UNITS
  DATABASE MICRONS 1000 ;
END UNITS


VERSION 5.7 ;
NAMESCASESENSITIVE ON ;
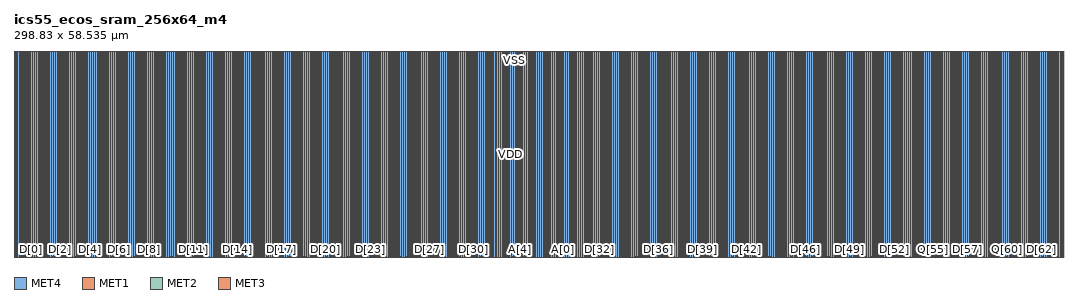
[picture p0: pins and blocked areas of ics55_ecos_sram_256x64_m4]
MACRO ics55_ecos_sram_256x64_m4
CLASS BLOCK ;
FOREIGN ics55_ecos_sram_256x64_m4 0.000 0.000 ;
ORIGIN 0.000 0.000 ;
SIZE 298.830 BY 58.535 ;
SYMMETRY X Y R90 ;

PIN VDD
  DIRECTION INOUT ;
  USE POWER ;
  PORT
    LAYER MET4 ;
    RECT 0.605 0.000 1.015 58.535 ;
    RECT 1.735 0.000 2.145 58.535 ;
    RECT 2.335 0.000 2.745 58.535 ;
    RECT 3.535 0.000 3.945 58.535 ;
    RECT 4.135 0.000 4.545 58.535 ;
    RECT 4.735 0.000 5.145 58.535 ;
    RECT 5.935 0.000 6.345 58.535 ;
    RECT 6.535 0.000 6.945 58.535 ;
    RECT 7.735 0.000 8.145 58.535 ;
    RECT 8.335 0.000 8.745 58.535 ;
    RECT 8.935 0.000 9.345 58.535 ;
    RECT 10.135 0.000 10.545 58.535 ;
    RECT 10.735 0.000 11.145 58.535 ;
    RECT 11.935 0.000 12.345 58.535 ;
    RECT 12.535 0.000 12.945 58.535 ;
    RECT 13.135 0.000 13.545 58.535 ;
    RECT 14.335 0.000 14.745 58.535 ;
    RECT 14.935 0.000 15.345 58.535 ;
    RECT 16.135 0.000 16.545 58.535 ;
    RECT 16.735 0.000 17.145 58.535 ;
    RECT 17.335 0.000 17.745 58.535 ;
    RECT 18.535 0.000 18.945 58.535 ;
    RECT 19.135 0.000 19.545 58.535 ;
    RECT 20.335 0.000 20.745 58.535 ;
    RECT 20.935 0.000 21.345 58.535 ;
    RECT 21.535 0.000 21.945 58.535 ;
    RECT 22.735 0.000 23.145 58.535 ;
    RECT 23.335 0.000 23.745 58.535 ;
    RECT 24.535 0.000 24.945 58.535 ;
    RECT 25.135 0.000 25.545 58.535 ;
    RECT 25.735 0.000 26.145 58.535 ;
    RECT 26.935 0.000 27.345 58.535 ;
    RECT 27.535 0.000 27.945 58.535 ;
    RECT 28.735 0.000 29.145 58.535 ;
    RECT 29.335 0.000 29.745 58.535 ;
    RECT 29.935 0.000 30.345 58.535 ;
    RECT 31.135 0.000 31.545 58.535 ;
    RECT 31.735 0.000 32.145 58.535 ;
    RECT 32.935 0.000 33.345 58.535 ;
    RECT 33.535 0.000 33.945 58.535 ;
    RECT 34.135 0.000 34.545 58.535 ;
    RECT 35.335 0.000 35.745 58.535 ;
    RECT 35.935 0.000 36.345 58.535 ;
    RECT 37.135 0.000 37.545 58.535 ;
    RECT 37.735 0.000 38.145 58.535 ;
    RECT 38.335 0.000 38.745 58.535 ;
    RECT 39.535 0.000 39.945 58.535 ;
    RECT 40.135 0.000 40.545 58.535 ;
    RECT 41.335 0.000 41.745 58.535 ;
    RECT 41.935 0.000 42.345 58.535 ;
    RECT 42.535 0.000 42.945 58.535 ;
    RECT 43.735 0.000 44.145 58.535 ;
    RECT 44.335 0.000 44.745 58.535 ;
    RECT 45.535 0.000 45.945 58.535 ;
    RECT 46.135 0.000 46.545 58.535 ;
    RECT 46.735 0.000 47.145 58.535 ;
    RECT 47.935 0.000 48.345 58.535 ;
    RECT 48.535 0.000 48.945 58.535 ;
    RECT 49.735 0.000 50.145 58.535 ;
    RECT 50.335 0.000 50.745 58.535 ;
    RECT 50.935 0.000 51.345 58.535 ;
    RECT 52.135 0.000 52.545 58.535 ;
    RECT 52.735 0.000 53.145 58.535 ;
    RECT 53.935 0.000 54.345 58.535 ;
    RECT 54.535 0.000 54.945 58.535 ;
    RECT 55.135 0.000 55.545 58.535 ;
    RECT 56.335 0.000 56.745 58.535 ;
    RECT 56.935 0.000 57.345 58.535 ;
    RECT 58.135 0.000 58.545 58.535 ;
    RECT 58.735 0.000 59.145 58.535 ;
    RECT 59.335 0.000 59.745 58.535 ;
    RECT 60.535 0.000 60.945 58.535 ;
    RECT 61.135 0.000 61.545 58.535 ;
    RECT 62.335 0.000 62.745 58.535 ;
    RECT 62.935 0.000 63.345 58.535 ;
    RECT 63.535 0.000 63.945 58.535 ;
    RECT 64.735 0.000 65.145 58.535 ;
    RECT 65.335 0.000 65.745 58.535 ;
    RECT 66.535 0.000 66.945 58.535 ;
    RECT 67.135 0.000 67.545 58.535 ;
    RECT 67.735 0.000 68.145 58.535 ;
    RECT 68.935 0.000 69.345 58.535 ;
    RECT 69.535 0.000 69.945 58.535 ;
    RECT 70.735 0.000 71.145 58.535 ;
    RECT 71.335 0.000 71.745 58.535 ;
    RECT 71.935 0.000 72.345 58.535 ;
    RECT 73.135 0.000 73.545 58.535 ;
    RECT 73.735 0.000 74.145 58.535 ;
    RECT 74.935 0.000 75.345 58.535 ;
    RECT 75.535 0.000 75.945 58.535 ;
    RECT 76.135 0.000 76.545 58.535 ;
    RECT 77.335 0.000 77.745 58.535 ;
    RECT 77.935 0.000 78.345 58.535 ;
    RECT 79.135 0.000 79.545 58.535 ;
    RECT 79.735 0.000 80.145 58.535 ;
    RECT 80.335 0.000 80.745 58.535 ;
    RECT 81.535 0.000 81.945 58.535 ;
    RECT 82.135 0.000 82.545 58.535 ;
    RECT 83.335 0.000 83.745 58.535 ;
    RECT 83.935 0.000 84.345 58.535 ;
    RECT 84.535 0.000 84.945 58.535 ;
    RECT 85.735 0.000 86.145 58.535 ;
    RECT 86.335 0.000 86.745 58.535 ;
    RECT 87.535 0.000 87.945 58.535 ;
    RECT 88.135 0.000 88.545 58.535 ;
    RECT 88.735 0.000 89.145 58.535 ;
    RECT 89.935 0.000 90.345 58.535 ;
    RECT 90.535 0.000 90.945 58.535 ;
    RECT 91.735 0.000 92.145 58.535 ;
    RECT 92.335 0.000 92.745 58.535 ;
    RECT 92.935 0.000 93.345 58.535 ;
    RECT 94.135 0.000 94.545 58.535 ;
    RECT 94.735 0.000 95.145 58.535 ;
    RECT 95.935 0.000 96.345 58.535 ;
    RECT 96.535 0.000 96.945 58.535 ;
    RECT 97.135 0.000 97.545 58.535 ;
    RECT 98.335 0.000 98.745 58.535 ;
    RECT 98.935 0.000 99.345 58.535 ;
    RECT 100.135 0.000 100.545 58.535 ;
    RECT 100.735 0.000 101.145 58.535 ;
    RECT 101.335 0.000 101.745 58.535 ;
    RECT 102.535 0.000 102.945 58.535 ;
    RECT 103.135 0.000 103.545 58.535 ;
    RECT 104.335 0.000 104.745 58.535 ;
    RECT 104.935 0.000 105.345 58.535 ;
    RECT 105.535 0.000 105.945 58.535 ;
    RECT 106.735 0.000 107.145 58.535 ;
    RECT 107.335 0.000 107.745 58.535 ;
    RECT 108.535 0.000 108.945 58.535 ;
    RECT 109.135 0.000 109.545 58.535 ;
    RECT 109.735 0.000 110.145 58.535 ;
    RECT 110.935 0.000 111.345 58.535 ;
    RECT 111.535 0.000 111.945 58.535 ;
    RECT 112.735 0.000 113.145 58.535 ;
    RECT 113.335 0.000 113.745 58.535 ;
    RECT 113.935 0.000 114.345 58.535 ;
    RECT 115.135 0.000 115.545 58.535 ;
    RECT 115.735 0.000 116.145 58.535 ;
    RECT 116.935 0.000 117.345 58.535 ;
    RECT 117.535 0.000 117.945 58.535 ;
    RECT 118.135 0.000 118.545 58.535 ;
    RECT 119.335 0.000 119.745 58.535 ;
    RECT 119.935 0.000 120.345 58.535 ;
    RECT 121.135 0.000 121.545 58.535 ;
    RECT 121.735 0.000 122.145 58.535 ;
    RECT 122.335 0.000 122.745 58.535 ;
    RECT 123.535 0.000 123.945 58.535 ;
    RECT 124.135 0.000 124.545 58.535 ;
    RECT 125.335 0.000 125.745 58.535 ;
    RECT 125.935 0.000 126.345 58.535 ;
    RECT 126.535 0.000 126.945 58.535 ;
    RECT 127.735 0.000 128.145 58.535 ;
    RECT 128.335 0.000 128.745 58.535 ;
    RECT 129.535 0.000 129.945 58.535 ;
    RECT 130.135 0.000 130.545 58.535 ;
    RECT 130.735 0.000 131.145 58.535 ;
    RECT 131.935 0.000 132.345 58.535 ;
    RECT 132.535 0.000 132.945 58.535 ;
    RECT 133.735 0.000 134.145 58.535 ;
    RECT 134.335 0.000 134.745 58.535 ;
    RECT 134.935 0.000 135.345 58.535 ;
    RECT 136.065 0.000 136.475 58.535 ;
    RECT 137.960 0.000 138.370 58.535 ;
    RECT 138.490 0.000 138.900 58.535 ;
    RECT 139.550 0.000 139.960 58.535 ;
    RECT 140.080 0.000 140.490 58.535 ;
    RECT 141.140 0.000 141.550 58.535 ;
    RECT 141.670 0.000 142.080 58.535 ;
    RECT 142.730 0.000 143.140 58.535 ;
    RECT 143.260 0.000 143.670 58.535 ;
    RECT 144.320 0.000 144.730 58.535 ;
    RECT 144.850 0.000 145.260 58.535 ;
    RECT 145.910 0.000 146.320 58.535 ;
    RECT 146.440 0.000 146.850 58.535 ;
    RECT 147.500 0.000 147.910 58.535 ;
    RECT 148.030 0.000 148.440 58.535 ;
    RECT 149.090 0.000 149.500 58.535 ;
    RECT 149.620 0.000 150.030 58.535 ;
    RECT 150.680 0.000 151.090 58.535 ;
    RECT 151.210 0.000 151.620 58.535 ;
    RECT 152.270 0.000 152.680 58.535 ;
    RECT 152.800 0.000 153.210 58.535 ;
    RECT 153.860 0.000 154.270 58.535 ;
    RECT 154.390 0.000 154.800 58.535 ;
    RECT 155.450 0.000 155.860 58.535 ;
    RECT 155.980 0.000 156.390 58.535 ;
    RECT 157.040 0.000 157.450 58.535 ;
    RECT 157.570 0.000 157.980 58.535 ;
    RECT 158.630 0.000 159.040 58.535 ;
    RECT 159.160 0.000 159.570 58.535 ;
    RECT 160.220 0.000 160.630 58.535 ;
    RECT 160.750 0.000 161.160 58.535 ;
    RECT 162.355 0.000 162.765 58.535 ;
    RECT 163.485 0.000 163.895 58.535 ;
    RECT 164.085 0.000 164.495 58.535 ;
    RECT 165.285 0.000 165.695 58.535 ;
    RECT 165.885 0.000 166.295 58.535 ;
    RECT 166.485 0.000 166.895 58.535 ;
    RECT 167.685 0.000 168.095 58.535 ;
    RECT 168.285 0.000 168.695 58.535 ;
    RECT 169.485 0.000 169.895 58.535 ;
    RECT 170.085 0.000 170.495 58.535 ;
    RECT 170.685 0.000 171.095 58.535 ;
    RECT 171.885 0.000 172.295 58.535 ;
    RECT 172.485 0.000 172.895 58.535 ;
    RECT 173.685 0.000 174.095 58.535 ;
    RECT 174.285 0.000 174.695 58.535 ;
    RECT 174.885 0.000 175.295 58.535 ;
    RECT 176.085 0.000 176.495 58.535 ;
    RECT 176.685 0.000 177.095 58.535 ;
    RECT 177.885 0.000 178.295 58.535 ;
    RECT 178.485 0.000 178.895 58.535 ;
    RECT 179.085 0.000 179.495 58.535 ;
    RECT 180.285 0.000 180.695 58.535 ;
    RECT 180.885 0.000 181.295 58.535 ;
    RECT 182.085 0.000 182.495 58.535 ;
    RECT 182.685 0.000 183.095 58.535 ;
    RECT 183.285 0.000 183.695 58.535 ;
    RECT 184.485 0.000 184.895 58.535 ;
    RECT 185.085 0.000 185.495 58.535 ;
    RECT 186.285 0.000 186.695 58.535 ;
    RECT 186.885 0.000 187.295 58.535 ;
    RECT 187.485 0.000 187.895 58.535 ;
    RECT 188.685 0.000 189.095 58.535 ;
    RECT 189.285 0.000 189.695 58.535 ;
    RECT 190.485 0.000 190.895 58.535 ;
    RECT 191.085 0.000 191.495 58.535 ;
    RECT 191.685 0.000 192.095 58.535 ;
    RECT 192.885 0.000 193.295 58.535 ;
    RECT 193.485 0.000 193.895 58.535 ;
    RECT 194.685 0.000 195.095 58.535 ;
    RECT 195.285 0.000 195.695 58.535 ;
    RECT 195.885 0.000 196.295 58.535 ;
    RECT 197.085 0.000 197.495 58.535 ;
    RECT 197.685 0.000 198.095 58.535 ;
    RECT 198.885 0.000 199.295 58.535 ;
    RECT 199.485 0.000 199.895 58.535 ;
    RECT 200.085 0.000 200.495 58.535 ;
    RECT 201.285 0.000 201.695 58.535 ;
    RECT 201.885 0.000 202.295 58.535 ;
    RECT 203.085 0.000 203.495 58.535 ;
    RECT 203.685 0.000 204.095 58.535 ;
    RECT 204.285 0.000 204.695 58.535 ;
    RECT 205.485 0.000 205.895 58.535 ;
    RECT 206.085 0.000 206.495 58.535 ;
    RECT 207.285 0.000 207.695 58.535 ;
    RECT 207.885 0.000 208.295 58.535 ;
    RECT 208.485 0.000 208.895 58.535 ;
    RECT 209.685 0.000 210.095 58.535 ;
    RECT 210.285 0.000 210.695 58.535 ;
    RECT 211.485 0.000 211.895 58.535 ;
    RECT 212.085 0.000 212.495 58.535 ;
    RECT 212.685 0.000 213.095 58.535 ;
    RECT 213.885 0.000 214.295 58.535 ;
    RECT 214.485 0.000 214.895 58.535 ;
    RECT 215.685 0.000 216.095 58.535 ;
    RECT 216.285 0.000 216.695 58.535 ;
    RECT 216.885 0.000 217.295 58.535 ;
    RECT 218.085 0.000 218.495 58.535 ;
    RECT 218.685 0.000 219.095 58.535 ;
    RECT 219.885 0.000 220.295 58.535 ;
    RECT 220.485 0.000 220.895 58.535 ;
    RECT 221.085 0.000 221.495 58.535 ;
    RECT 222.285 0.000 222.695 58.535 ;
    RECT 222.885 0.000 223.295 58.535 ;
    RECT 224.085 0.000 224.495 58.535 ;
    RECT 224.685 0.000 225.095 58.535 ;
    RECT 225.285 0.000 225.695 58.535 ;
    RECT 226.485 0.000 226.895 58.535 ;
    RECT 227.085 0.000 227.495 58.535 ;
    RECT 228.285 0.000 228.695 58.535 ;
    RECT 228.885 0.000 229.295 58.535 ;
    RECT 229.485 0.000 229.895 58.535 ;
    RECT 230.685 0.000 231.095 58.535 ;
    RECT 231.285 0.000 231.695 58.535 ;
    RECT 232.485 0.000 232.895 58.535 ;
    RECT 233.085 0.000 233.495 58.535 ;
    RECT 233.685 0.000 234.095 58.535 ;
    RECT 234.885 0.000 235.295 58.535 ;
    RECT 235.485 0.000 235.895 58.535 ;
    RECT 236.685 0.000 237.095 58.535 ;
    RECT 237.285 0.000 237.695 58.535 ;
    RECT 237.885 0.000 238.295 58.535 ;
    RECT 239.085 0.000 239.495 58.535 ;
    RECT 239.685 0.000 240.095 58.535 ;
    RECT 240.885 0.000 241.295 58.535 ;
    RECT 241.485 0.000 241.895 58.535 ;
    RECT 242.085 0.000 242.495 58.535 ;
    RECT 243.285 0.000 243.695 58.535 ;
    RECT 243.885 0.000 244.295 58.535 ;
    RECT 245.085 0.000 245.495 58.535 ;
    RECT 245.685 0.000 246.095 58.535 ;
    RECT 246.285 0.000 246.695 58.535 ;
    RECT 247.485 0.000 247.895 58.535 ;
    RECT 248.085 0.000 248.495 58.535 ;
    RECT 249.285 0.000 249.695 58.535 ;
    RECT 249.885 0.000 250.295 58.535 ;
    RECT 250.485 0.000 250.895 58.535 ;
    RECT 251.685 0.000 252.095 58.535 ;
    RECT 252.285 0.000 252.695 58.535 ;
    RECT 253.485 0.000 253.895 58.535 ;
    RECT 254.085 0.000 254.495 58.535 ;
    RECT 254.685 0.000 255.095 58.535 ;
    RECT 255.885 0.000 256.295 58.535 ;
    RECT 256.485 0.000 256.895 58.535 ;
    RECT 257.685 0.000 258.095 58.535 ;
    RECT 258.285 0.000 258.695 58.535 ;
    RECT 258.885 0.000 259.295 58.535 ;
    RECT 260.085 0.000 260.495 58.535 ;
    RECT 260.685 0.000 261.095 58.535 ;
    RECT 261.885 0.000 262.295 58.535 ;
    RECT 262.485 0.000 262.895 58.535 ;
    RECT 263.085 0.000 263.495 58.535 ;
    RECT 264.285 0.000 264.695 58.535 ;
    RECT 264.885 0.000 265.295 58.535 ;
    RECT 266.085 0.000 266.495 58.535 ;
    RECT 266.685 0.000 267.095 58.535 ;
    RECT 267.285 0.000 267.695 58.535 ;
    RECT 268.485 0.000 268.895 58.535 ;
    RECT 269.085 0.000 269.495 58.535 ;
    RECT 270.285 0.000 270.695 58.535 ;
    RECT 270.885 0.000 271.295 58.535 ;
    RECT 271.485 0.000 271.895 58.535 ;
    RECT 272.685 0.000 273.095 58.535 ;
    RECT 273.285 0.000 273.695 58.535 ;
    RECT 274.485 0.000 274.895 58.535 ;
    RECT 275.085 0.000 275.495 58.535 ;
    RECT 275.685 0.000 276.095 58.535 ;
    RECT 276.885 0.000 277.295 58.535 ;
    RECT 277.485 0.000 277.895 58.535 ;
    RECT 278.685 0.000 279.095 58.535 ;
    RECT 279.285 0.000 279.695 58.535 ;
    RECT 279.885 0.000 280.295 58.535 ;
    RECT 281.085 0.000 281.495 58.535 ;
    RECT 281.685 0.000 282.095 58.535 ;
    RECT 282.885 0.000 283.295 58.535 ;
    RECT 283.485 0.000 283.895 58.535 ;
    RECT 284.085 0.000 284.495 58.535 ;
    RECT 285.285 0.000 285.695 58.535 ;
    RECT 285.885 0.000 286.295 58.535 ;
    RECT 287.085 0.000 287.495 58.535 ;
    RECT 287.685 0.000 288.095 58.535 ;
    RECT 288.285 0.000 288.695 58.535 ;
    RECT 289.485 0.000 289.895 58.535 ;
    RECT 290.085 0.000 290.495 58.535 ;
    RECT 291.285 0.000 291.695 58.535 ;
    RECT 291.885 0.000 292.295 58.535 ;
    RECT 292.485 0.000 292.895 58.535 ;
    RECT 293.685 0.000 294.095 58.535 ;
    RECT 294.285 0.000 294.695 58.535 ;
    RECT 295.485 0.000 295.895 58.535 ;
    RECT 296.085 0.000 296.495 58.535 ;
    RECT 296.685 0.000 297.095 58.535 ;
    RECT 297.815 0.000 298.225 58.535 ;
  END
END VDD

PIN VSS
  DIRECTION INOUT ;
  USE GROUND ;
  PORT
    LAYER MET4 ;
    RECT 0.075 0.000 0.485 58.535 ;
    RECT 1.135 0.000 1.545 58.535 ;
    RECT 2.935 0.000 3.345 58.535 ;
    RECT 5.335 0.000 5.745 58.535 ;
    RECT 7.135 0.000 7.545 58.535 ;
    RECT 9.535 0.000 9.945 58.535 ;
    RECT 11.335 0.000 11.745 58.535 ;
    RECT 13.735 0.000 14.145 58.535 ;
    RECT 15.535 0.000 15.945 58.535 ;
    RECT 17.935 0.000 18.345 58.535 ;
    RECT 19.735 0.000 20.145 58.535 ;
    RECT 22.135 0.000 22.545 58.535 ;
    RECT 23.935 0.000 24.345 58.535 ;
    RECT 26.335 0.000 26.745 58.535 ;
    RECT 28.135 0.000 28.545 58.535 ;
    RECT 30.535 0.000 30.945 58.535 ;
    RECT 32.335 0.000 32.745 58.535 ;
    RECT 34.735 0.000 35.145 58.535 ;
    RECT 36.535 0.000 36.945 58.535 ;
    RECT 38.935 0.000 39.345 58.535 ;
    RECT 40.735 0.000 41.145 58.535 ;
    RECT 43.135 0.000 43.545 58.535 ;
    RECT 44.935 0.000 45.345 58.535 ;
    RECT 47.335 0.000 47.745 58.535 ;
    RECT 49.135 0.000 49.545 58.535 ;
    RECT 51.535 0.000 51.945 58.535 ;
    RECT 53.335 0.000 53.745 58.535 ;
    RECT 55.735 0.000 56.145 58.535 ;
    RECT 57.535 0.000 57.945 58.535 ;
    RECT 59.935 0.000 60.345 58.535 ;
    RECT 61.735 0.000 62.145 58.535 ;
    RECT 64.135 0.000 64.545 58.535 ;
    RECT 65.935 0.000 66.345 58.535 ;
    RECT 68.335 0.000 68.745 58.535 ;
    RECT 70.135 0.000 70.545 58.535 ;
    RECT 72.535 0.000 72.945 58.535 ;
    RECT 74.335 0.000 74.745 58.535 ;
    RECT 76.735 0.000 77.145 58.535 ;
    RECT 78.535 0.000 78.945 58.535 ;
    RECT 80.935 0.000 81.345 58.535 ;
    RECT 82.735 0.000 83.145 58.535 ;
    RECT 85.135 0.000 85.545 58.535 ;
    RECT 86.935 0.000 87.345 58.535 ;
    RECT 89.335 0.000 89.745 58.535 ;
    RECT 91.135 0.000 91.545 58.535 ;
    RECT 93.535 0.000 93.945 58.535 ;
    RECT 95.335 0.000 95.745 58.535 ;
    RECT 97.735 0.000 98.145 58.535 ;
    RECT 99.535 0.000 99.945 58.535 ;
    RECT 101.935 0.000 102.345 58.535 ;
    RECT 103.735 0.000 104.145 58.535 ;
    RECT 106.135 0.000 106.545 58.535 ;
    RECT 107.935 0.000 108.345 58.535 ;
    RECT 110.335 0.000 110.745 58.535 ;
    RECT 112.135 0.000 112.545 58.535 ;
    RECT 114.535 0.000 114.945 58.535 ;
    RECT 116.335 0.000 116.745 58.535 ;
    RECT 118.735 0.000 119.145 58.535 ;
    RECT 120.535 0.000 120.945 58.535 ;
    RECT 122.935 0.000 123.345 58.535 ;
    RECT 124.735 0.000 125.145 58.535 ;
    RECT 127.135 0.000 127.545 58.535 ;
    RECT 128.935 0.000 129.345 58.535 ;
    RECT 131.335 0.000 131.745 58.535 ;
    RECT 133.135 0.000 133.545 58.535 ;
    RECT 135.535 0.000 135.945 58.535 ;
    RECT 136.595 0.000 137.005 58.535 ;
    RECT 137.430 0.000 137.840 58.535 ;
    RECT 139.020 0.000 139.430 58.535 ;
    RECT 140.610 0.000 141.020 58.535 ;
    RECT 142.200 0.000 142.610 58.535 ;
    RECT 143.790 0.000 144.200 58.535 ;
    RECT 145.380 0.000 145.790 58.535 ;
    RECT 146.970 0.000 147.380 58.535 ;
    RECT 148.560 0.000 148.970 58.535 ;
    RECT 150.150 0.000 150.560 58.535 ;
    RECT 151.740 0.000 152.150 58.535 ;
    RECT 153.330 0.000 153.740 58.535 ;
    RECT 154.920 0.000 155.330 58.535 ;
    RECT 156.510 0.000 156.920 58.535 ;
    RECT 158.100 0.000 158.510 58.535 ;
    RECT 159.690 0.000 160.100 58.535 ;
    RECT 161.280 0.000 161.690 58.535 ;
    RECT 161.825 0.000 162.235 58.535 ;
    RECT 162.885 0.000 163.295 58.535 ;
    RECT 164.685 0.000 165.095 58.535 ;
    RECT 167.085 0.000 167.495 58.535 ;
    RECT 168.885 0.000 169.295 58.535 ;
    RECT 171.285 0.000 171.695 58.535 ;
    RECT 173.085 0.000 173.495 58.535 ;
    RECT 175.485 0.000 175.895 58.535 ;
    RECT 177.285 0.000 177.695 58.535 ;
    RECT 179.685 0.000 180.095 58.535 ;
    RECT 181.485 0.000 181.895 58.535 ;
    RECT 183.885 0.000 184.295 58.535 ;
    RECT 185.685 0.000 186.095 58.535 ;
    RECT 188.085 0.000 188.495 58.535 ;
    RECT 189.885 0.000 190.295 58.535 ;
    RECT 192.285 0.000 192.695 58.535 ;
    RECT 194.085 0.000 194.495 58.535 ;
    RECT 196.485 0.000 196.895 58.535 ;
    RECT 198.285 0.000 198.695 58.535 ;
    RECT 200.685 0.000 201.095 58.535 ;
    RECT 202.485 0.000 202.895 58.535 ;
    RECT 204.885 0.000 205.295 58.535 ;
    RECT 206.685 0.000 207.095 58.535 ;
    RECT 209.085 0.000 209.495 58.535 ;
    RECT 210.885 0.000 211.295 58.535 ;
    RECT 213.285 0.000 213.695 58.535 ;
    RECT 215.085 0.000 215.495 58.535 ;
    RECT 217.485 0.000 217.895 58.535 ;
    RECT 219.285 0.000 219.695 58.535 ;
    RECT 221.685 0.000 222.095 58.535 ;
    RECT 223.485 0.000 223.895 58.535 ;
    RECT 225.885 0.000 226.295 58.535 ;
    RECT 227.685 0.000 228.095 58.535 ;
    RECT 230.085 0.000 230.495 58.535 ;
    RECT 231.885 0.000 232.295 58.535 ;
    RECT 234.285 0.000 234.695 58.535 ;
    RECT 236.085 0.000 236.495 58.535 ;
    RECT 238.485 0.000 238.895 58.535 ;
    RECT 240.285 0.000 240.695 58.535 ;
    RECT 242.685 0.000 243.095 58.535 ;
    RECT 244.485 0.000 244.895 58.535 ;
    RECT 246.885 0.000 247.295 58.535 ;
    RECT 248.685 0.000 249.095 58.535 ;
    RECT 251.085 0.000 251.495 58.535 ;
    RECT 252.885 0.000 253.295 58.535 ;
    RECT 255.285 0.000 255.695 58.535 ;
    RECT 257.085 0.000 257.495 58.535 ;
    RECT 259.485 0.000 259.895 58.535 ;
    RECT 261.285 0.000 261.695 58.535 ;
    RECT 263.685 0.000 264.095 58.535 ;
    RECT 265.485 0.000 265.895 58.535 ;
    RECT 267.885 0.000 268.295 58.535 ;
    RECT 269.685 0.000 270.095 58.535 ;
    RECT 272.085 0.000 272.495 58.535 ;
    RECT 273.885 0.000 274.295 58.535 ;
    RECT 276.285 0.000 276.695 58.535 ;
    RECT 278.085 0.000 278.495 58.535 ;
    RECT 280.485 0.000 280.895 58.535 ;
    RECT 282.285 0.000 282.695 58.535 ;
    RECT 284.685 0.000 285.095 58.535 ;
    RECT 286.485 0.000 286.895 58.535 ;
    RECT 288.885 0.000 289.295 58.535 ;
    RECT 290.685 0.000 291.095 58.535 ;
    RECT 293.085 0.000 293.495 58.535 ;
    RECT 294.885 0.000 295.295 58.535 ;
    RECT 297.285 0.000 297.695 58.535 ;
    RECT 298.345 0.000 298.755 58.535 ;
  END
END VSS

PIN D[0]
  DIRECTION INPUT ;
  PORT
    LAYER MET1 ;
    RECT 4.540 0.000 4.950 0.180 ;
    LAYER MET2 ;
    RECT 4.540 0.000 4.950 0.180 ;
    LAYER MET3 ;
    RECT 4.540 0.000 4.950 0.180 ;
  END
  ANTENNADIFFAREA                0.38930         LAYER MET1 ;
  ANTENNADIFFAREA                0.38930         LAYER MET2 ;
  ANTENNADIFFAREA                0.38930         LAYER MET3 ;
  ANTENNAGATEAREA                0.06300         LAYER MET1 ;
  ANTENNAGATEAREA                0.06300         LAYER MET2 ;
  ANTENNAGATEAREA                0.06300         LAYER MET3 ;
  ANTENNAPARTIALMETALAREA        0.09890         LAYER MET1 ;
  ANTENNAPARTIALMETALAREA        0.10380         LAYER MET2 ;
  ANTENNAMAXAREACAR              0.72381         LAYER MET1 ;
  ANTENNAMAXAREACAR              3.54286         LAYER MET2 ;
  ANTENNAMAXAREACAR              4.71429         LAYER MET3 ;
END D[0]
PIN WEB[0]
  DIRECTION INPUT ;
  PORT
    LAYER MET1 ;
    RECT 2.190 0.000 2.600 0.180 ;
    LAYER MET2 ;
    RECT 2.190 0.000 2.600 0.180 ;
    LAYER MET3 ;
    RECT 2.190 0.000 2.600 0.180 ;
  END
  ANTENNADIFFAREA                0.45930         LAYER MET1 ;
  ANTENNADIFFAREA                0.45930         LAYER MET2 ;
  ANTENNADIFFAREA                0.45930         LAYER MET3 ;
  ANTENNAGATEAREA                0.08100         LAYER MET1 ;
  ANTENNAGATEAREA                0.08100         LAYER MET2 ;
  ANTENNAGATEAREA                0.08100         LAYER MET3 ;
  ANTENNAPARTIALMETALAREA        0.14210         LAYER MET1 ;
  ANTENNAPARTIALMETALAREA        0.09360         LAYER MET2 ;
  ANTENNAMAXAREACAR              1.09630         LAYER MET1 ;
  ANTENNAMAXAREACAR              3.16296         LAYER MET2 ;
  ANTENNAMAXAREACAR              4.07407         LAYER MET3 ;
END WEB[0]
PIN Q[0]
  DIRECTION OUTPUT ;
  PORT
    LAYER MET1 ;
    RECT 3.000 0.000 3.410 0.180 ;
    LAYER MET2 ;
    RECT 3.000 0.000 3.410 0.180 ;
    LAYER MET3 ;
    RECT 3.000 0.000 3.410 0.180 ;
  END
  ANTENNADIFFAREA                0.60000         LAYER MET1 ;
  ANTENNADIFFAREA                0.60000         LAYER MET2 ;
  ANTENNADIFFAREA                0.60000         LAYER MET3 ;
  ANTENNAPARTIALMETALAREA        0.94400         LAYER MET1 ;
  ANTENNAPARTIALMETALAREA        1.33320         LAYER MET2 ;
END Q[0]
PIN D[1]
  DIRECTION INPUT ;
  PORT
    LAYER MET1 ;
    RECT 8.740 0.000 9.150 0.180 ;
    LAYER MET2 ;
    RECT 8.740 0.000 9.150 0.180 ;
    LAYER MET3 ;
    RECT 8.740 0.000 9.150 0.180 ;
  END
  ANTENNADIFFAREA                0.38930         LAYER MET1 ;
  ANTENNADIFFAREA                0.38930         LAYER MET2 ;
  ANTENNADIFFAREA                0.38930         LAYER MET3 ;
  ANTENNAGATEAREA                0.06300         LAYER MET1 ;
  ANTENNAGATEAREA                0.06300         LAYER MET2 ;
  ANTENNAGATEAREA                0.06300         LAYER MET3 ;
  ANTENNAPARTIALMETALAREA        0.09890         LAYER MET1 ;
  ANTENNAPARTIALMETALAREA        0.10380         LAYER MET2 ;
  ANTENNAMAXAREACAR              0.72381         LAYER MET1 ;
  ANTENNAMAXAREACAR              3.54286         LAYER MET2 ;
  ANTENNAMAXAREACAR              4.71429         LAYER MET3 ;
END D[1]
PIN Q[1]
  DIRECTION OUTPUT ;
  PORT
    LAYER MET1 ;
    RECT 7.200 0.000 7.610 0.180 ;
    LAYER MET2 ;
    RECT 7.200 0.000 7.610 0.180 ;
    LAYER MET3 ;
    RECT 7.200 0.000 7.610 0.180 ;
  END
  ANTENNADIFFAREA                0.60000         LAYER MET1 ;
  ANTENNADIFFAREA                0.60000         LAYER MET2 ;
  ANTENNADIFFAREA                0.60000         LAYER MET3 ;
  ANTENNAPARTIALMETALAREA        0.94400         LAYER MET1 ;
  ANTENNAPARTIALMETALAREA        1.33320         LAYER MET2 ;
END Q[1]
PIN WEB[1]
  DIRECTION INPUT ;
  PORT
    LAYER MET1 ;
    RECT 6.390 0.000 6.800 0.180 ;
    LAYER MET2 ;
    RECT 6.390 0.000 6.800 0.180 ;
    LAYER MET3 ;
    RECT 6.390 0.000 6.800 0.180 ;
  END
  ANTENNADIFFAREA                0.45930         LAYER MET1 ;
  ANTENNADIFFAREA                0.45930         LAYER MET2 ;
  ANTENNADIFFAREA                0.45930         LAYER MET3 ;
  ANTENNAGATEAREA                0.08100         LAYER MET1 ;
  ANTENNAGATEAREA                0.08100         LAYER MET2 ;
  ANTENNAGATEAREA                0.08100         LAYER MET3 ;
  ANTENNAPARTIALMETALAREA        0.14210         LAYER MET1 ;
  ANTENNAPARTIALMETALAREA        0.09360         LAYER MET2 ;
  ANTENNAMAXAREACAR              1.09630         LAYER MET1 ;
  ANTENNAMAXAREACAR              3.16296         LAYER MET2 ;
  ANTENNAMAXAREACAR              4.07407         LAYER MET3 ;
END WEB[1]
PIN D[2]
  DIRECTION INPUT ;
  PORT
    LAYER MET1 ;
    RECT 12.940 0.000 13.350 0.180 ;
    LAYER MET2 ;
    RECT 12.940 0.000 13.350 0.180 ;
    LAYER MET3 ;
    RECT 12.940 0.000 13.350 0.180 ;
  END
  ANTENNADIFFAREA                0.38930         LAYER MET1 ;
  ANTENNADIFFAREA                0.38930         LAYER MET2 ;
  ANTENNADIFFAREA                0.38930         LAYER MET3 ;
  ANTENNAGATEAREA                0.06300         LAYER MET1 ;
  ANTENNAGATEAREA                0.06300         LAYER MET2 ;
  ANTENNAGATEAREA                0.06300         LAYER MET3 ;
  ANTENNAPARTIALMETALAREA        0.09890         LAYER MET1 ;
  ANTENNAPARTIALMETALAREA        0.10380         LAYER MET2 ;
  ANTENNAMAXAREACAR              0.72381         LAYER MET1 ;
  ANTENNAMAXAREACAR              3.54286         LAYER MET2 ;
  ANTENNAMAXAREACAR              4.71429         LAYER MET3 ;
END D[2]
PIN Q[2]
  DIRECTION OUTPUT ;
  PORT
    LAYER MET1 ;
    RECT 11.400 0.000 11.810 0.180 ;
    LAYER MET2 ;
    RECT 11.400 0.000 11.810 0.180 ;
    LAYER MET3 ;
    RECT 11.400 0.000 11.810 0.180 ;
  END
  ANTENNADIFFAREA                0.60000         LAYER MET1 ;
  ANTENNADIFFAREA                0.60000         LAYER MET2 ;
  ANTENNADIFFAREA                0.60000         LAYER MET3 ;
  ANTENNAPARTIALMETALAREA        0.94400         LAYER MET1 ;
  ANTENNAPARTIALMETALAREA        1.33320         LAYER MET2 ;
END Q[2]
PIN WEB[2]
  DIRECTION INPUT ;
  PORT
    LAYER MET1 ;
    RECT 10.590 0.000 11.000 0.180 ;
    LAYER MET2 ;
    RECT 10.590 0.000 11.000 0.180 ;
    LAYER MET3 ;
    RECT 10.590 0.000 11.000 0.180 ;
  END
  ANTENNADIFFAREA                0.45930         LAYER MET1 ;
  ANTENNADIFFAREA                0.45930         LAYER MET2 ;
  ANTENNADIFFAREA                0.45930         LAYER MET3 ;
  ANTENNAGATEAREA                0.08100         LAYER MET1 ;
  ANTENNAGATEAREA                0.08100         LAYER MET2 ;
  ANTENNAGATEAREA                0.08100         LAYER MET3 ;
  ANTENNAPARTIALMETALAREA        0.14210         LAYER MET1 ;
  ANTENNAPARTIALMETALAREA        0.09360         LAYER MET2 ;
  ANTENNAMAXAREACAR              1.09630         LAYER MET1 ;
  ANTENNAMAXAREACAR              3.16296         LAYER MET2 ;
  ANTENNAMAXAREACAR              4.07407         LAYER MET3 ;
END WEB[2]
PIN WEB[5]
  DIRECTION INPUT ;
  PORT
    LAYER MET1 ;
    RECT 23.190 0.000 23.600 0.180 ;
    LAYER MET2 ;
    RECT 23.190 0.000 23.600 0.180 ;
    LAYER MET3 ;
    RECT 23.190 0.000 23.600 0.180 ;
  END
  ANTENNADIFFAREA                0.45930         LAYER MET1 ;
  ANTENNADIFFAREA                0.45930         LAYER MET2 ;
  ANTENNADIFFAREA                0.45930         LAYER MET3 ;
  ANTENNAGATEAREA                0.08100         LAYER MET1 ;
  ANTENNAGATEAREA                0.08100         LAYER MET2 ;
  ANTENNAGATEAREA                0.08100         LAYER MET3 ;
  ANTENNAPARTIALMETALAREA        0.14210         LAYER MET1 ;
  ANTENNAPARTIALMETALAREA        0.09360         LAYER MET2 ;
  ANTENNAMAXAREACAR              1.09630         LAYER MET1 ;
  ANTENNAMAXAREACAR              3.16296         LAYER MET2 ;
  ANTENNAMAXAREACAR              4.07407         LAYER MET3 ;
END WEB[5]
PIN D[6]
  DIRECTION INPUT ;
  PORT
    LAYER MET1 ;
    RECT 29.740 0.000 30.150 0.180 ;
    LAYER MET2 ;
    RECT 29.740 0.000 30.150 0.180 ;
    LAYER MET3 ;
    RECT 29.740 0.000 30.150 0.180 ;
  END
  ANTENNADIFFAREA                0.38930         LAYER MET1 ;
  ANTENNADIFFAREA                0.38930         LAYER MET2 ;
  ANTENNADIFFAREA                0.38930         LAYER MET3 ;
  ANTENNAGATEAREA                0.06300         LAYER MET1 ;
  ANTENNAGATEAREA                0.06300         LAYER MET2 ;
  ANTENNAGATEAREA                0.06300         LAYER MET3 ;
  ANTENNAPARTIALMETALAREA        0.09890         LAYER MET1 ;
  ANTENNAPARTIALMETALAREA        0.10380         LAYER MET2 ;
  ANTENNAMAXAREACAR              0.72381         LAYER MET1 ;
  ANTENNAMAXAREACAR              3.54286         LAYER MET2 ;
  ANTENNAMAXAREACAR              4.71429         LAYER MET3 ;
END D[6]
PIN D[3]
  DIRECTION INPUT ;
  PORT
    LAYER MET1 ;
    RECT 17.140 0.000 17.550 0.180 ;
    LAYER MET2 ;
    RECT 17.140 0.000 17.550 0.180 ;
    LAYER MET3 ;
    RECT 17.140 0.000 17.550 0.180 ;
  END
  ANTENNADIFFAREA                0.38930         LAYER MET1 ;
  ANTENNADIFFAREA                0.38930         LAYER MET2 ;
  ANTENNADIFFAREA                0.38930         LAYER MET3 ;
  ANTENNAGATEAREA                0.06300         LAYER MET1 ;
  ANTENNAGATEAREA                0.06300         LAYER MET2 ;
  ANTENNAGATEAREA                0.06300         LAYER MET3 ;
  ANTENNAPARTIALMETALAREA        0.09890         LAYER MET1 ;
  ANTENNAPARTIALMETALAREA        0.10380         LAYER MET2 ;
  ANTENNAMAXAREACAR              0.72381         LAYER MET1 ;
  ANTENNAMAXAREACAR              3.54286         LAYER MET2 ;
  ANTENNAMAXAREACAR              4.71429         LAYER MET3 ;
END D[3]
PIN Q[3]
  DIRECTION OUTPUT ;
  PORT
    LAYER MET1 ;
    RECT 15.600 0.000 16.010 0.180 ;
    LAYER MET2 ;
    RECT 15.600 0.000 16.010 0.180 ;
    LAYER MET3 ;
    RECT 15.600 0.000 16.010 0.180 ;
  END
  ANTENNADIFFAREA                0.60000         LAYER MET1 ;
  ANTENNADIFFAREA                0.60000         LAYER MET2 ;
  ANTENNADIFFAREA                0.60000         LAYER MET3 ;
  ANTENNAPARTIALMETALAREA        0.94400         LAYER MET1 ;
  ANTENNAPARTIALMETALAREA        1.33320         LAYER MET2 ;
END Q[3]
PIN WEB[3]
  DIRECTION INPUT ;
  PORT
    LAYER MET1 ;
    RECT 14.790 0.000 15.200 0.180 ;
    LAYER MET2 ;
    RECT 14.790 0.000 15.200 0.180 ;
    LAYER MET3 ;
    RECT 14.790 0.000 15.200 0.180 ;
  END
  ANTENNADIFFAREA                0.45930         LAYER MET1 ;
  ANTENNADIFFAREA                0.45930         LAYER MET2 ;
  ANTENNADIFFAREA                0.45930         LAYER MET3 ;
  ANTENNAGATEAREA                0.08100         LAYER MET1 ;
  ANTENNAGATEAREA                0.08100         LAYER MET2 ;
  ANTENNAGATEAREA                0.08100         LAYER MET3 ;
  ANTENNAPARTIALMETALAREA        0.14210         LAYER MET1 ;
  ANTENNAPARTIALMETALAREA        0.09360         LAYER MET2 ;
  ANTENNAMAXAREACAR              1.09630         LAYER MET1 ;
  ANTENNAMAXAREACAR              3.16296         LAYER MET2 ;
  ANTENNAMAXAREACAR              4.07407         LAYER MET3 ;
END WEB[3]
PIN D[4]
  DIRECTION INPUT ;
  PORT
    LAYER MET1 ;
    RECT 21.340 0.000 21.750 0.180 ;
    LAYER MET2 ;
    RECT 21.340 0.000 21.750 0.180 ;
    LAYER MET3 ;
    RECT 21.340 0.000 21.750 0.180 ;
  END
  ANTENNADIFFAREA                0.38930         LAYER MET1 ;
  ANTENNADIFFAREA                0.38930         LAYER MET2 ;
  ANTENNADIFFAREA                0.38930         LAYER MET3 ;
  ANTENNAGATEAREA                0.06300         LAYER MET1 ;
  ANTENNAGATEAREA                0.06300         LAYER MET2 ;
  ANTENNAGATEAREA                0.06300         LAYER MET3 ;
  ANTENNAPARTIALMETALAREA        0.09890         LAYER MET1 ;
  ANTENNAPARTIALMETALAREA        0.10380         LAYER MET2 ;
  ANTENNAMAXAREACAR              0.72381         LAYER MET1 ;
  ANTENNAMAXAREACAR              3.54286         LAYER MET2 ;
  ANTENNAMAXAREACAR              4.71429         LAYER MET3 ;
END D[4]
PIN Q[4]
  DIRECTION OUTPUT ;
  PORT
    LAYER MET1 ;
    RECT 19.800 0.000 20.210 0.180 ;
    LAYER MET2 ;
    RECT 19.800 0.000 20.210 0.180 ;
    LAYER MET3 ;
    RECT 19.800 0.000 20.210 0.180 ;
  END
  ANTENNADIFFAREA                0.60000         LAYER MET1 ;
  ANTENNADIFFAREA                0.60000         LAYER MET2 ;
  ANTENNADIFFAREA                0.60000         LAYER MET3 ;
  ANTENNAPARTIALMETALAREA        0.94400         LAYER MET1 ;
  ANTENNAPARTIALMETALAREA        1.33320         LAYER MET2 ;
END Q[4]
PIN WEB[4]
  DIRECTION INPUT ;
  PORT
    LAYER MET1 ;
    RECT 18.990 0.000 19.400 0.180 ;
    LAYER MET2 ;
    RECT 18.990 0.000 19.400 0.180 ;
    LAYER MET3 ;
    RECT 18.990 0.000 19.400 0.180 ;
  END
  ANTENNADIFFAREA                0.45930         LAYER MET1 ;
  ANTENNADIFFAREA                0.45930         LAYER MET2 ;
  ANTENNADIFFAREA                0.45930         LAYER MET3 ;
  ANTENNAGATEAREA                0.08100         LAYER MET1 ;
  ANTENNAGATEAREA                0.08100         LAYER MET2 ;
  ANTENNAGATEAREA                0.08100         LAYER MET3 ;
  ANTENNAPARTIALMETALAREA        0.14210         LAYER MET1 ;
  ANTENNAPARTIALMETALAREA        0.09360         LAYER MET2 ;
  ANTENNAMAXAREACAR              1.09630         LAYER MET1 ;
  ANTENNAMAXAREACAR              3.16296         LAYER MET2 ;
  ANTENNAMAXAREACAR              4.07407         LAYER MET3 ;
END WEB[4]
PIN D[5]
  DIRECTION INPUT ;
  PORT
    LAYER MET1 ;
    RECT 25.540 0.000 25.950 0.180 ;
    LAYER MET2 ;
    RECT 25.540 0.000 25.950 0.180 ;
    LAYER MET3 ;
    RECT 25.540 0.000 25.950 0.180 ;
  END
  ANTENNADIFFAREA                0.38930         LAYER MET1 ;
  ANTENNADIFFAREA                0.38930         LAYER MET2 ;
  ANTENNADIFFAREA                0.38930         LAYER MET3 ;
  ANTENNAGATEAREA                0.06300         LAYER MET1 ;
  ANTENNAGATEAREA                0.06300         LAYER MET2 ;
  ANTENNAGATEAREA                0.06300         LAYER MET3 ;
  ANTENNAPARTIALMETALAREA        0.09890         LAYER MET1 ;
  ANTENNAPARTIALMETALAREA        0.10380         LAYER MET2 ;
  ANTENNAMAXAREACAR              0.72381         LAYER MET1 ;
  ANTENNAMAXAREACAR              3.54286         LAYER MET2 ;
  ANTENNAMAXAREACAR              4.71429         LAYER MET3 ;
END D[5]
PIN Q[5]
  DIRECTION OUTPUT ;
  PORT
    LAYER MET1 ;
    RECT 24.000 0.000 24.410 0.180 ;
    LAYER MET2 ;
    RECT 24.000 0.000 24.410 0.180 ;
    LAYER MET3 ;
    RECT 24.000 0.000 24.410 0.180 ;
  END
  ANTENNADIFFAREA                0.60000         LAYER MET1 ;
  ANTENNADIFFAREA                0.60000         LAYER MET2 ;
  ANTENNADIFFAREA                0.60000         LAYER MET3 ;
  ANTENNAPARTIALMETALAREA        0.94400         LAYER MET1 ;
  ANTENNAPARTIALMETALAREA        1.33320         LAYER MET2 ;
END Q[5]
PIN D[11]
  DIRECTION INPUT ;
  PORT
    LAYER MET1 ;
    RECT 50.740 0.000 51.150 0.180 ;
    LAYER MET2 ;
    RECT 50.740 0.000 51.150 0.180 ;
    LAYER MET3 ;
    RECT 50.740 0.000 51.150 0.180 ;
  END
  ANTENNADIFFAREA                0.38930         LAYER MET1 ;
  ANTENNADIFFAREA                0.38930         LAYER MET2 ;
  ANTENNADIFFAREA                0.38930         LAYER MET3 ;
  ANTENNAGATEAREA                0.06300         LAYER MET1 ;
  ANTENNAGATEAREA                0.06300         LAYER MET2 ;
  ANTENNAGATEAREA                0.06300         LAYER MET3 ;
  ANTENNAPARTIALMETALAREA        0.09890         LAYER MET1 ;
  ANTENNAPARTIALMETALAREA        0.10380         LAYER MET2 ;
  ANTENNAMAXAREACAR              0.72381         LAYER MET1 ;
  ANTENNAMAXAREACAR              3.54286         LAYER MET2 ;
  ANTENNAMAXAREACAR              4.71429         LAYER MET3 ;
END D[11]
PIN Q[6]
  DIRECTION OUTPUT ;
  PORT
    LAYER MET1 ;
    RECT 28.200 0.000 28.610 0.180 ;
    LAYER MET2 ;
    RECT 28.200 0.000 28.610 0.180 ;
    LAYER MET3 ;
    RECT 28.200 0.000 28.610 0.180 ;
  END
  ANTENNADIFFAREA                0.60000         LAYER MET1 ;
  ANTENNADIFFAREA                0.60000         LAYER MET2 ;
  ANTENNADIFFAREA                0.60000         LAYER MET3 ;
  ANTENNAPARTIALMETALAREA        0.94400         LAYER MET1 ;
  ANTENNAPARTIALMETALAREA        1.33320         LAYER MET2 ;
END Q[6]
PIN WEB[6]
  DIRECTION INPUT ;
  PORT
    LAYER MET1 ;
    RECT 27.390 0.000 27.800 0.180 ;
    LAYER MET2 ;
    RECT 27.390 0.000 27.800 0.180 ;
    LAYER MET3 ;
    RECT 27.390 0.000 27.800 0.180 ;
  END
  ANTENNADIFFAREA                0.45930         LAYER MET1 ;
  ANTENNADIFFAREA                0.45930         LAYER MET2 ;
  ANTENNADIFFAREA                0.45930         LAYER MET3 ;
  ANTENNAGATEAREA                0.08100         LAYER MET1 ;
  ANTENNAGATEAREA                0.08100         LAYER MET2 ;
  ANTENNAGATEAREA                0.08100         LAYER MET3 ;
  ANTENNAPARTIALMETALAREA        0.14210         LAYER MET1 ;
  ANTENNAPARTIALMETALAREA        0.09360         LAYER MET2 ;
  ANTENNAMAXAREACAR              1.09630         LAYER MET1 ;
  ANTENNAMAXAREACAR              3.16296         LAYER MET2 ;
  ANTENNAMAXAREACAR              4.07407         LAYER MET3 ;
END WEB[6]
PIN D[7]
  DIRECTION INPUT ;
  PORT
    LAYER MET1 ;
    RECT 33.940 0.000 34.350 0.180 ;
    LAYER MET2 ;
    RECT 33.940 0.000 34.350 0.180 ;
    LAYER MET3 ;
    RECT 33.940 0.000 34.350 0.180 ;
  END
  ANTENNADIFFAREA                0.38930         LAYER MET1 ;
  ANTENNADIFFAREA                0.38930         LAYER MET2 ;
  ANTENNADIFFAREA                0.38930         LAYER MET3 ;
  ANTENNAGATEAREA                0.06300         LAYER MET1 ;
  ANTENNAGATEAREA                0.06300         LAYER MET2 ;
  ANTENNAGATEAREA                0.06300         LAYER MET3 ;
  ANTENNAPARTIALMETALAREA        0.09890         LAYER MET1 ;
  ANTENNAPARTIALMETALAREA        0.10380         LAYER MET2 ;
  ANTENNAMAXAREACAR              0.72381         LAYER MET1 ;
  ANTENNAMAXAREACAR              3.54286         LAYER MET2 ;
  ANTENNAMAXAREACAR              4.71429         LAYER MET3 ;
END D[7]
PIN Q[7]
  DIRECTION OUTPUT ;
  PORT
    LAYER MET1 ;
    RECT 32.400 0.000 32.810 0.180 ;
    LAYER MET2 ;
    RECT 32.400 0.000 32.810 0.180 ;
    LAYER MET3 ;
    RECT 32.400 0.000 32.810 0.180 ;
  END
  ANTENNADIFFAREA                0.60000         LAYER MET1 ;
  ANTENNADIFFAREA                0.60000         LAYER MET2 ;
  ANTENNADIFFAREA                0.60000         LAYER MET3 ;
  ANTENNAPARTIALMETALAREA        0.94400         LAYER MET1 ;
  ANTENNAPARTIALMETALAREA        1.33320         LAYER MET2 ;
END Q[7]
PIN WEB[7]
  DIRECTION INPUT ;
  PORT
    LAYER MET1 ;
    RECT 31.590 0.000 32.000 0.180 ;
    LAYER MET2 ;
    RECT 31.590 0.000 32.000 0.180 ;
    LAYER MET3 ;
    RECT 31.590 0.000 32.000 0.180 ;
  END
  ANTENNADIFFAREA                0.45930         LAYER MET1 ;
  ANTENNADIFFAREA                0.45930         LAYER MET2 ;
  ANTENNADIFFAREA                0.45930         LAYER MET3 ;
  ANTENNAGATEAREA                0.08100         LAYER MET1 ;
  ANTENNAGATEAREA                0.08100         LAYER MET2 ;
  ANTENNAGATEAREA                0.08100         LAYER MET3 ;
  ANTENNAPARTIALMETALAREA        0.14210         LAYER MET1 ;
  ANTENNAPARTIALMETALAREA        0.09360         LAYER MET2 ;
  ANTENNAMAXAREACAR              1.09630         LAYER MET1 ;
  ANTENNAMAXAREACAR              3.16296         LAYER MET2 ;
  ANTENNAMAXAREACAR              4.07407         LAYER MET3 ;
END WEB[7]
PIN D[8]
  DIRECTION INPUT ;
  PORT
    LAYER MET1 ;
    RECT 38.140 0.000 38.550 0.180 ;
    LAYER MET2 ;
    RECT 38.140 0.000 38.550 0.180 ;
    LAYER MET3 ;
    RECT 38.140 0.000 38.550 0.180 ;
  END
  ANTENNADIFFAREA                0.38930         LAYER MET1 ;
  ANTENNADIFFAREA                0.38930         LAYER MET2 ;
  ANTENNADIFFAREA                0.38930         LAYER MET3 ;
  ANTENNAGATEAREA                0.06300         LAYER MET1 ;
  ANTENNAGATEAREA                0.06300         LAYER MET2 ;
  ANTENNAGATEAREA                0.06300         LAYER MET3 ;
  ANTENNAPARTIALMETALAREA        0.09890         LAYER MET1 ;
  ANTENNAPARTIALMETALAREA        0.10380         LAYER MET2 ;
  ANTENNAMAXAREACAR              0.72381         LAYER MET1 ;
  ANTENNAMAXAREACAR              3.54286         LAYER MET2 ;
  ANTENNAMAXAREACAR              4.71429         LAYER MET3 ;
END D[8]
PIN Q[8]
  DIRECTION OUTPUT ;
  PORT
    LAYER MET1 ;
    RECT 36.600 0.000 37.010 0.180 ;
    LAYER MET2 ;
    RECT 36.600 0.000 37.010 0.180 ;
    LAYER MET3 ;
    RECT 36.600 0.000 37.010 0.180 ;
  END
  ANTENNADIFFAREA                0.60000         LAYER MET1 ;
  ANTENNADIFFAREA                0.60000         LAYER MET2 ;
  ANTENNADIFFAREA                0.60000         LAYER MET3 ;
  ANTENNAPARTIALMETALAREA        0.94400         LAYER MET1 ;
  ANTENNAPARTIALMETALAREA        1.33320         LAYER MET2 ;
END Q[8]
PIN WEB[8]
  DIRECTION INPUT ;
  PORT
    LAYER MET1 ;
    RECT 35.790 0.000 36.200 0.180 ;
    LAYER MET2 ;
    RECT 35.790 0.000 36.200 0.180 ;
    LAYER MET3 ;
    RECT 35.790 0.000 36.200 0.180 ;
  END
  ANTENNADIFFAREA                0.45930         LAYER MET1 ;
  ANTENNADIFFAREA                0.45930         LAYER MET2 ;
  ANTENNADIFFAREA                0.45930         LAYER MET3 ;
  ANTENNAGATEAREA                0.08100         LAYER MET1 ;
  ANTENNAGATEAREA                0.08100         LAYER MET2 ;
  ANTENNAGATEAREA                0.08100         LAYER MET3 ;
  ANTENNAPARTIALMETALAREA        0.14210         LAYER MET1 ;
  ANTENNAPARTIALMETALAREA        0.09360         LAYER MET2 ;
  ANTENNAMAXAREACAR              1.09630         LAYER MET1 ;
  ANTENNAMAXAREACAR              3.16296         LAYER MET2 ;
  ANTENNAMAXAREACAR              4.07407         LAYER MET3 ;
END WEB[8]
PIN D[9]
  DIRECTION INPUT ;
  PORT
    LAYER MET1 ;
    RECT 42.340 0.000 42.750 0.180 ;
    LAYER MET2 ;
    RECT 42.340 0.000 42.750 0.180 ;
    LAYER MET3 ;
    RECT 42.340 0.000 42.750 0.180 ;
  END
  ANTENNADIFFAREA                0.38930         LAYER MET1 ;
  ANTENNADIFFAREA                0.38930         LAYER MET2 ;
  ANTENNADIFFAREA                0.38930         LAYER MET3 ;
  ANTENNAGATEAREA                0.06300         LAYER MET1 ;
  ANTENNAGATEAREA                0.06300         LAYER MET2 ;
  ANTENNAGATEAREA                0.06300         LAYER MET3 ;
  ANTENNAPARTIALMETALAREA        0.09890         LAYER MET1 ;
  ANTENNAPARTIALMETALAREA        0.10380         LAYER MET2 ;
  ANTENNAMAXAREACAR              0.72381         LAYER MET1 ;
  ANTENNAMAXAREACAR              3.54286         LAYER MET2 ;
  ANTENNAMAXAREACAR              4.71429         LAYER MET3 ;
END D[9]
PIN Q[9]
  DIRECTION OUTPUT ;
  PORT
    LAYER MET1 ;
    RECT 40.800 0.000 41.210 0.180 ;
    LAYER MET2 ;
    RECT 40.800 0.000 41.210 0.180 ;
    LAYER MET3 ;
    RECT 40.800 0.000 41.210 0.180 ;
  END
  ANTENNADIFFAREA                0.60000         LAYER MET1 ;
  ANTENNADIFFAREA                0.60000         LAYER MET2 ;
  ANTENNADIFFAREA                0.60000         LAYER MET3 ;
  ANTENNAPARTIALMETALAREA        0.94400         LAYER MET1 ;
  ANTENNAPARTIALMETALAREA        1.33320         LAYER MET2 ;
END Q[9]
PIN WEB[9]
  DIRECTION INPUT ;
  PORT
    LAYER MET1 ;
    RECT 39.990 0.000 40.400 0.180 ;
    LAYER MET2 ;
    RECT 39.990 0.000 40.400 0.180 ;
    LAYER MET3 ;
    RECT 39.990 0.000 40.400 0.180 ;
  END
  ANTENNADIFFAREA                0.45930         LAYER MET1 ;
  ANTENNADIFFAREA                0.45930         LAYER MET2 ;
  ANTENNADIFFAREA                0.45930         LAYER MET3 ;
  ANTENNAGATEAREA                0.08100         LAYER MET1 ;
  ANTENNAGATEAREA                0.08100         LAYER MET2 ;
  ANTENNAGATEAREA                0.08100         LAYER MET3 ;
  ANTENNAPARTIALMETALAREA        0.14210         LAYER MET1 ;
  ANTENNAPARTIALMETALAREA        0.09360         LAYER MET2 ;
  ANTENNAMAXAREACAR              1.09630         LAYER MET1 ;
  ANTENNAMAXAREACAR              3.16296         LAYER MET2 ;
  ANTENNAMAXAREACAR              4.07407         LAYER MET3 ;
END WEB[9]
PIN D[10]
  DIRECTION INPUT ;
  PORT
    LAYER MET1 ;
    RECT 46.540 0.000 46.950 0.180 ;
    LAYER MET2 ;
    RECT 46.540 0.000 46.950 0.180 ;
    LAYER MET3 ;
    RECT 46.540 0.000 46.950 0.180 ;
  END
  ANTENNADIFFAREA                0.38930         LAYER MET1 ;
  ANTENNADIFFAREA                0.38930         LAYER MET2 ;
  ANTENNADIFFAREA                0.38930         LAYER MET3 ;
  ANTENNAGATEAREA                0.06300         LAYER MET1 ;
  ANTENNAGATEAREA                0.06300         LAYER MET2 ;
  ANTENNAGATEAREA                0.06300         LAYER MET3 ;
  ANTENNAPARTIALMETALAREA        0.09890         LAYER MET1 ;
  ANTENNAPARTIALMETALAREA        0.10380         LAYER MET2 ;
  ANTENNAMAXAREACAR              0.72381         LAYER MET1 ;
  ANTENNAMAXAREACAR              3.54286         LAYER MET2 ;
  ANTENNAMAXAREACAR              4.71429         LAYER MET3 ;
END D[10]
PIN Q[10]
  DIRECTION OUTPUT ;
  PORT
    LAYER MET1 ;
    RECT 45.000 0.000 45.410 0.180 ;
    LAYER MET2 ;
    RECT 45.000 0.000 45.410 0.180 ;
    LAYER MET3 ;
    RECT 45.000 0.000 45.410 0.180 ;
  END
  ANTENNADIFFAREA                0.60000         LAYER MET1 ;
  ANTENNADIFFAREA                0.60000         LAYER MET2 ;
  ANTENNADIFFAREA                0.60000         LAYER MET3 ;
  ANTENNAPARTIALMETALAREA        0.94400         LAYER MET1 ;
  ANTENNAPARTIALMETALAREA        1.33320         LAYER MET2 ;
END Q[10]
PIN WEB[10]
  DIRECTION INPUT ;
  PORT
    LAYER MET1 ;
    RECT 44.190 0.000 44.600 0.180 ;
    LAYER MET2 ;
    RECT 44.190 0.000 44.600 0.180 ;
    LAYER MET3 ;
    RECT 44.190 0.000 44.600 0.180 ;
  END
  ANTENNADIFFAREA                0.45930         LAYER MET1 ;
  ANTENNADIFFAREA                0.45930         LAYER MET2 ;
  ANTENNADIFFAREA                0.45930         LAYER MET3 ;
  ANTENNAGATEAREA                0.08100         LAYER MET1 ;
  ANTENNAGATEAREA                0.08100         LAYER MET2 ;
  ANTENNAGATEAREA                0.08100         LAYER MET3 ;
  ANTENNAPARTIALMETALAREA        0.14210         LAYER MET1 ;
  ANTENNAPARTIALMETALAREA        0.09360         LAYER MET2 ;
  ANTENNAMAXAREACAR              1.09630         LAYER MET1 ;
  ANTENNAMAXAREACAR              3.16296         LAYER MET2 ;
  ANTENNAMAXAREACAR              4.07407         LAYER MET3 ;
END WEB[10]
PIN Q[11]
  DIRECTION OUTPUT ;
  PORT
    LAYER MET1 ;
    RECT 49.200 0.000 49.610 0.180 ;
    LAYER MET2 ;
    RECT 49.200 0.000 49.610 0.180 ;
    LAYER MET3 ;
    RECT 49.200 0.000 49.610 0.180 ;
  END
  ANTENNADIFFAREA                0.60000         LAYER MET1 ;
  ANTENNADIFFAREA                0.60000         LAYER MET2 ;
  ANTENNADIFFAREA                0.60000         LAYER MET3 ;
  ANTENNAPARTIALMETALAREA        0.94400         LAYER MET1 ;
  ANTENNAPARTIALMETALAREA        1.33320         LAYER MET2 ;
END Q[11]
PIN WEB[11]
  DIRECTION INPUT ;
  PORT
    LAYER MET1 ;
    RECT 48.390 0.000 48.800 0.180 ;
    LAYER MET2 ;
    RECT 48.390 0.000 48.800 0.180 ;
    LAYER MET3 ;
    RECT 48.390 0.000 48.800 0.180 ;
  END
  ANTENNADIFFAREA                0.45930         LAYER MET1 ;
  ANTENNADIFFAREA                0.45930         LAYER MET2 ;
  ANTENNADIFFAREA                0.45930         LAYER MET3 ;
  ANTENNAGATEAREA                0.08100         LAYER MET1 ;
  ANTENNAGATEAREA                0.08100         LAYER MET2 ;
  ANTENNAGATEAREA                0.08100         LAYER MET3 ;
  ANTENNAPARTIALMETALAREA        0.14210         LAYER MET1 ;
  ANTENNAPARTIALMETALAREA        0.09360         LAYER MET2 ;
  ANTENNAMAXAREACAR              1.09630         LAYER MET1 ;
  ANTENNAMAXAREACAR              3.16296         LAYER MET2 ;
  ANTENNAMAXAREACAR              4.07407         LAYER MET3 ;
END WEB[11]
PIN D[12]
  DIRECTION INPUT ;
  PORT
    LAYER MET1 ;
    RECT 54.940 0.000 55.350 0.180 ;
    LAYER MET2 ;
    RECT 54.940 0.000 55.350 0.180 ;
    LAYER MET3 ;
    RECT 54.940 0.000 55.350 0.180 ;
  END
  ANTENNADIFFAREA                0.38930         LAYER MET1 ;
  ANTENNADIFFAREA                0.38930         LAYER MET2 ;
  ANTENNADIFFAREA                0.38930         LAYER MET3 ;
  ANTENNAGATEAREA                0.06300         LAYER MET1 ;
  ANTENNAGATEAREA                0.06300         LAYER MET2 ;
  ANTENNAGATEAREA                0.06300         LAYER MET3 ;
  ANTENNAPARTIALMETALAREA        0.09890         LAYER MET1 ;
  ANTENNAPARTIALMETALAREA        0.10380         LAYER MET2 ;
  ANTENNAMAXAREACAR              0.72381         LAYER MET1 ;
  ANTENNAMAXAREACAR              3.54286         LAYER MET2 ;
  ANTENNAMAXAREACAR              4.71429         LAYER MET3 ;
END D[12]
PIN Q[12]
  DIRECTION OUTPUT ;
  PORT
    LAYER MET1 ;
    RECT 53.400 0.000 53.810 0.180 ;
    LAYER MET2 ;
    RECT 53.400 0.000 53.810 0.180 ;
    LAYER MET3 ;
    RECT 53.400 0.000 53.810 0.180 ;
  END
  ANTENNADIFFAREA                0.60000         LAYER MET1 ;
  ANTENNADIFFAREA                0.60000         LAYER MET2 ;
  ANTENNADIFFAREA                0.60000         LAYER MET3 ;
  ANTENNAPARTIALMETALAREA        0.94400         LAYER MET1 ;
  ANTENNAPARTIALMETALAREA        1.33320         LAYER MET2 ;
END Q[12]
PIN WEB[12]
  DIRECTION INPUT ;
  PORT
    LAYER MET1 ;
    RECT 52.590 0.000 53.000 0.180 ;
    LAYER MET2 ;
    RECT 52.590 0.000 53.000 0.180 ;
    LAYER MET3 ;
    RECT 52.590 0.000 53.000 0.180 ;
  END
  ANTENNADIFFAREA                0.45930         LAYER MET1 ;
  ANTENNADIFFAREA                0.45930         LAYER MET2 ;
  ANTENNADIFFAREA                0.45930         LAYER MET3 ;
  ANTENNAGATEAREA                0.08100         LAYER MET1 ;
  ANTENNAGATEAREA                0.08100         LAYER MET2 ;
  ANTENNAGATEAREA                0.08100         LAYER MET3 ;
  ANTENNAPARTIALMETALAREA        0.14210         LAYER MET1 ;
  ANTENNAPARTIALMETALAREA        0.09360         LAYER MET2 ;
  ANTENNAMAXAREACAR              1.09630         LAYER MET1 ;
  ANTENNAMAXAREACAR              3.16296         LAYER MET2 ;
  ANTENNAMAXAREACAR              4.07407         LAYER MET3 ;
END WEB[12]
PIN D[13]
  DIRECTION INPUT ;
  PORT
    LAYER MET1 ;
    RECT 59.140 0.000 59.550 0.180 ;
    LAYER MET2 ;
    RECT 59.140 0.000 59.550 0.180 ;
    LAYER MET3 ;
    RECT 59.140 0.000 59.550 0.180 ;
  END
  ANTENNADIFFAREA                0.38930         LAYER MET1 ;
  ANTENNADIFFAREA                0.38930         LAYER MET2 ;
  ANTENNADIFFAREA                0.38930         LAYER MET3 ;
  ANTENNAGATEAREA                0.06300         LAYER MET1 ;
  ANTENNAGATEAREA                0.06300         LAYER MET2 ;
  ANTENNAGATEAREA                0.06300         LAYER MET3 ;
  ANTENNAPARTIALMETALAREA        0.09890         LAYER MET1 ;
  ANTENNAPARTIALMETALAREA        0.10380         LAYER MET2 ;
  ANTENNAMAXAREACAR              0.72381         LAYER MET1 ;
  ANTENNAMAXAREACAR              3.54286         LAYER MET2 ;
  ANTENNAMAXAREACAR              4.71429         LAYER MET3 ;
END D[13]
PIN Q[13]
  DIRECTION OUTPUT ;
  PORT
    LAYER MET1 ;
    RECT 57.600 0.000 58.010 0.180 ;
    LAYER MET2 ;
    RECT 57.600 0.000 58.010 0.180 ;
    LAYER MET3 ;
    RECT 57.600 0.000 58.010 0.180 ;
  END
  ANTENNADIFFAREA                0.60000         LAYER MET1 ;
  ANTENNADIFFAREA                0.60000         LAYER MET2 ;
  ANTENNADIFFAREA                0.60000         LAYER MET3 ;
  ANTENNAPARTIALMETALAREA        0.94400         LAYER MET1 ;
  ANTENNAPARTIALMETALAREA        1.33320         LAYER MET2 ;
END Q[13]
PIN WEB[13]
  DIRECTION INPUT ;
  PORT
    LAYER MET1 ;
    RECT 56.790 0.000 57.200 0.180 ;
    LAYER MET2 ;
    RECT 56.790 0.000 57.200 0.180 ;
    LAYER MET3 ;
    RECT 56.790 0.000 57.200 0.180 ;
  END
  ANTENNADIFFAREA                0.45930         LAYER MET1 ;
  ANTENNADIFFAREA                0.45930         LAYER MET2 ;
  ANTENNADIFFAREA                0.45930         LAYER MET3 ;
  ANTENNAGATEAREA                0.08100         LAYER MET1 ;
  ANTENNAGATEAREA                0.08100         LAYER MET2 ;
  ANTENNAGATEAREA                0.08100         LAYER MET3 ;
  ANTENNAPARTIALMETALAREA        0.14210         LAYER MET1 ;
  ANTENNAPARTIALMETALAREA        0.09360         LAYER MET2 ;
  ANTENNAMAXAREACAR              1.09630         LAYER MET1 ;
  ANTENNAMAXAREACAR              3.16296         LAYER MET2 ;
  ANTENNAMAXAREACAR              4.07407         LAYER MET3 ;
END WEB[13]
PIN D[14]
  DIRECTION INPUT ;
  PORT
    LAYER MET1 ;
    RECT 63.340 0.000 63.750 0.180 ;
    LAYER MET2 ;
    RECT 63.340 0.000 63.750 0.180 ;
    LAYER MET3 ;
    RECT 63.340 0.000 63.750 0.180 ;
  END
  ANTENNADIFFAREA                0.38930         LAYER MET1 ;
  ANTENNADIFFAREA                0.38930         LAYER MET2 ;
  ANTENNADIFFAREA                0.38930         LAYER MET3 ;
  ANTENNAGATEAREA                0.06300         LAYER MET1 ;
  ANTENNAGATEAREA                0.06300         LAYER MET2 ;
  ANTENNAGATEAREA                0.06300         LAYER MET3 ;
  ANTENNAPARTIALMETALAREA        0.09890         LAYER MET1 ;
  ANTENNAPARTIALMETALAREA        0.10380         LAYER MET2 ;
  ANTENNAMAXAREACAR              0.72381         LAYER MET1 ;
  ANTENNAMAXAREACAR              3.54286         LAYER MET2 ;
  ANTENNAMAXAREACAR              4.71429         LAYER MET3 ;
END D[14]
PIN Q[14]
  DIRECTION OUTPUT ;
  PORT
    LAYER MET1 ;
    RECT 61.800 0.000 62.210 0.180 ;
    LAYER MET2 ;
    RECT 61.800 0.000 62.210 0.180 ;
    LAYER MET3 ;
    RECT 61.800 0.000 62.210 0.180 ;
  END
  ANTENNADIFFAREA                0.60000         LAYER MET1 ;
  ANTENNADIFFAREA                0.60000         LAYER MET2 ;
  ANTENNADIFFAREA                0.60000         LAYER MET3 ;
  ANTENNAPARTIALMETALAREA        0.94400         LAYER MET1 ;
  ANTENNAPARTIALMETALAREA        1.33320         LAYER MET2 ;
END Q[14]
PIN WEB[14]
  DIRECTION INPUT ;
  PORT
    LAYER MET1 ;
    RECT 60.990 0.000 61.400 0.180 ;
    LAYER MET2 ;
    RECT 60.990 0.000 61.400 0.180 ;
    LAYER MET3 ;
    RECT 60.990 0.000 61.400 0.180 ;
  END
  ANTENNADIFFAREA                0.45930         LAYER MET1 ;
  ANTENNADIFFAREA                0.45930         LAYER MET2 ;
  ANTENNADIFFAREA                0.45930         LAYER MET3 ;
  ANTENNAGATEAREA                0.08100         LAYER MET1 ;
  ANTENNAGATEAREA                0.08100         LAYER MET2 ;
  ANTENNAGATEAREA                0.08100         LAYER MET3 ;
  ANTENNAPARTIALMETALAREA        0.14210         LAYER MET1 ;
  ANTENNAPARTIALMETALAREA        0.09360         LAYER MET2 ;
  ANTENNAMAXAREACAR              1.09630         LAYER MET1 ;
  ANTENNAMAXAREACAR              3.16296         LAYER MET2 ;
  ANTENNAMAXAREACAR              4.07407         LAYER MET3 ;
END WEB[14]
PIN D[15]
  DIRECTION INPUT ;
  PORT
    LAYER MET1 ;
    RECT 67.540 0.000 67.950 0.180 ;
    LAYER MET2 ;
    RECT 67.540 0.000 67.950 0.180 ;
    LAYER MET3 ;
    RECT 67.540 0.000 67.950 0.180 ;
  END
  ANTENNADIFFAREA                0.38930         LAYER MET1 ;
  ANTENNADIFFAREA                0.38930         LAYER MET2 ;
  ANTENNADIFFAREA                0.38930         LAYER MET3 ;
  ANTENNAGATEAREA                0.06300         LAYER MET1 ;
  ANTENNAGATEAREA                0.06300         LAYER MET2 ;
  ANTENNAGATEAREA                0.06300         LAYER MET3 ;
  ANTENNAPARTIALMETALAREA        0.09890         LAYER MET1 ;
  ANTENNAPARTIALMETALAREA        0.10380         LAYER MET2 ;
  ANTENNAMAXAREACAR              0.72381         LAYER MET1 ;
  ANTENNAMAXAREACAR              3.54286         LAYER MET2 ;
  ANTENNAMAXAREACAR              4.71429         LAYER MET3 ;
END D[15]
PIN Q[15]
  DIRECTION OUTPUT ;
  PORT
    LAYER MET1 ;
    RECT 66.000 0.000 66.410 0.180 ;
    LAYER MET2 ;
    RECT 66.000 0.000 66.410 0.180 ;
    LAYER MET3 ;
    RECT 66.000 0.000 66.410 0.180 ;
  END
  ANTENNADIFFAREA                0.60000         LAYER MET1 ;
  ANTENNADIFFAREA                0.60000         LAYER MET2 ;
  ANTENNADIFFAREA                0.60000         LAYER MET3 ;
  ANTENNAPARTIALMETALAREA        0.94400         LAYER MET1 ;
  ANTENNAPARTIALMETALAREA        1.33320         LAYER MET2 ;
END Q[15]
PIN WEB[15]
  DIRECTION INPUT ;
  PORT
    LAYER MET1 ;
    RECT 65.190 0.000 65.600 0.180 ;
    LAYER MET2 ;
    RECT 65.190 0.000 65.600 0.180 ;
    LAYER MET3 ;
    RECT 65.190 0.000 65.600 0.180 ;
  END
  ANTENNADIFFAREA                0.45930         LAYER MET1 ;
  ANTENNADIFFAREA                0.45930         LAYER MET2 ;
  ANTENNADIFFAREA                0.45930         LAYER MET3 ;
  ANTENNAGATEAREA                0.08100         LAYER MET1 ;
  ANTENNAGATEAREA                0.08100         LAYER MET2 ;
  ANTENNAGATEAREA                0.08100         LAYER MET3 ;
  ANTENNAPARTIALMETALAREA        0.14210         LAYER MET1 ;
  ANTENNAPARTIALMETALAREA        0.09360         LAYER MET2 ;
  ANTENNAMAXAREACAR              1.09630         LAYER MET1 ;
  ANTENNAMAXAREACAR              3.16296         LAYER MET2 ;
  ANTENNAMAXAREACAR              4.07407         LAYER MET3 ;
END WEB[15]
PIN D[16]
  DIRECTION INPUT ;
  PORT
    LAYER MET1 ;
    RECT 71.740 0.000 72.150 0.180 ;
    LAYER MET2 ;
    RECT 71.740 0.000 72.150 0.180 ;
    LAYER MET3 ;
    RECT 71.740 0.000 72.150 0.180 ;
  END
  ANTENNADIFFAREA                0.38930         LAYER MET1 ;
  ANTENNADIFFAREA                0.38930         LAYER MET2 ;
  ANTENNADIFFAREA                0.38930         LAYER MET3 ;
  ANTENNAGATEAREA                0.06300         LAYER MET1 ;
  ANTENNAGATEAREA                0.06300         LAYER MET2 ;
  ANTENNAGATEAREA                0.06300         LAYER MET3 ;
  ANTENNAPARTIALMETALAREA        0.09890         LAYER MET1 ;
  ANTENNAPARTIALMETALAREA        0.10380         LAYER MET2 ;
  ANTENNAMAXAREACAR              0.72381         LAYER MET1 ;
  ANTENNAMAXAREACAR              3.54286         LAYER MET2 ;
  ANTENNAMAXAREACAR              4.71429         LAYER MET3 ;
END D[16]
PIN Q[16]
  DIRECTION OUTPUT ;
  PORT
    LAYER MET1 ;
    RECT 70.200 0.000 70.610 0.180 ;
    LAYER MET2 ;
    RECT 70.200 0.000 70.610 0.180 ;
    LAYER MET3 ;
    RECT 70.200 0.000 70.610 0.180 ;
  END
  ANTENNADIFFAREA                0.60000         LAYER MET1 ;
  ANTENNADIFFAREA                0.60000         LAYER MET2 ;
  ANTENNADIFFAREA                0.60000         LAYER MET3 ;
  ANTENNAPARTIALMETALAREA        0.94400         LAYER MET1 ;
  ANTENNAPARTIALMETALAREA        1.33320         LAYER MET2 ;
END Q[16]
PIN WEB[16]
  DIRECTION INPUT ;
  PORT
    LAYER MET1 ;
    RECT 69.390 0.000 69.800 0.180 ;
    LAYER MET2 ;
    RECT 69.390 0.000 69.800 0.180 ;
    LAYER MET3 ;
    RECT 69.390 0.000 69.800 0.180 ;
  END
  ANTENNADIFFAREA                0.45930         LAYER MET1 ;
  ANTENNADIFFAREA                0.45930         LAYER MET2 ;
  ANTENNADIFFAREA                0.45930         LAYER MET3 ;
  ANTENNAGATEAREA                0.08100         LAYER MET1 ;
  ANTENNAGATEAREA                0.08100         LAYER MET2 ;
  ANTENNAGATEAREA                0.08100         LAYER MET3 ;
  ANTENNAPARTIALMETALAREA        0.14210         LAYER MET1 ;
  ANTENNAPARTIALMETALAREA        0.09360         LAYER MET2 ;
  ANTENNAMAXAREACAR              1.09630         LAYER MET1 ;
  ANTENNAMAXAREACAR              3.16296         LAYER MET2 ;
  ANTENNAMAXAREACAR              4.07407         LAYER MET3 ;
END WEB[16]
PIN D[17]
  DIRECTION INPUT ;
  PORT
    LAYER MET1 ;
    RECT 75.940 0.000 76.350 0.180 ;
    LAYER MET2 ;
    RECT 75.940 0.000 76.350 0.180 ;
    LAYER MET3 ;
    RECT 75.940 0.000 76.350 0.180 ;
  END
  ANTENNADIFFAREA                0.38930         LAYER MET1 ;
  ANTENNADIFFAREA                0.38930         LAYER MET2 ;
  ANTENNADIFFAREA                0.38930         LAYER MET3 ;
  ANTENNAGATEAREA                0.06300         LAYER MET1 ;
  ANTENNAGATEAREA                0.06300         LAYER MET2 ;
  ANTENNAGATEAREA                0.06300         LAYER MET3 ;
  ANTENNAPARTIALMETALAREA        0.09890         LAYER MET1 ;
  ANTENNAPARTIALMETALAREA        0.10380         LAYER MET2 ;
  ANTENNAMAXAREACAR              0.72381         LAYER MET1 ;
  ANTENNAMAXAREACAR              3.54286         LAYER MET2 ;
  ANTENNAMAXAREACAR              4.71429         LAYER MET3 ;
END D[17]
PIN Q[17]
  DIRECTION OUTPUT ;
  PORT
    LAYER MET1 ;
    RECT 74.400 0.000 74.810 0.180 ;
    LAYER MET2 ;
    RECT 74.400 0.000 74.810 0.180 ;
    LAYER MET3 ;
    RECT 74.400 0.000 74.810 0.180 ;
  END
  ANTENNADIFFAREA                0.60000         LAYER MET1 ;
  ANTENNADIFFAREA                0.60000         LAYER MET2 ;
  ANTENNADIFFAREA                0.60000         LAYER MET3 ;
  ANTENNAPARTIALMETALAREA        0.94400         LAYER MET1 ;
  ANTENNAPARTIALMETALAREA        1.33320         LAYER MET2 ;
END Q[17]
PIN WEB[17]
  DIRECTION INPUT ;
  PORT
    LAYER MET1 ;
    RECT 73.590 0.000 74.000 0.180 ;
    LAYER MET2 ;
    RECT 73.590 0.000 74.000 0.180 ;
    LAYER MET3 ;
    RECT 73.590 0.000 74.000 0.180 ;
  END
  ANTENNADIFFAREA                0.45930         LAYER MET1 ;
  ANTENNADIFFAREA                0.45930         LAYER MET2 ;
  ANTENNADIFFAREA                0.45930         LAYER MET3 ;
  ANTENNAGATEAREA                0.08100         LAYER MET1 ;
  ANTENNAGATEAREA                0.08100         LAYER MET2 ;
  ANTENNAGATEAREA                0.08100         LAYER MET3 ;
  ANTENNAPARTIALMETALAREA        0.14210         LAYER MET1 ;
  ANTENNAPARTIALMETALAREA        0.09360         LAYER MET2 ;
  ANTENNAMAXAREACAR              1.09630         LAYER MET1 ;
  ANTENNAMAXAREACAR              3.16296         LAYER MET2 ;
  ANTENNAMAXAREACAR              4.07407         LAYER MET3 ;
END WEB[17]
PIN D[18]
  DIRECTION INPUT ;
  PORT
    LAYER MET1 ;
    RECT 80.140 0.000 80.550 0.180 ;
    LAYER MET2 ;
    RECT 80.140 0.000 80.550 0.180 ;
    LAYER MET3 ;
    RECT 80.140 0.000 80.550 0.180 ;
  END
  ANTENNADIFFAREA                0.38930         LAYER MET1 ;
  ANTENNADIFFAREA                0.38930         LAYER MET2 ;
  ANTENNADIFFAREA                0.38930         LAYER MET3 ;
  ANTENNAGATEAREA                0.06300         LAYER MET1 ;
  ANTENNAGATEAREA                0.06300         LAYER MET2 ;
  ANTENNAGATEAREA                0.06300         LAYER MET3 ;
  ANTENNAPARTIALMETALAREA        0.09890         LAYER MET1 ;
  ANTENNAPARTIALMETALAREA        0.10380         LAYER MET2 ;
  ANTENNAMAXAREACAR              0.72381         LAYER MET1 ;
  ANTENNAMAXAREACAR              3.54286         LAYER MET2 ;
  ANTENNAMAXAREACAR              4.71429         LAYER MET3 ;
END D[18]
PIN Q[18]
  DIRECTION OUTPUT ;
  PORT
    LAYER MET1 ;
    RECT 78.600 0.000 79.010 0.180 ;
    LAYER MET2 ;
    RECT 78.600 0.000 79.010 0.180 ;
    LAYER MET3 ;
    RECT 78.600 0.000 79.010 0.180 ;
  END
  ANTENNADIFFAREA                0.60000         LAYER MET1 ;
  ANTENNADIFFAREA                0.60000         LAYER MET2 ;
  ANTENNADIFFAREA                0.60000         LAYER MET3 ;
  ANTENNAPARTIALMETALAREA        0.94400         LAYER MET1 ;
  ANTENNAPARTIALMETALAREA        1.33320         LAYER MET2 ;
END Q[18]
PIN WEB[18]
  DIRECTION INPUT ;
  PORT
    LAYER MET1 ;
    RECT 77.790 0.000 78.200 0.180 ;
    LAYER MET2 ;
    RECT 77.790 0.000 78.200 0.180 ;
    LAYER MET3 ;
    RECT 77.790 0.000 78.200 0.180 ;
  END
  ANTENNADIFFAREA                0.45930         LAYER MET1 ;
  ANTENNADIFFAREA                0.45930         LAYER MET2 ;
  ANTENNADIFFAREA                0.45930         LAYER MET3 ;
  ANTENNAGATEAREA                0.08100         LAYER MET1 ;
  ANTENNAGATEAREA                0.08100         LAYER MET2 ;
  ANTENNAGATEAREA                0.08100         LAYER MET3 ;
  ANTENNAPARTIALMETALAREA        0.14210         LAYER MET1 ;
  ANTENNAPARTIALMETALAREA        0.09360         LAYER MET2 ;
  ANTENNAMAXAREACAR              1.09630         LAYER MET1 ;
  ANTENNAMAXAREACAR              3.16296         LAYER MET2 ;
  ANTENNAMAXAREACAR              4.07407         LAYER MET3 ;
END WEB[18]
PIN D[19]
  DIRECTION INPUT ;
  PORT
    LAYER MET1 ;
    RECT 84.340 0.000 84.750 0.180 ;
    LAYER MET2 ;
    RECT 84.340 0.000 84.750 0.180 ;
    LAYER MET3 ;
    RECT 84.340 0.000 84.750 0.180 ;
  END
  ANTENNADIFFAREA                0.38930         LAYER MET1 ;
  ANTENNADIFFAREA                0.38930         LAYER MET2 ;
  ANTENNADIFFAREA                0.38930         LAYER MET3 ;
  ANTENNAGATEAREA                0.06300         LAYER MET1 ;
  ANTENNAGATEAREA                0.06300         LAYER MET2 ;
  ANTENNAGATEAREA                0.06300         LAYER MET3 ;
  ANTENNAPARTIALMETALAREA        0.09890         LAYER MET1 ;
  ANTENNAPARTIALMETALAREA        0.10380         LAYER MET2 ;
  ANTENNAMAXAREACAR              0.72381         LAYER MET1 ;
  ANTENNAMAXAREACAR              3.54286         LAYER MET2 ;
  ANTENNAMAXAREACAR              4.71429         LAYER MET3 ;
END D[19]
PIN Q[19]
  DIRECTION OUTPUT ;
  PORT
    LAYER MET1 ;
    RECT 82.800 0.000 83.210 0.180 ;
    LAYER MET2 ;
    RECT 82.800 0.000 83.210 0.180 ;
    LAYER MET3 ;
    RECT 82.800 0.000 83.210 0.180 ;
  END
  ANTENNADIFFAREA                0.60000         LAYER MET1 ;
  ANTENNADIFFAREA                0.60000         LAYER MET2 ;
  ANTENNADIFFAREA                0.60000         LAYER MET3 ;
  ANTENNAPARTIALMETALAREA        0.94400         LAYER MET1 ;
  ANTENNAPARTIALMETALAREA        1.33320         LAYER MET2 ;
END Q[19]
PIN WEB[19]
  DIRECTION INPUT ;
  PORT
    LAYER MET1 ;
    RECT 81.990 0.000 82.400 0.180 ;
    LAYER MET2 ;
    RECT 81.990 0.000 82.400 0.180 ;
    LAYER MET3 ;
    RECT 81.990 0.000 82.400 0.180 ;
  END
  ANTENNADIFFAREA                0.45930         LAYER MET1 ;
  ANTENNADIFFAREA                0.45930         LAYER MET2 ;
  ANTENNADIFFAREA                0.45930         LAYER MET3 ;
  ANTENNAGATEAREA                0.08100         LAYER MET1 ;
  ANTENNAGATEAREA                0.08100         LAYER MET2 ;
  ANTENNAGATEAREA                0.08100         LAYER MET3 ;
  ANTENNAPARTIALMETALAREA        0.14210         LAYER MET1 ;
  ANTENNAPARTIALMETALAREA        0.09360         LAYER MET2 ;
  ANTENNAMAXAREACAR              1.09630         LAYER MET1 ;
  ANTENNAMAXAREACAR              3.16296         LAYER MET2 ;
  ANTENNAMAXAREACAR              4.07407         LAYER MET3 ;
END WEB[19]
PIN D[20]
  DIRECTION INPUT ;
  PORT
    LAYER MET1 ;
    RECT 88.540 0.000 88.950 0.180 ;
    LAYER MET2 ;
    RECT 88.540 0.000 88.950 0.180 ;
    LAYER MET3 ;
    RECT 88.540 0.000 88.950 0.180 ;
  END
  ANTENNADIFFAREA                0.38930         LAYER MET1 ;
  ANTENNADIFFAREA                0.38930         LAYER MET2 ;
  ANTENNADIFFAREA                0.38930         LAYER MET3 ;
  ANTENNAGATEAREA                0.06300         LAYER MET1 ;
  ANTENNAGATEAREA                0.06300         LAYER MET2 ;
  ANTENNAGATEAREA                0.06300         LAYER MET3 ;
  ANTENNAPARTIALMETALAREA        0.09890         LAYER MET1 ;
  ANTENNAPARTIALMETALAREA        0.10380         LAYER MET2 ;
  ANTENNAMAXAREACAR              0.72381         LAYER MET1 ;
  ANTENNAMAXAREACAR              3.54286         LAYER MET2 ;
  ANTENNAMAXAREACAR              4.71429         LAYER MET3 ;
END D[20]
PIN Q[20]
  DIRECTION OUTPUT ;
  PORT
    LAYER MET1 ;
    RECT 87.000 0.000 87.410 0.180 ;
    LAYER MET2 ;
    RECT 87.000 0.000 87.410 0.180 ;
    LAYER MET3 ;
    RECT 87.000 0.000 87.410 0.180 ;
  END
  ANTENNADIFFAREA                0.60000         LAYER MET1 ;
  ANTENNADIFFAREA                0.60000         LAYER MET2 ;
  ANTENNADIFFAREA                0.60000         LAYER MET3 ;
  ANTENNAPARTIALMETALAREA        0.94400         LAYER MET1 ;
  ANTENNAPARTIALMETALAREA        1.33320         LAYER MET2 ;
END Q[20]
PIN WEB[20]
  DIRECTION INPUT ;
  PORT
    LAYER MET1 ;
    RECT 86.190 0.000 86.600 0.180 ;
    LAYER MET2 ;
    RECT 86.190 0.000 86.600 0.180 ;
    LAYER MET3 ;
    RECT 86.190 0.000 86.600 0.180 ;
  END
  ANTENNADIFFAREA                0.45930         LAYER MET1 ;
  ANTENNADIFFAREA                0.45930         LAYER MET2 ;
  ANTENNADIFFAREA                0.45930         LAYER MET3 ;
  ANTENNAGATEAREA                0.08100         LAYER MET1 ;
  ANTENNAGATEAREA                0.08100         LAYER MET2 ;
  ANTENNAGATEAREA                0.08100         LAYER MET3 ;
  ANTENNAPARTIALMETALAREA        0.14210         LAYER MET1 ;
  ANTENNAPARTIALMETALAREA        0.09360         LAYER MET2 ;
  ANTENNAMAXAREACAR              1.09630         LAYER MET1 ;
  ANTENNAMAXAREACAR              3.16296         LAYER MET2 ;
  ANTENNAMAXAREACAR              4.07407         LAYER MET3 ;
END WEB[20]
PIN D[21]
  DIRECTION INPUT ;
  PORT
    LAYER MET1 ;
    RECT 92.740 0.000 93.150 0.180 ;
    LAYER MET2 ;
    RECT 92.740 0.000 93.150 0.180 ;
    LAYER MET3 ;
    RECT 92.740 0.000 93.150 0.180 ;
  END
  ANTENNADIFFAREA                0.38930         LAYER MET1 ;
  ANTENNADIFFAREA                0.38930         LAYER MET2 ;
  ANTENNADIFFAREA                0.38930         LAYER MET3 ;
  ANTENNAGATEAREA                0.06300         LAYER MET1 ;
  ANTENNAGATEAREA                0.06300         LAYER MET2 ;
  ANTENNAGATEAREA                0.06300         LAYER MET3 ;
  ANTENNAPARTIALMETALAREA        0.09890         LAYER MET1 ;
  ANTENNAPARTIALMETALAREA        0.10380         LAYER MET2 ;
  ANTENNAMAXAREACAR              0.72381         LAYER MET1 ;
  ANTENNAMAXAREACAR              3.54286         LAYER MET2 ;
  ANTENNAMAXAREACAR              4.71429         LAYER MET3 ;
END D[21]
PIN Q[21]
  DIRECTION OUTPUT ;
  PORT
    LAYER MET1 ;
    RECT 91.200 0.000 91.610 0.180 ;
    LAYER MET2 ;
    RECT 91.200 0.000 91.610 0.180 ;
    LAYER MET3 ;
    RECT 91.200 0.000 91.610 0.180 ;
  END
  ANTENNADIFFAREA                0.60000         LAYER MET1 ;
  ANTENNADIFFAREA                0.60000         LAYER MET2 ;
  ANTENNADIFFAREA                0.60000         LAYER MET3 ;
  ANTENNAPARTIALMETALAREA        0.94400         LAYER MET1 ;
  ANTENNAPARTIALMETALAREA        1.33320         LAYER MET2 ;
END Q[21]
PIN WEB[21]
  DIRECTION INPUT ;
  PORT
    LAYER MET1 ;
    RECT 90.390 0.000 90.800 0.180 ;
    LAYER MET2 ;
    RECT 90.390 0.000 90.800 0.180 ;
    LAYER MET3 ;
    RECT 90.390 0.000 90.800 0.180 ;
  END
  ANTENNADIFFAREA                0.45930         LAYER MET1 ;
  ANTENNADIFFAREA                0.45930         LAYER MET2 ;
  ANTENNADIFFAREA                0.45930         LAYER MET3 ;
  ANTENNAGATEAREA                0.08100         LAYER MET1 ;
  ANTENNAGATEAREA                0.08100         LAYER MET2 ;
  ANTENNAGATEAREA                0.08100         LAYER MET3 ;
  ANTENNAPARTIALMETALAREA        0.14210         LAYER MET1 ;
  ANTENNAPARTIALMETALAREA        0.09360         LAYER MET2 ;
  ANTENNAMAXAREACAR              1.09630         LAYER MET1 ;
  ANTENNAMAXAREACAR              3.16296         LAYER MET2 ;
  ANTENNAMAXAREACAR              4.07407         LAYER MET3 ;
END WEB[21]
PIN D[38]
  DIRECTION INPUT ;
  PORT
    LAYER MET1 ;
    RECT 191.490 0.000 191.900 0.180 ;
    LAYER MET2 ;
    RECT 191.490 0.000 191.900 0.180 ;
    LAYER MET3 ;
    RECT 191.490 0.000 191.900 0.180 ;
  END
  ANTENNADIFFAREA                0.38930         LAYER MET1 ;
  ANTENNADIFFAREA                0.38930         LAYER MET2 ;
  ANTENNADIFFAREA                0.38930         LAYER MET3 ;
  ANTENNAGATEAREA                0.06300         LAYER MET1 ;
  ANTENNAGATEAREA                0.06300         LAYER MET2 ;
  ANTENNAGATEAREA                0.06300         LAYER MET3 ;
  ANTENNAPARTIALMETALAREA        0.09890         LAYER MET1 ;
  ANTENNAPARTIALMETALAREA        0.10380         LAYER MET2 ;
  ANTENNAMAXAREACAR              0.72381         LAYER MET1 ;
  ANTENNAMAXAREACAR              3.54286         LAYER MET2 ;
  ANTENNAMAXAREACAR              4.71429         LAYER MET3 ;
END D[38]
PIN Q[38]
  DIRECTION OUTPUT ;
  PORT
    LAYER MET1 ;
    RECT 189.950 0.000 190.360 0.180 ;
    LAYER MET2 ;
    RECT 189.950 0.000 190.360 0.180 ;
    LAYER MET3 ;
    RECT 189.950 0.000 190.360 0.180 ;
  END
  ANTENNADIFFAREA                0.60000         LAYER MET1 ;
  ANTENNADIFFAREA                0.60000         LAYER MET2 ;
  ANTENNADIFFAREA                0.60000         LAYER MET3 ;
  ANTENNAPARTIALMETALAREA        0.94400         LAYER MET1 ;
  ANTENNAPARTIALMETALAREA        1.33320         LAYER MET2 ;
END Q[38]
PIN D[22]
  DIRECTION INPUT ;
  PORT
    LAYER MET1 ;
    RECT 96.940 0.000 97.350 0.180 ;
    LAYER MET2 ;
    RECT 96.940 0.000 97.350 0.180 ;
    LAYER MET3 ;
    RECT 96.940 0.000 97.350 0.180 ;
  END
  ANTENNADIFFAREA                0.38930         LAYER MET1 ;
  ANTENNADIFFAREA                0.38930         LAYER MET2 ;
  ANTENNADIFFAREA                0.38930         LAYER MET3 ;
  ANTENNAGATEAREA                0.06300         LAYER MET1 ;
  ANTENNAGATEAREA                0.06300         LAYER MET2 ;
  ANTENNAGATEAREA                0.06300         LAYER MET3 ;
  ANTENNAPARTIALMETALAREA        0.09890         LAYER MET1 ;
  ANTENNAPARTIALMETALAREA        0.10380         LAYER MET2 ;
  ANTENNAMAXAREACAR              0.72381         LAYER MET1 ;
  ANTENNAMAXAREACAR              3.54286         LAYER MET2 ;
  ANTENNAMAXAREACAR              4.71429         LAYER MET3 ;
END D[22]
PIN Q[22]
  DIRECTION OUTPUT ;
  PORT
    LAYER MET1 ;
    RECT 95.400 0.000 95.810 0.180 ;
    LAYER MET2 ;
    RECT 95.400 0.000 95.810 0.180 ;
    LAYER MET3 ;
    RECT 95.400 0.000 95.810 0.180 ;
  END
  ANTENNADIFFAREA                0.60000         LAYER MET1 ;
  ANTENNADIFFAREA                0.60000         LAYER MET2 ;
  ANTENNADIFFAREA                0.60000         LAYER MET3 ;
  ANTENNAPARTIALMETALAREA        0.94400         LAYER MET1 ;
  ANTENNAPARTIALMETALAREA        1.33320         LAYER MET2 ;
END Q[22]
PIN WEB[22]
  DIRECTION INPUT ;
  PORT
    LAYER MET1 ;
    RECT 94.590 0.000 95.000 0.180 ;
    LAYER MET2 ;
    RECT 94.590 0.000 95.000 0.180 ;
    LAYER MET3 ;
    RECT 94.590 0.000 95.000 0.180 ;
  END
  ANTENNADIFFAREA                0.45930         LAYER MET1 ;
  ANTENNADIFFAREA                0.45930         LAYER MET2 ;
  ANTENNADIFFAREA                0.45930         LAYER MET3 ;
  ANTENNAGATEAREA                0.08100         LAYER MET1 ;
  ANTENNAGATEAREA                0.08100         LAYER MET2 ;
  ANTENNAGATEAREA                0.08100         LAYER MET3 ;
  ANTENNAPARTIALMETALAREA        0.14210         LAYER MET1 ;
  ANTENNAPARTIALMETALAREA        0.09360         LAYER MET2 ;
  ANTENNAMAXAREACAR              1.09630         LAYER MET1 ;
  ANTENNAMAXAREACAR              3.16296         LAYER MET2 ;
  ANTENNAMAXAREACAR              4.07407         LAYER MET3 ;
END WEB[22]
PIN D[23]
  DIRECTION INPUT ;
  PORT
    LAYER MET1 ;
    RECT 101.140 0.000 101.550 0.180 ;
    LAYER MET2 ;
    RECT 101.140 0.000 101.550 0.180 ;
    LAYER MET3 ;
    RECT 101.140 0.000 101.550 0.180 ;
  END
  ANTENNADIFFAREA                0.38930         LAYER MET1 ;
  ANTENNADIFFAREA                0.38930         LAYER MET2 ;
  ANTENNADIFFAREA                0.38930         LAYER MET3 ;
  ANTENNAGATEAREA                0.06300         LAYER MET1 ;
  ANTENNAGATEAREA                0.06300         LAYER MET2 ;
  ANTENNAGATEAREA                0.06300         LAYER MET3 ;
  ANTENNAPARTIALMETALAREA        0.09890         LAYER MET1 ;
  ANTENNAPARTIALMETALAREA        0.10380         LAYER MET2 ;
  ANTENNAMAXAREACAR              0.72381         LAYER MET1 ;
  ANTENNAMAXAREACAR              3.54286         LAYER MET2 ;
  ANTENNAMAXAREACAR              4.71429         LAYER MET3 ;
END D[23]
PIN Q[23]
  DIRECTION OUTPUT ;
  PORT
    LAYER MET1 ;
    RECT 99.600 0.000 100.010 0.180 ;
    LAYER MET2 ;
    RECT 99.600 0.000 100.010 0.180 ;
    LAYER MET3 ;
    RECT 99.600 0.000 100.010 0.180 ;
  END
  ANTENNADIFFAREA                0.60000         LAYER MET1 ;
  ANTENNADIFFAREA                0.60000         LAYER MET2 ;
  ANTENNADIFFAREA                0.60000         LAYER MET3 ;
  ANTENNAPARTIALMETALAREA        0.94400         LAYER MET1 ;
  ANTENNAPARTIALMETALAREA        1.33320         LAYER MET2 ;
END Q[23]
PIN WEB[23]
  DIRECTION INPUT ;
  PORT
    LAYER MET1 ;
    RECT 98.790 0.000 99.200 0.180 ;
    LAYER MET2 ;
    RECT 98.790 0.000 99.200 0.180 ;
    LAYER MET3 ;
    RECT 98.790 0.000 99.200 0.180 ;
  END
  ANTENNADIFFAREA                0.45930         LAYER MET1 ;
  ANTENNADIFFAREA                0.45930         LAYER MET2 ;
  ANTENNADIFFAREA                0.45930         LAYER MET3 ;
  ANTENNAGATEAREA                0.08100         LAYER MET1 ;
  ANTENNAGATEAREA                0.08100         LAYER MET2 ;
  ANTENNAGATEAREA                0.08100         LAYER MET3 ;
  ANTENNAPARTIALMETALAREA        0.14210         LAYER MET1 ;
  ANTENNAPARTIALMETALAREA        0.09360         LAYER MET2 ;
  ANTENNAMAXAREACAR              1.09630         LAYER MET1 ;
  ANTENNAMAXAREACAR              3.16296         LAYER MET2 ;
  ANTENNAMAXAREACAR              4.07407         LAYER MET3 ;
END WEB[23]
PIN D[24]
  DIRECTION INPUT ;
  PORT
    LAYER MET1 ;
    RECT 105.340 0.000 105.750 0.180 ;
    LAYER MET2 ;
    RECT 105.340 0.000 105.750 0.180 ;
    LAYER MET3 ;
    RECT 105.340 0.000 105.750 0.180 ;
  END
  ANTENNADIFFAREA                0.38930         LAYER MET1 ;
  ANTENNADIFFAREA                0.38930         LAYER MET2 ;
  ANTENNADIFFAREA                0.38930         LAYER MET3 ;
  ANTENNAGATEAREA                0.06300         LAYER MET1 ;
  ANTENNAGATEAREA                0.06300         LAYER MET2 ;
  ANTENNAGATEAREA                0.06300         LAYER MET3 ;
  ANTENNAPARTIALMETALAREA        0.09890         LAYER MET1 ;
  ANTENNAPARTIALMETALAREA        0.10380         LAYER MET2 ;
  ANTENNAMAXAREACAR              0.72381         LAYER MET1 ;
  ANTENNAMAXAREACAR              3.54286         LAYER MET2 ;
  ANTENNAMAXAREACAR              4.71429         LAYER MET3 ;
END D[24]
PIN Q[24]
  DIRECTION OUTPUT ;
  PORT
    LAYER MET1 ;
    RECT 103.800 0.000 104.210 0.180 ;
    LAYER MET2 ;
    RECT 103.800 0.000 104.210 0.180 ;
    LAYER MET3 ;
    RECT 103.800 0.000 104.210 0.180 ;
  END
  ANTENNADIFFAREA                0.60000         LAYER MET1 ;
  ANTENNADIFFAREA                0.60000         LAYER MET2 ;
  ANTENNADIFFAREA                0.60000         LAYER MET3 ;
  ANTENNAPARTIALMETALAREA        0.94400         LAYER MET1 ;
  ANTENNAPARTIALMETALAREA        1.33320         LAYER MET2 ;
END Q[24]
PIN WEB[24]
  DIRECTION INPUT ;
  PORT
    LAYER MET1 ;
    RECT 102.990 0.000 103.400 0.180 ;
    LAYER MET2 ;
    RECT 102.990 0.000 103.400 0.180 ;
    LAYER MET3 ;
    RECT 102.990 0.000 103.400 0.180 ;
  END
  ANTENNADIFFAREA                0.45930         LAYER MET1 ;
  ANTENNADIFFAREA                0.45930         LAYER MET2 ;
  ANTENNADIFFAREA                0.45930         LAYER MET3 ;
  ANTENNAGATEAREA                0.08100         LAYER MET1 ;
  ANTENNAGATEAREA                0.08100         LAYER MET2 ;
  ANTENNAGATEAREA                0.08100         LAYER MET3 ;
  ANTENNAPARTIALMETALAREA        0.14210         LAYER MET1 ;
  ANTENNAPARTIALMETALAREA        0.09360         LAYER MET2 ;
  ANTENNAMAXAREACAR              1.09630         LAYER MET1 ;
  ANTENNAMAXAREACAR              3.16296         LAYER MET2 ;
  ANTENNAMAXAREACAR              4.07407         LAYER MET3 ;
END WEB[24]
PIN D[25]
  DIRECTION INPUT ;
  PORT
    LAYER MET1 ;
    RECT 109.540 0.000 109.950 0.180 ;
    LAYER MET2 ;
    RECT 109.540 0.000 109.950 0.180 ;
    LAYER MET3 ;
    RECT 109.540 0.000 109.950 0.180 ;
  END
  ANTENNADIFFAREA                0.38930         LAYER MET1 ;
  ANTENNADIFFAREA                0.38930         LAYER MET2 ;
  ANTENNADIFFAREA                0.38930         LAYER MET3 ;
  ANTENNAGATEAREA                0.06300         LAYER MET1 ;
  ANTENNAGATEAREA                0.06300         LAYER MET2 ;
  ANTENNAGATEAREA                0.06300         LAYER MET3 ;
  ANTENNAPARTIALMETALAREA        0.09890         LAYER MET1 ;
  ANTENNAPARTIALMETALAREA        0.10380         LAYER MET2 ;
  ANTENNAMAXAREACAR              0.72381         LAYER MET1 ;
  ANTENNAMAXAREACAR              3.54286         LAYER MET2 ;
  ANTENNAMAXAREACAR              4.71429         LAYER MET3 ;
END D[25]
PIN Q[25]
  DIRECTION OUTPUT ;
  PORT
    LAYER MET1 ;
    RECT 108.000 0.000 108.410 0.180 ;
    LAYER MET2 ;
    RECT 108.000 0.000 108.410 0.180 ;
    LAYER MET3 ;
    RECT 108.000 0.000 108.410 0.180 ;
  END
  ANTENNADIFFAREA                0.60000         LAYER MET1 ;
  ANTENNADIFFAREA                0.60000         LAYER MET2 ;
  ANTENNADIFFAREA                0.60000         LAYER MET3 ;
  ANTENNAPARTIALMETALAREA        0.94400         LAYER MET1 ;
  ANTENNAPARTIALMETALAREA        1.33320         LAYER MET2 ;
END Q[25]
PIN WEB[25]
  DIRECTION INPUT ;
  PORT
    LAYER MET1 ;
    RECT 107.190 0.000 107.600 0.180 ;
    LAYER MET2 ;
    RECT 107.190 0.000 107.600 0.180 ;
    LAYER MET3 ;
    RECT 107.190 0.000 107.600 0.180 ;
  END
  ANTENNADIFFAREA                0.45930         LAYER MET1 ;
  ANTENNADIFFAREA                0.45930         LAYER MET2 ;
  ANTENNADIFFAREA                0.45930         LAYER MET3 ;
  ANTENNAGATEAREA                0.08100         LAYER MET1 ;
  ANTENNAGATEAREA                0.08100         LAYER MET2 ;
  ANTENNAGATEAREA                0.08100         LAYER MET3 ;
  ANTENNAPARTIALMETALAREA        0.14210         LAYER MET1 ;
  ANTENNAPARTIALMETALAREA        0.09360         LAYER MET2 ;
  ANTENNAMAXAREACAR              1.09630         LAYER MET1 ;
  ANTENNAMAXAREACAR              3.16296         LAYER MET2 ;
  ANTENNAMAXAREACAR              4.07407         LAYER MET3 ;
END WEB[25]
PIN D[26]
  DIRECTION INPUT ;
  PORT
    LAYER MET1 ;
    RECT 113.740 0.000 114.150 0.180 ;
    LAYER MET2 ;
    RECT 113.740 0.000 114.150 0.180 ;
    LAYER MET3 ;
    RECT 113.740 0.000 114.150 0.180 ;
  END
  ANTENNADIFFAREA                0.38930         LAYER MET1 ;
  ANTENNADIFFAREA                0.38930         LAYER MET2 ;
  ANTENNADIFFAREA                0.38930         LAYER MET3 ;
  ANTENNAGATEAREA                0.06300         LAYER MET1 ;
  ANTENNAGATEAREA                0.06300         LAYER MET2 ;
  ANTENNAGATEAREA                0.06300         LAYER MET3 ;
  ANTENNAPARTIALMETALAREA        0.09890         LAYER MET1 ;
  ANTENNAPARTIALMETALAREA        0.10380         LAYER MET2 ;
  ANTENNAMAXAREACAR              0.72381         LAYER MET1 ;
  ANTENNAMAXAREACAR              3.54286         LAYER MET2 ;
  ANTENNAMAXAREACAR              4.71429         LAYER MET3 ;
END D[26]
PIN Q[26]
  DIRECTION OUTPUT ;
  PORT
    LAYER MET1 ;
    RECT 112.200 0.000 112.610 0.180 ;
    LAYER MET2 ;
    RECT 112.200 0.000 112.610 0.180 ;
    LAYER MET3 ;
    RECT 112.200 0.000 112.610 0.180 ;
  END
  ANTENNADIFFAREA                0.60000         LAYER MET1 ;
  ANTENNADIFFAREA                0.60000         LAYER MET2 ;
  ANTENNADIFFAREA                0.60000         LAYER MET3 ;
  ANTENNAPARTIALMETALAREA        0.94400         LAYER MET1 ;
  ANTENNAPARTIALMETALAREA        1.33320         LAYER MET2 ;
END Q[26]
PIN WEB[26]
  DIRECTION INPUT ;
  PORT
    LAYER MET1 ;
    RECT 111.390 0.000 111.800 0.180 ;
    LAYER MET2 ;
    RECT 111.390 0.000 111.800 0.180 ;
    LAYER MET3 ;
    RECT 111.390 0.000 111.800 0.180 ;
  END
  ANTENNADIFFAREA                0.45930         LAYER MET1 ;
  ANTENNADIFFAREA                0.45930         LAYER MET2 ;
  ANTENNADIFFAREA                0.45930         LAYER MET3 ;
  ANTENNAGATEAREA                0.08100         LAYER MET1 ;
  ANTENNAGATEAREA                0.08100         LAYER MET2 ;
  ANTENNAGATEAREA                0.08100         LAYER MET3 ;
  ANTENNAPARTIALMETALAREA        0.14210         LAYER MET1 ;
  ANTENNAPARTIALMETALAREA        0.09360         LAYER MET2 ;
  ANTENNAMAXAREACAR              1.09630         LAYER MET1 ;
  ANTENNAMAXAREACAR              3.16296         LAYER MET2 ;
  ANTENNAMAXAREACAR              4.07407         LAYER MET3 ;
END WEB[26]
PIN D[27]
  DIRECTION INPUT ;
  PORT
    LAYER MET1 ;
    RECT 117.940 0.000 118.350 0.180 ;
    LAYER MET2 ;
    RECT 117.940 0.000 118.350 0.180 ;
    LAYER MET3 ;
    RECT 117.940 0.000 118.350 0.180 ;
  END
  ANTENNADIFFAREA                0.38930         LAYER MET1 ;
  ANTENNADIFFAREA                0.38930         LAYER MET2 ;
  ANTENNADIFFAREA                0.38930         LAYER MET3 ;
  ANTENNAGATEAREA                0.06300         LAYER MET1 ;
  ANTENNAGATEAREA                0.06300         LAYER MET2 ;
  ANTENNAGATEAREA                0.06300         LAYER MET3 ;
  ANTENNAPARTIALMETALAREA        0.09890         LAYER MET1 ;
  ANTENNAPARTIALMETALAREA        0.10380         LAYER MET2 ;
  ANTENNAMAXAREACAR              0.72381         LAYER MET1 ;
  ANTENNAMAXAREACAR              3.54286         LAYER MET2 ;
  ANTENNAMAXAREACAR              4.71429         LAYER MET3 ;
END D[27]
PIN Q[27]
  DIRECTION OUTPUT ;
  PORT
    LAYER MET1 ;
    RECT 116.400 0.000 116.810 0.180 ;
    LAYER MET2 ;
    RECT 116.400 0.000 116.810 0.180 ;
    LAYER MET3 ;
    RECT 116.400 0.000 116.810 0.180 ;
  END
  ANTENNADIFFAREA                0.60000         LAYER MET1 ;
  ANTENNADIFFAREA                0.60000         LAYER MET2 ;
  ANTENNADIFFAREA                0.60000         LAYER MET3 ;
  ANTENNAPARTIALMETALAREA        0.94400         LAYER MET1 ;
  ANTENNAPARTIALMETALAREA        1.33320         LAYER MET2 ;
END Q[27]
PIN WEB[27]
  DIRECTION INPUT ;
  PORT
    LAYER MET1 ;
    RECT 115.590 0.000 116.000 0.180 ;
    LAYER MET2 ;
    RECT 115.590 0.000 116.000 0.180 ;
    LAYER MET3 ;
    RECT 115.590 0.000 116.000 0.180 ;
  END
  ANTENNADIFFAREA                0.45930         LAYER MET1 ;
  ANTENNADIFFAREA                0.45930         LAYER MET2 ;
  ANTENNADIFFAREA                0.45930         LAYER MET3 ;
  ANTENNAGATEAREA                0.08100         LAYER MET1 ;
  ANTENNAGATEAREA                0.08100         LAYER MET2 ;
  ANTENNAGATEAREA                0.08100         LAYER MET3 ;
  ANTENNAPARTIALMETALAREA        0.14210         LAYER MET1 ;
  ANTENNAPARTIALMETALAREA        0.09360         LAYER MET2 ;
  ANTENNAMAXAREACAR              1.09630         LAYER MET1 ;
  ANTENNAMAXAREACAR              3.16296         LAYER MET2 ;
  ANTENNAMAXAREACAR              4.07407         LAYER MET3 ;
END WEB[27]
PIN D[28]
  DIRECTION INPUT ;
  PORT
    LAYER MET1 ;
    RECT 122.140 0.000 122.550 0.180 ;
    LAYER MET2 ;
    RECT 122.140 0.000 122.550 0.180 ;
    LAYER MET3 ;
    RECT 122.140 0.000 122.550 0.180 ;
  END
  ANTENNADIFFAREA                0.38930         LAYER MET1 ;
  ANTENNADIFFAREA                0.38930         LAYER MET2 ;
  ANTENNADIFFAREA                0.38930         LAYER MET3 ;
  ANTENNAGATEAREA                0.06300         LAYER MET1 ;
  ANTENNAGATEAREA                0.06300         LAYER MET2 ;
  ANTENNAGATEAREA                0.06300         LAYER MET3 ;
  ANTENNAPARTIALMETALAREA        0.09890         LAYER MET1 ;
  ANTENNAPARTIALMETALAREA        0.10380         LAYER MET2 ;
  ANTENNAMAXAREACAR              0.72381         LAYER MET1 ;
  ANTENNAMAXAREACAR              3.54286         LAYER MET2 ;
  ANTENNAMAXAREACAR              4.71429         LAYER MET3 ;
END D[28]
PIN Q[28]
  DIRECTION OUTPUT ;
  PORT
    LAYER MET1 ;
    RECT 120.600 0.000 121.010 0.180 ;
    LAYER MET2 ;
    RECT 120.600 0.000 121.010 0.180 ;
    LAYER MET3 ;
    RECT 120.600 0.000 121.010 0.180 ;
  END
  ANTENNADIFFAREA                0.60000         LAYER MET1 ;
  ANTENNADIFFAREA                0.60000         LAYER MET2 ;
  ANTENNADIFFAREA                0.60000         LAYER MET3 ;
  ANTENNAPARTIALMETALAREA        0.94400         LAYER MET1 ;
  ANTENNAPARTIALMETALAREA        1.33320         LAYER MET2 ;
END Q[28]
PIN WEB[28]
  DIRECTION INPUT ;
  PORT
    LAYER MET1 ;
    RECT 119.790 0.000 120.200 0.180 ;
    LAYER MET2 ;
    RECT 119.790 0.000 120.200 0.180 ;
    LAYER MET3 ;
    RECT 119.790 0.000 120.200 0.180 ;
  END
  ANTENNADIFFAREA                0.45930         LAYER MET1 ;
  ANTENNADIFFAREA                0.45930         LAYER MET2 ;
  ANTENNADIFFAREA                0.45930         LAYER MET3 ;
  ANTENNAGATEAREA                0.08100         LAYER MET1 ;
  ANTENNAGATEAREA                0.08100         LAYER MET2 ;
  ANTENNAGATEAREA                0.08100         LAYER MET3 ;
  ANTENNAPARTIALMETALAREA        0.14210         LAYER MET1 ;
  ANTENNAPARTIALMETALAREA        0.09360         LAYER MET2 ;
  ANTENNAMAXAREACAR              1.09630         LAYER MET1 ;
  ANTENNAMAXAREACAR              3.16296         LAYER MET2 ;
  ANTENNAMAXAREACAR              4.07407         LAYER MET3 ;
END WEB[28]
PIN D[29]
  DIRECTION INPUT ;
  PORT
    LAYER MET1 ;
    RECT 126.340 0.000 126.750 0.180 ;
    LAYER MET2 ;
    RECT 126.340 0.000 126.750 0.180 ;
    LAYER MET3 ;
    RECT 126.340 0.000 126.750 0.180 ;
  END
  ANTENNADIFFAREA                0.38930         LAYER MET1 ;
  ANTENNADIFFAREA                0.38930         LAYER MET2 ;
  ANTENNADIFFAREA                0.38930         LAYER MET3 ;
  ANTENNAGATEAREA                0.06300         LAYER MET1 ;
  ANTENNAGATEAREA                0.06300         LAYER MET2 ;
  ANTENNAGATEAREA                0.06300         LAYER MET3 ;
  ANTENNAPARTIALMETALAREA        0.09890         LAYER MET1 ;
  ANTENNAPARTIALMETALAREA        0.10380         LAYER MET2 ;
  ANTENNAMAXAREACAR              0.72381         LAYER MET1 ;
  ANTENNAMAXAREACAR              3.54286         LAYER MET2 ;
  ANTENNAMAXAREACAR              4.71429         LAYER MET3 ;
END D[29]
PIN Q[29]
  DIRECTION OUTPUT ;
  PORT
    LAYER MET1 ;
    RECT 124.800 0.000 125.210 0.180 ;
    LAYER MET2 ;
    RECT 124.800 0.000 125.210 0.180 ;
    LAYER MET3 ;
    RECT 124.800 0.000 125.210 0.180 ;
  END
  ANTENNADIFFAREA                0.60000         LAYER MET1 ;
  ANTENNADIFFAREA                0.60000         LAYER MET2 ;
  ANTENNADIFFAREA                0.60000         LAYER MET3 ;
  ANTENNAPARTIALMETALAREA        0.94400         LAYER MET1 ;
  ANTENNAPARTIALMETALAREA        1.33320         LAYER MET2 ;
END Q[29]
PIN WEB[29]
  DIRECTION INPUT ;
  PORT
    LAYER MET1 ;
    RECT 123.990 0.000 124.400 0.180 ;
    LAYER MET2 ;
    RECT 123.990 0.000 124.400 0.180 ;
    LAYER MET3 ;
    RECT 123.990 0.000 124.400 0.180 ;
  END
  ANTENNADIFFAREA                0.45930         LAYER MET1 ;
  ANTENNADIFFAREA                0.45930         LAYER MET2 ;
  ANTENNADIFFAREA                0.45930         LAYER MET3 ;
  ANTENNAGATEAREA                0.08100         LAYER MET1 ;
  ANTENNAGATEAREA                0.08100         LAYER MET2 ;
  ANTENNAGATEAREA                0.08100         LAYER MET3 ;
  ANTENNAPARTIALMETALAREA        0.14210         LAYER MET1 ;
  ANTENNAPARTIALMETALAREA        0.09360         LAYER MET2 ;
  ANTENNAMAXAREACAR              1.09630         LAYER MET1 ;
  ANTENNAMAXAREACAR              3.16296         LAYER MET2 ;
  ANTENNAMAXAREACAR              4.07407         LAYER MET3 ;
END WEB[29]
PIN D[30]
  DIRECTION INPUT ;
  PORT
    LAYER MET1 ;
    RECT 130.540 0.000 130.950 0.180 ;
    LAYER MET2 ;
    RECT 130.540 0.000 130.950 0.180 ;
    LAYER MET3 ;
    RECT 130.540 0.000 130.950 0.180 ;
  END
  ANTENNADIFFAREA                0.38930         LAYER MET1 ;
  ANTENNADIFFAREA                0.38930         LAYER MET2 ;
  ANTENNADIFFAREA                0.38930         LAYER MET3 ;
  ANTENNAGATEAREA                0.06300         LAYER MET1 ;
  ANTENNAGATEAREA                0.06300         LAYER MET2 ;
  ANTENNAGATEAREA                0.06300         LAYER MET3 ;
  ANTENNAPARTIALMETALAREA        0.09890         LAYER MET1 ;
  ANTENNAPARTIALMETALAREA        0.10380         LAYER MET2 ;
  ANTENNAMAXAREACAR              0.72381         LAYER MET1 ;
  ANTENNAMAXAREACAR              3.54286         LAYER MET2 ;
  ANTENNAMAXAREACAR              4.71429         LAYER MET3 ;
END D[30]
PIN Q[30]
  DIRECTION OUTPUT ;
  PORT
    LAYER MET1 ;
    RECT 129.000 0.000 129.410 0.180 ;
    LAYER MET2 ;
    RECT 129.000 0.000 129.410 0.180 ;
    LAYER MET3 ;
    RECT 129.000 0.000 129.410 0.180 ;
  END
  ANTENNADIFFAREA                0.60000         LAYER MET1 ;
  ANTENNADIFFAREA                0.60000         LAYER MET2 ;
  ANTENNADIFFAREA                0.60000         LAYER MET3 ;
  ANTENNAPARTIALMETALAREA        0.94400         LAYER MET1 ;
  ANTENNAPARTIALMETALAREA        1.33320         LAYER MET2 ;
END Q[30]
PIN WEB[30]
  DIRECTION INPUT ;
  PORT
    LAYER MET1 ;
    RECT 128.190 0.000 128.600 0.180 ;
    LAYER MET2 ;
    RECT 128.190 0.000 128.600 0.180 ;
    LAYER MET3 ;
    RECT 128.190 0.000 128.600 0.180 ;
  END
  ANTENNADIFFAREA                0.45930         LAYER MET1 ;
  ANTENNADIFFAREA                0.45930         LAYER MET2 ;
  ANTENNADIFFAREA                0.45930         LAYER MET3 ;
  ANTENNAGATEAREA                0.08100         LAYER MET1 ;
  ANTENNAGATEAREA                0.08100         LAYER MET2 ;
  ANTENNAGATEAREA                0.08100         LAYER MET3 ;
  ANTENNAPARTIALMETALAREA        0.14210         LAYER MET1 ;
  ANTENNAPARTIALMETALAREA        0.09360         LAYER MET2 ;
  ANTENNAMAXAREACAR              1.09630         LAYER MET1 ;
  ANTENNAMAXAREACAR              3.16296         LAYER MET2 ;
  ANTENNAMAXAREACAR              4.07407         LAYER MET3 ;
END WEB[30]
PIN D[31]
  DIRECTION INPUT ;
  PORT
    LAYER MET1 ;
    RECT 134.740 0.000 135.150 0.180 ;
    LAYER MET2 ;
    RECT 134.740 0.000 135.150 0.180 ;
    LAYER MET3 ;
    RECT 134.740 0.000 135.150 0.180 ;
  END
  ANTENNADIFFAREA                0.38930         LAYER MET1 ;
  ANTENNADIFFAREA                0.38930         LAYER MET2 ;
  ANTENNADIFFAREA                0.38930         LAYER MET3 ;
  ANTENNAGATEAREA                0.06300         LAYER MET1 ;
  ANTENNAGATEAREA                0.06300         LAYER MET2 ;
  ANTENNAGATEAREA                0.06300         LAYER MET3 ;
  ANTENNAPARTIALMETALAREA        0.09890         LAYER MET1 ;
  ANTENNAPARTIALMETALAREA        0.10380         LAYER MET2 ;
  ANTENNAMAXAREACAR              0.72381         LAYER MET1 ;
  ANTENNAMAXAREACAR              3.54286         LAYER MET2 ;
  ANTENNAMAXAREACAR              4.71429         LAYER MET3 ;
END D[31]
PIN Q[31]
  DIRECTION OUTPUT ;
  PORT
    LAYER MET1 ;
    RECT 133.200 0.000 133.610 0.180 ;
    LAYER MET2 ;
    RECT 133.200 0.000 133.610 0.180 ;
    LAYER MET3 ;
    RECT 133.200 0.000 133.610 0.180 ;
  END
  ANTENNADIFFAREA                0.60000         LAYER MET1 ;
  ANTENNADIFFAREA                0.60000         LAYER MET2 ;
  ANTENNADIFFAREA                0.60000         LAYER MET3 ;
  ANTENNAPARTIALMETALAREA        0.94400         LAYER MET1 ;
  ANTENNAPARTIALMETALAREA        1.33320         LAYER MET2 ;
END Q[31]
PIN WEB[31]
  DIRECTION INPUT ;
  PORT
    LAYER MET1 ;
    RECT 132.390 0.000 132.800 0.180 ;
    LAYER MET2 ;
    RECT 132.390 0.000 132.800 0.180 ;
    LAYER MET3 ;
    RECT 132.390 0.000 132.800 0.180 ;
  END
  ANTENNADIFFAREA                0.45930         LAYER MET1 ;
  ANTENNADIFFAREA                0.45930         LAYER MET2 ;
  ANTENNADIFFAREA                0.45930         LAYER MET3 ;
  ANTENNAGATEAREA                0.08100         LAYER MET1 ;
  ANTENNAGATEAREA                0.08100         LAYER MET2 ;
  ANTENNAGATEAREA                0.08100         LAYER MET3 ;
  ANTENNAPARTIALMETALAREA        0.14210         LAYER MET1 ;
  ANTENNAPARTIALMETALAREA        0.09360         LAYER MET2 ;
  ANTENNAMAXAREACAR              1.09630         LAYER MET1 ;
  ANTENNAMAXAREACAR              3.16296         LAYER MET2 ;
  ANTENNAMAXAREACAR              4.07407         LAYER MET3 ;
END WEB[31]
PIN CLK
  DIRECTION INPUT ;
  PORT
    LAYER MET1 ;
    RECT 147.590 0.000 148.000 0.180 ;
    LAYER MET2 ;
    RECT 147.590 0.000 148.000 0.180 ;
    LAYER MET3 ;
    RECT 147.590 0.000 148.000 0.180 ;
  END
  ANTENNADIFFAREA                0.68830         LAYER MET1 ;
  ANTENNADIFFAREA                0.68830         LAYER MET2 ;
  ANTENNADIFFAREA                0.68830         LAYER MET3 ;
  ANTENNAGATEAREA                0.09000         LAYER MET1 ;
  ANTENNAGATEAREA                0.09000         LAYER MET2 ;
  ANTENNAGATEAREA                0.09000         LAYER MET3 ;
  ANTENNAPARTIALMETALAREA        0.11410         LAYER MET1 ;
  ANTENNAPARTIALMETALAREA        0.92700         LAYER MET2 ;
  ANTENNAMAXAREACAR              0.67556         LAYER MET1 ;
  ANTENNAMAXAREACAR              11.79556        LAYER MET2 ;
  ANTENNAMAXAREACAR              12.61556        LAYER MET3 ;
END CLK
PIN CEB
  DIRECTION INPUT ;
  PORT
    LAYER MET1 ;
    RECT 145.805 0.000 146.215 0.180 ;
    LAYER MET2 ;
    RECT 145.805 0.000 146.215 0.180 ;
    LAYER MET3 ;
    RECT 145.805 0.000 146.215 0.180 ;
  END
  ANTENNADIFFAREA                2.40880         LAYER MET1 ;
  ANTENNADIFFAREA                2.40880         LAYER MET2 ;
  ANTENNADIFFAREA                2.40880         LAYER MET3 ;
  ANTENNAGATEAREA                0.37800         LAYER MET1 ;
  ANTENNAGATEAREA                0.37800         LAYER MET2 ;
  ANTENNAGATEAREA                0.37800         LAYER MET3 ;
  ANTENNAPARTIALMETALAREA        0.26510         LAYER MET1 ;
  ANTENNAPARTIALMETALAREA        1.07760         LAYER MET2 ;
  ANTENNAMAXAREACAR              3.36190         LAYER MET1 ;
  ANTENNAMAXAREACAR              21.63810        LAYER MET2 ;
  ANTENNAMAXAREACAR              22.80952        LAYER MET3 ;
END CEB
PIN GWEB
  DIRECTION INPUT ;
  PORT
    LAYER MET1 ;
    RECT 145.275 0.000 145.685 0.180 ;
    LAYER MET2 ;
    RECT 145.275 0.000 145.685 0.180 ;
    LAYER MET3 ;
    RECT 145.275 0.000 145.685 0.180 ;
  END
  ANTENNADIFFAREA                0.47330         LAYER MET1 ;
  ANTENNADIFFAREA                0.47330         LAYER MET2 ;
  ANTENNADIFFAREA                0.47330         LAYER MET3 ;
  ANTENNAGATEAREA                0.06300         LAYER MET1 ;
  ANTENNAGATEAREA                0.06300         LAYER MET2 ;
  ANTENNAGATEAREA                0.06300         LAYER MET3 ;
  ANTENNAPARTIALMETALAREA        0.13280         LAYER MET1 ;
  ANTENNAPARTIALMETALAREA        0.98400         LAYER MET2 ;
  ANTENNAMAXAREACAR              1.26190         LAYER MET1 ;
  ANTENNAMAXAREACAR              18.05238        LAYER MET2 ;
  ANTENNAMAXAREACAR              19.22381        LAYER MET3 ;
END GWEB
PIN MARE
  DIRECTION INPUT ;
  PORT
    LAYER MET1 ;
    RECT 140.680 0.000 141.090 0.180 ;
    LAYER MET2 ;
    RECT 140.680 0.000 141.090 0.180 ;
    LAYER MET3 ;
    RECT 140.680 0.000 141.090 0.180 ;
  END
  ANTENNADIFFAREA                0.27730         LAYER MET1 ;
  ANTENNADIFFAREA                0.27730         LAYER MET2 ;
  ANTENNADIFFAREA                0.27730         LAYER MET3 ;
  ANTENNAGATEAREA                0.04200         LAYER MET1 ;
  ANTENNAGATEAREA                0.04200         LAYER MET2 ;
  ANTENNAGATEAREA                0.04200         LAYER MET3 ;
  ANTENNAPARTIALMETALAREA        0.11830         LAYER MET1 ;
  ANTENNAPARTIALMETALAREA        1.73460         LAYER MET2 ;
  ANTENNAPARTIALMETALAREA        0.36060         LAYER MET3 ;
  ANTENNAMAXAREACAR              1.54762         LAYER MET1 ;
  ANTENNAMAXAREACAR              6.99048         LAYER MET2 ;
  ANTENNAMAXAREACAR              15.57619        LAYER MET3 ;
END MARE
PIN MAR[0]
  DIRECTION INPUT ;
  PORT
    LAYER MET1 ;
    RECT 140.150 0.000 140.560 0.180 ;
    LAYER MET2 ;
    RECT 140.150 0.000 140.560 0.180 ;
    LAYER MET3 ;
    RECT 140.150 0.000 140.560 0.180 ;
  END
  ANTENNADIFFAREA                0.30530         LAYER MET1 ;
  ANTENNADIFFAREA                0.30530         LAYER MET2 ;
  ANTENNADIFFAREA                0.30530         LAYER MET3 ;
  ANTENNAGATEAREA                0.04200         LAYER MET1 ;
  ANTENNAGATEAREA                0.04200         LAYER MET2 ;
  ANTENNAGATEAREA                0.04200         LAYER MET3 ;
  ANTENNAPARTIALMETALAREA        0.40280         LAYER MET1 ;
  ANTENNAPARTIALMETALAREA        1.19340         LAYER MET2 ;
  ANTENNAMAXAREACAR              8.32143         LAYER MET1 ;
  ANTENNAMAXAREACAR              38.49286        LAYER MET2 ;
  ANTENNAMAXAREACAR              40.25000        LAYER MET3 ;
END MAR[0]
PIN MAR[1]
  DIRECTION INPUT ;
  PORT
    LAYER MET1 ;
    RECT 144.745 0.000 145.155 0.180 ;
    LAYER MET2 ;
    RECT 144.745 0.000 145.155 0.180 ;
    LAYER MET3 ;
    RECT 144.745 0.000 145.155 0.180 ;
  END
  ANTENNADIFFAREA                0.30530         LAYER MET1 ;
  ANTENNADIFFAREA                0.30530         LAYER MET2 ;
  ANTENNADIFFAREA                0.30530         LAYER MET3 ;
  ANTENNAGATEAREA                0.04200         LAYER MET1 ;
  ANTENNAGATEAREA                0.04200         LAYER MET2 ;
  ANTENNAGATEAREA                0.04200         LAYER MET3 ;
  ANTENNAPARTIALMETALAREA        0.29630         LAYER MET1 ;
  ANTENNAPARTIALMETALAREA        1.11780         LAYER MET2 ;
  ANTENNAMAXAREACAR              5.78571         LAYER MET1 ;
  ANTENNAMAXAREACAR              34.15714        LAYER MET2 ;
  ANTENNAMAXAREACAR              35.91429        LAYER MET3 ;
END MAR[1]
PIN MAR[2]
  DIRECTION INPUT ;
  PORT
    LAYER MET1 ;
    RECT 143.140 0.000 143.550 0.180 ;
    LAYER MET2 ;
    RECT 143.140 0.000 143.550 0.180 ;
    LAYER MET3 ;
    RECT 143.140 0.000 143.550 0.180 ;
  END
  ANTENNADIFFAREA                0.30530         LAYER MET1 ;
  ANTENNADIFFAREA                0.30530         LAYER MET2 ;
  ANTENNADIFFAREA                0.30530         LAYER MET3 ;
  ANTENNAGATEAREA                0.04200         LAYER MET1 ;
  ANTENNAGATEAREA                0.04200         LAYER MET2 ;
  ANTENNAGATEAREA                0.04200         LAYER MET3 ;
  ANTENNAPARTIALMETALAREA        0.12430         LAYER MET1 ;
  ANTENNAPARTIALMETALAREA        1.22700         LAYER MET2 ;
  ANTENNAMAXAREACAR              1.69048         LAYER MET1 ;
  ANTENNAMAXAREACAR              32.66190        LAYER MET2 ;
  ANTENNAMAXAREACAR              34.41905        LAYER MET3 ;
END MAR[2]
PIN MAR[3]
  DIRECTION INPUT ;
  PORT
    LAYER MET1 ;
    RECT 141.500 0.000 141.910 0.180 ;
    LAYER MET2 ;
    RECT 141.500 0.000 141.910 0.180 ;
    LAYER MET3 ;
    RECT 141.500 0.000 141.910 0.180 ;
  END
  ANTENNADIFFAREA                0.30530         LAYER MET1 ;
  ANTENNADIFFAREA                0.30530         LAYER MET2 ;
  ANTENNADIFFAREA                0.30530         LAYER MET3 ;
  ANTENNAGATEAREA                0.04200         LAYER MET1 ;
  ANTENNAGATEAREA                0.04200         LAYER MET2 ;
  ANTENNAGATEAREA                0.04200         LAYER MET3 ;
  ANTENNAPARTIALMETALAREA        0.32880         LAYER MET1 ;
  ANTENNAPARTIALMETALAREA        1.21620         LAYER MET2 ;
  ANTENNAMAXAREACAR              6.55952         LAYER MET1 ;
  ANTENNAMAXAREACAR              37.27381        LAYER MET2 ;
  ANTENNAMAXAREACAR              39.03095        LAYER MET3 ;
END MAR[3]
PIN A[0]
  DIRECTION INPUT ;
  PORT
    LAYER MET1 ;
    RECT 155.900 0.000 156.310 0.180 ;
    LAYER MET2 ;
    RECT 155.900 0.000 156.310 0.180 ;
    LAYER MET3 ;
    RECT 155.900 0.000 156.310 0.180 ;
  END
  ANTENNADIFFAREA                0.43130         LAYER MET1 ;
  ANTENNADIFFAREA                0.43130         LAYER MET2 ;
  ANTENNADIFFAREA                0.43130         LAYER MET3 ;
  ANTENNAGATEAREA                0.06300         LAYER MET1 ;
  ANTENNAGATEAREA                0.06300         LAYER MET2 ;
  ANTENNAGATEAREA                0.06300         LAYER MET3 ;
  ANTENNAPARTIALMETALAREA        0.11990         LAYER MET1 ;
  ANTENNAPARTIALMETALAREA        1.91700         LAYER MET2 ;
  ANTENNAMAXAREACAR              1.05714         LAYER MET1 ;
  ANTENNAMAXAREACAR              32.65714        LAYER MET2 ;
  ANTENNAMAXAREACAR              33.82857        LAYER MET3 ;
END A[0]
PIN A[1]
  DIRECTION INPUT ;
  PORT
    LAYER MET1 ;
    RECT 155.210 0.000 155.620 0.180 ;
    LAYER MET2 ;
    RECT 155.210 0.000 155.620 0.180 ;
    LAYER MET3 ;
    RECT 155.210 0.000 155.620 0.180 ;
  END
  ANTENNADIFFAREA                0.43130         LAYER MET1 ;
  ANTENNADIFFAREA                0.43130         LAYER MET2 ;
  ANTENNADIFFAREA                0.43130         LAYER MET3 ;
  ANTENNAGATEAREA                0.06300         LAYER MET1 ;
  ANTENNAGATEAREA                0.06300         LAYER MET2 ;
  ANTENNAGATEAREA                0.06300         LAYER MET3 ;
  ANTENNAPARTIALMETALAREA        0.09890         LAYER MET1 ;
  ANTENNAPARTIALMETALAREA        1.65700         LAYER MET2 ;
  ANTENNAMAXAREACAR              0.72381         LAYER MET1 ;
  ANTENNAMAXAREACAR              28.19683        LAYER MET2 ;
  ANTENNAMAXAREACAR              29.36825        LAYER MET3 ;
END A[1]
PIN A[2]
  DIRECTION INPUT ;
  PORT
    LAYER MET1 ;
    RECT 159.590 0.000 160.000 0.180 ;
    LAYER MET2 ;
    RECT 159.590 0.000 160.000 0.180 ;
    LAYER MET3 ;
    RECT 159.590 0.000 160.000 0.180 ;
  END
  ANTENNADIFFAREA                0.43130         LAYER MET1 ;
  ANTENNADIFFAREA                0.43130         LAYER MET2 ;
  ANTENNADIFFAREA                0.43130         LAYER MET3 ;
  ANTENNAGATEAREA                0.06300         LAYER MET1 ;
  ANTENNAGATEAREA                0.06300         LAYER MET2 ;
  ANTENNAGATEAREA                0.06300         LAYER MET3 ;
  ANTENNAPARTIALMETALAREA        0.11990         LAYER MET1 ;
  ANTENNAPARTIALMETALAREA        2.04550         LAYER MET2 ;
  ANTENNAMAXAREACAR              1.05714         LAYER MET1 ;
  ANTENNAMAXAREACAR              34.69683        LAYER MET2 ;
  ANTENNAMAXAREACAR              35.86825        LAYER MET3 ;
END A[2]
PIN A[3]
  DIRECTION INPUT ;
  PORT
    LAYER MET1 ;
    RECT 158.875 0.000 159.285 0.180 ;
    LAYER MET2 ;
    RECT 158.875 0.000 159.285 0.180 ;
    LAYER MET3 ;
    RECT 158.875 0.000 159.285 0.180 ;
  END
  ANTENNADIFFAREA                0.43130         LAYER MET1 ;
  ANTENNADIFFAREA                0.43130         LAYER MET2 ;
  ANTENNADIFFAREA                0.43130         LAYER MET3 ;
  ANTENNAGATEAREA                0.06300         LAYER MET1 ;
  ANTENNAGATEAREA                0.06300         LAYER MET2 ;
  ANTENNAGATEAREA                0.06300         LAYER MET3 ;
  ANTENNAPARTIALMETALAREA        0.09890         LAYER MET1 ;
  ANTENNAPARTIALMETALAREA        2.09300         LAYER MET2 ;
  ANTENNAMAXAREACAR              0.72381         LAYER MET1 ;
  ANTENNAMAXAREACAR              35.11746        LAYER MET2 ;
  ANTENNAMAXAREACAR              36.28889        LAYER MET3 ;
END A[3]
PIN A[4]
  DIRECTION INPUT ;
  PORT
    LAYER MET1 ;
    RECT 143.685 0.000 144.095 0.180 ;
    LAYER MET2 ;
    RECT 143.685 0.000 144.095 0.180 ;
    LAYER MET3 ;
    RECT 143.685 0.000 144.095 0.180 ;
  END
  ANTENNADIFFAREA                0.68330         LAYER MET1 ;
  ANTENNADIFFAREA                0.68330         LAYER MET2 ;
  ANTENNADIFFAREA                0.68330         LAYER MET3 ;
  ANTENNAGATEAREA                0.06300         LAYER MET1 ;
  ANTENNAGATEAREA                0.06300         LAYER MET2 ;
  ANTENNAGATEAREA                0.06300         LAYER MET3 ;
  ANTENNAPARTIALMETALAREA        0.09890         LAYER MET1 ;
  ANTENNAPARTIALMETALAREA        2.08200         LAYER MET2 ;
  ANTENNAMAXAREACAR              0.72381         LAYER MET1 ;
  ANTENNAMAXAREACAR              34.94286        LAYER MET2 ;
  ANTENNAMAXAREACAR              36.11429        LAYER MET3 ;
END A[4]
PIN A[5]
  DIRECTION INPUT ;
  PORT
    LAYER MET1 ;
    RECT 146.465 0.000 146.875 0.180 ;
    LAYER MET2 ;
    RECT 146.465 0.000 146.875 0.180 ;
    LAYER MET3 ;
    RECT 146.465 0.000 146.875 0.180 ;
  END
  ANTENNADIFFAREA                0.43130         LAYER MET1 ;
  ANTENNADIFFAREA                0.43130         LAYER MET2 ;
  ANTENNADIFFAREA                0.43130         LAYER MET3 ;
  ANTENNAGATEAREA                0.06300         LAYER MET1 ;
  ANTENNAGATEAREA                0.06300         LAYER MET2 ;
  ANTENNAGATEAREA                0.06300         LAYER MET3 ;
  ANTENNAPARTIALMETALAREA        0.17870         LAYER MET1 ;
  ANTENNAPARTIALMETALAREA        1.26000         LAYER MET2 ;
  ANTENNAMAXAREACAR              1.99048         LAYER MET1 ;
  ANTENNAMAXAREACAR              23.16190        LAYER MET2 ;
  ANTENNAMAXAREACAR              24.33333        LAYER MET3 ;
END A[5]
PIN A[6]
  DIRECTION INPUT ;
  PORT
    LAYER MET1 ;
    RECT 144.215 0.000 144.625 0.180 ;
    LAYER MET2 ;
    RECT 144.215 0.000 144.625 0.180 ;
    LAYER MET3 ;
    RECT 144.215 0.000 144.625 0.180 ;
  END
  ANTENNADIFFAREA                0.68330         LAYER MET1 ;
  ANTENNADIFFAREA                0.68330         LAYER MET2 ;
  ANTENNADIFFAREA                0.68330         LAYER MET3 ;
  ANTENNAGATEAREA                0.06300         LAYER MET1 ;
  ANTENNAGATEAREA                0.06300         LAYER MET2 ;
  ANTENNAGATEAREA                0.06300         LAYER MET3 ;
  ANTENNAPARTIALMETALAREA        0.09890         LAYER MET1 ;
  ANTENNAPARTIALMETALAREA        1.99560         LAYER MET2 ;
  ANTENNAMAXAREACAR              0.72381         LAYER MET1 ;
  ANTENNAMAXAREACAR              33.57143        LAYER MET2 ;
  ANTENNAMAXAREACAR              34.74286        LAYER MET3 ;
END A[6]
PIN A[7]
  DIRECTION INPUT ;
  PORT
    LAYER MET1 ;
    RECT 142.080 0.000 142.490 0.180 ;
    LAYER MET2 ;
    RECT 142.080 0.000 142.490 0.180 ;
    LAYER MET3 ;
    RECT 142.080 0.000 142.490 0.180 ;
  END
  ANTENNADIFFAREA                0.43130         LAYER MET1 ;
  ANTENNADIFFAREA                0.43130         LAYER MET2 ;
  ANTENNADIFFAREA                0.43130         LAYER MET3 ;
  ANTENNAGATEAREA                0.06300         LAYER MET1 ;
  ANTENNAGATEAREA                0.06300         LAYER MET2 ;
  ANTENNAGATEAREA                0.06300         LAYER MET3 ;
  ANTENNAPARTIALMETALAREA        0.14330         LAYER MET1 ;
  ANTENNAPARTIALMETALAREA        2.29080         LAYER MET2 ;
  ANTENNAMAXAREACAR              1.42857         LAYER MET1 ;
  ANTENNAMAXAREACAR              38.96190        LAYER MET2 ;
  ANTENNAMAXAREACAR              40.13333        LAYER MET3 ;
END A[7]
PIN D[32]
  DIRECTION INPUT ;
  PORT
    LAYER MET1 ;
    RECT 166.290 0.000 166.700 0.180 ;
    LAYER MET2 ;
    RECT 166.290 0.000 166.700 0.180 ;
    LAYER MET3 ;
    RECT 166.290 0.000 166.700 0.180 ;
  END
  ANTENNADIFFAREA                0.38930         LAYER MET1 ;
  ANTENNADIFFAREA                0.38930         LAYER MET2 ;
  ANTENNADIFFAREA                0.38930         LAYER MET3 ;
  ANTENNAGATEAREA                0.06300         LAYER MET1 ;
  ANTENNAGATEAREA                0.06300         LAYER MET2 ;
  ANTENNAGATEAREA                0.06300         LAYER MET3 ;
  ANTENNAPARTIALMETALAREA        0.09890         LAYER MET1 ;
  ANTENNAPARTIALMETALAREA        0.10380         LAYER MET2 ;
  ANTENNAMAXAREACAR              0.72381         LAYER MET1 ;
  ANTENNAMAXAREACAR              3.54286         LAYER MET2 ;
  ANTENNAMAXAREACAR              4.71429         LAYER MET3 ;
END D[32]
PIN Q[32]
  DIRECTION OUTPUT ;
  PORT
    LAYER MET1 ;
    RECT 164.750 0.000 165.160 0.180 ;
    LAYER MET2 ;
    RECT 164.750 0.000 165.160 0.180 ;
    LAYER MET3 ;
    RECT 164.750 0.000 165.160 0.180 ;
  END
  ANTENNADIFFAREA                0.60000         LAYER MET1 ;
  ANTENNADIFFAREA                0.60000         LAYER MET2 ;
  ANTENNADIFFAREA                0.60000         LAYER MET3 ;
  ANTENNAPARTIALMETALAREA        0.94400         LAYER MET1 ;
  ANTENNAPARTIALMETALAREA        1.33320         LAYER MET2 ;
END Q[32]
PIN WEB[32]
  DIRECTION INPUT ;
  PORT
    LAYER MET1 ;
    RECT 163.940 0.000 164.350 0.180 ;
    LAYER MET2 ;
    RECT 163.940 0.000 164.350 0.180 ;
    LAYER MET3 ;
    RECT 163.940 0.000 164.350 0.180 ;
  END
  ANTENNADIFFAREA                0.45930         LAYER MET1 ;
  ANTENNADIFFAREA                0.45930         LAYER MET2 ;
  ANTENNADIFFAREA                0.45930         LAYER MET3 ;
  ANTENNAGATEAREA                0.08100         LAYER MET1 ;
  ANTENNAGATEAREA                0.08100         LAYER MET2 ;
  ANTENNAGATEAREA                0.08100         LAYER MET3 ;
  ANTENNAPARTIALMETALAREA        0.14210         LAYER MET1 ;
  ANTENNAPARTIALMETALAREA        0.09360         LAYER MET2 ;
  ANTENNAMAXAREACAR              1.09630         LAYER MET1 ;
  ANTENNAMAXAREACAR              3.16296         LAYER MET2 ;
  ANTENNAMAXAREACAR              4.07407         LAYER MET3 ;
END WEB[32]
PIN D[33]
  DIRECTION INPUT ;
  PORT
    LAYER MET1 ;
    RECT 170.490 0.000 170.900 0.180 ;
    LAYER MET2 ;
    RECT 170.490 0.000 170.900 0.180 ;
    LAYER MET3 ;
    RECT 170.490 0.000 170.900 0.180 ;
  END
  ANTENNADIFFAREA                0.38930         LAYER MET1 ;
  ANTENNADIFFAREA                0.38930         LAYER MET2 ;
  ANTENNADIFFAREA                0.38930         LAYER MET3 ;
  ANTENNAGATEAREA                0.06300         LAYER MET1 ;
  ANTENNAGATEAREA                0.06300         LAYER MET2 ;
  ANTENNAGATEAREA                0.06300         LAYER MET3 ;
  ANTENNAPARTIALMETALAREA        0.09890         LAYER MET1 ;
  ANTENNAPARTIALMETALAREA        0.10380         LAYER MET2 ;
  ANTENNAMAXAREACAR              0.72381         LAYER MET1 ;
  ANTENNAMAXAREACAR              3.54286         LAYER MET2 ;
  ANTENNAMAXAREACAR              4.71429         LAYER MET3 ;
END D[33]
PIN Q[33]
  DIRECTION OUTPUT ;
  PORT
    LAYER MET1 ;
    RECT 168.950 0.000 169.360 0.180 ;
    LAYER MET2 ;
    RECT 168.950 0.000 169.360 0.180 ;
    LAYER MET3 ;
    RECT 168.950 0.000 169.360 0.180 ;
  END
  ANTENNADIFFAREA                0.60000         LAYER MET1 ;
  ANTENNADIFFAREA                0.60000         LAYER MET2 ;
  ANTENNADIFFAREA                0.60000         LAYER MET3 ;
  ANTENNAPARTIALMETALAREA        0.94400         LAYER MET1 ;
  ANTENNAPARTIALMETALAREA        1.33320         LAYER MET2 ;
END Q[33]
PIN WEB[33]
  DIRECTION INPUT ;
  PORT
    LAYER MET1 ;
    RECT 168.140 0.000 168.550 0.180 ;
    LAYER MET2 ;
    RECT 168.140 0.000 168.550 0.180 ;
    LAYER MET3 ;
    RECT 168.140 0.000 168.550 0.180 ;
  END
  ANTENNADIFFAREA                0.45930         LAYER MET1 ;
  ANTENNADIFFAREA                0.45930         LAYER MET2 ;
  ANTENNADIFFAREA                0.45930         LAYER MET3 ;
  ANTENNAGATEAREA                0.08100         LAYER MET1 ;
  ANTENNAGATEAREA                0.08100         LAYER MET2 ;
  ANTENNAGATEAREA                0.08100         LAYER MET3 ;
  ANTENNAPARTIALMETALAREA        0.14210         LAYER MET1 ;
  ANTENNAPARTIALMETALAREA        0.09360         LAYER MET2 ;
  ANTENNAMAXAREACAR              1.09630         LAYER MET1 ;
  ANTENNAMAXAREACAR              3.16296         LAYER MET2 ;
  ANTENNAMAXAREACAR              4.07407         LAYER MET3 ;
END WEB[33]
PIN D[34]
  DIRECTION INPUT ;
  PORT
    LAYER MET1 ;
    RECT 174.690 0.000 175.100 0.180 ;
    LAYER MET2 ;
    RECT 174.690 0.000 175.100 0.180 ;
    LAYER MET3 ;
    RECT 174.690 0.000 175.100 0.180 ;
  END
  ANTENNADIFFAREA                0.38930         LAYER MET1 ;
  ANTENNADIFFAREA                0.38930         LAYER MET2 ;
  ANTENNADIFFAREA                0.38930         LAYER MET3 ;
  ANTENNAGATEAREA                0.06300         LAYER MET1 ;
  ANTENNAGATEAREA                0.06300         LAYER MET2 ;
  ANTENNAGATEAREA                0.06300         LAYER MET3 ;
  ANTENNAPARTIALMETALAREA        0.09890         LAYER MET1 ;
  ANTENNAPARTIALMETALAREA        0.10380         LAYER MET2 ;
  ANTENNAMAXAREACAR              0.72381         LAYER MET1 ;
  ANTENNAMAXAREACAR              3.54286         LAYER MET2 ;
  ANTENNAMAXAREACAR              4.71429         LAYER MET3 ;
END D[34]
PIN Q[34]
  DIRECTION OUTPUT ;
  PORT
    LAYER MET1 ;
    RECT 173.150 0.000 173.560 0.180 ;
    LAYER MET2 ;
    RECT 173.150 0.000 173.560 0.180 ;
    LAYER MET3 ;
    RECT 173.150 0.000 173.560 0.180 ;
  END
  ANTENNADIFFAREA                0.60000         LAYER MET1 ;
  ANTENNADIFFAREA                0.60000         LAYER MET2 ;
  ANTENNADIFFAREA                0.60000         LAYER MET3 ;
  ANTENNAPARTIALMETALAREA        0.94400         LAYER MET1 ;
  ANTENNAPARTIALMETALAREA        1.33320         LAYER MET2 ;
END Q[34]
PIN WEB[34]
  DIRECTION INPUT ;
  PORT
    LAYER MET1 ;
    RECT 172.340 0.000 172.750 0.180 ;
    LAYER MET2 ;
    RECT 172.340 0.000 172.750 0.180 ;
    LAYER MET3 ;
    RECT 172.340 0.000 172.750 0.180 ;
  END
  ANTENNADIFFAREA                0.45930         LAYER MET1 ;
  ANTENNADIFFAREA                0.45930         LAYER MET2 ;
  ANTENNADIFFAREA                0.45930         LAYER MET3 ;
  ANTENNAGATEAREA                0.08100         LAYER MET1 ;
  ANTENNAGATEAREA                0.08100         LAYER MET2 ;
  ANTENNAGATEAREA                0.08100         LAYER MET3 ;
  ANTENNAPARTIALMETALAREA        0.14210         LAYER MET1 ;
  ANTENNAPARTIALMETALAREA        0.09360         LAYER MET2 ;
  ANTENNAMAXAREACAR              1.09630         LAYER MET1 ;
  ANTENNAMAXAREACAR              3.16296         LAYER MET2 ;
  ANTENNAMAXAREACAR              4.07407         LAYER MET3 ;
END WEB[34]
PIN D[35]
  DIRECTION INPUT ;
  PORT
    LAYER MET1 ;
    RECT 178.890 0.000 179.300 0.180 ;
    LAYER MET2 ;
    RECT 178.890 0.000 179.300 0.180 ;
    LAYER MET3 ;
    RECT 178.890 0.000 179.300 0.180 ;
  END
  ANTENNADIFFAREA                0.38930         LAYER MET1 ;
  ANTENNADIFFAREA                0.38930         LAYER MET2 ;
  ANTENNADIFFAREA                0.38930         LAYER MET3 ;
  ANTENNAGATEAREA                0.06300         LAYER MET1 ;
  ANTENNAGATEAREA                0.06300         LAYER MET2 ;
  ANTENNAGATEAREA                0.06300         LAYER MET3 ;
  ANTENNAPARTIALMETALAREA        0.09890         LAYER MET1 ;
  ANTENNAPARTIALMETALAREA        0.10380         LAYER MET2 ;
  ANTENNAMAXAREACAR              0.72381         LAYER MET1 ;
  ANTENNAMAXAREACAR              3.54286         LAYER MET2 ;
  ANTENNAMAXAREACAR              4.71429         LAYER MET3 ;
END D[35]
PIN Q[35]
  DIRECTION OUTPUT ;
  PORT
    LAYER MET1 ;
    RECT 177.350 0.000 177.760 0.180 ;
    LAYER MET2 ;
    RECT 177.350 0.000 177.760 0.180 ;
    LAYER MET3 ;
    RECT 177.350 0.000 177.760 0.180 ;
  END
  ANTENNADIFFAREA                0.60000         LAYER MET1 ;
  ANTENNADIFFAREA                0.60000         LAYER MET2 ;
  ANTENNADIFFAREA                0.60000         LAYER MET3 ;
  ANTENNAPARTIALMETALAREA        0.94400         LAYER MET1 ;
  ANTENNAPARTIALMETALAREA        1.33320         LAYER MET2 ;
END Q[35]
PIN WEB[35]
  DIRECTION INPUT ;
  PORT
    LAYER MET1 ;
    RECT 176.540 0.000 176.950 0.180 ;
    LAYER MET2 ;
    RECT 176.540 0.000 176.950 0.180 ;
    LAYER MET3 ;
    RECT 176.540 0.000 176.950 0.180 ;
  END
  ANTENNADIFFAREA                0.45930         LAYER MET1 ;
  ANTENNADIFFAREA                0.45930         LAYER MET2 ;
  ANTENNADIFFAREA                0.45930         LAYER MET3 ;
  ANTENNAGATEAREA                0.08100         LAYER MET1 ;
  ANTENNAGATEAREA                0.08100         LAYER MET2 ;
  ANTENNAGATEAREA                0.08100         LAYER MET3 ;
  ANTENNAPARTIALMETALAREA        0.14210         LAYER MET1 ;
  ANTENNAPARTIALMETALAREA        0.09360         LAYER MET2 ;
  ANTENNAMAXAREACAR              1.09630         LAYER MET1 ;
  ANTENNAMAXAREACAR              3.16296         LAYER MET2 ;
  ANTENNAMAXAREACAR              4.07407         LAYER MET3 ;
END WEB[35]
PIN D[36]
  DIRECTION INPUT ;
  PORT
    LAYER MET1 ;
    RECT 183.090 0.000 183.500 0.180 ;
    LAYER MET2 ;
    RECT 183.090 0.000 183.500 0.180 ;
    LAYER MET3 ;
    RECT 183.090 0.000 183.500 0.180 ;
  END
  ANTENNADIFFAREA                0.38930         LAYER MET1 ;
  ANTENNADIFFAREA                0.38930         LAYER MET2 ;
  ANTENNADIFFAREA                0.38930         LAYER MET3 ;
  ANTENNAGATEAREA                0.06300         LAYER MET1 ;
  ANTENNAGATEAREA                0.06300         LAYER MET2 ;
  ANTENNAGATEAREA                0.06300         LAYER MET3 ;
  ANTENNAPARTIALMETALAREA        0.09890         LAYER MET1 ;
  ANTENNAPARTIALMETALAREA        0.10380         LAYER MET2 ;
  ANTENNAMAXAREACAR              0.72381         LAYER MET1 ;
  ANTENNAMAXAREACAR              3.54286         LAYER MET2 ;
  ANTENNAMAXAREACAR              4.71429         LAYER MET3 ;
END D[36]
PIN Q[36]
  DIRECTION OUTPUT ;
  PORT
    LAYER MET1 ;
    RECT 181.550 0.000 181.960 0.180 ;
    LAYER MET2 ;
    RECT 181.550 0.000 181.960 0.180 ;
    LAYER MET3 ;
    RECT 181.550 0.000 181.960 0.180 ;
  END
  ANTENNADIFFAREA                0.60000         LAYER MET1 ;
  ANTENNADIFFAREA                0.60000         LAYER MET2 ;
  ANTENNADIFFAREA                0.60000         LAYER MET3 ;
  ANTENNAPARTIALMETALAREA        0.94400         LAYER MET1 ;
  ANTENNAPARTIALMETALAREA        1.33320         LAYER MET2 ;
END Q[36]
PIN WEB[36]
  DIRECTION INPUT ;
  PORT
    LAYER MET1 ;
    RECT 180.740 0.000 181.150 0.180 ;
    LAYER MET2 ;
    RECT 180.740 0.000 181.150 0.180 ;
    LAYER MET3 ;
    RECT 180.740 0.000 181.150 0.180 ;
  END
  ANTENNADIFFAREA                0.45930         LAYER MET1 ;
  ANTENNADIFFAREA                0.45930         LAYER MET2 ;
  ANTENNADIFFAREA                0.45930         LAYER MET3 ;
  ANTENNAGATEAREA                0.08100         LAYER MET1 ;
  ANTENNAGATEAREA                0.08100         LAYER MET2 ;
  ANTENNAGATEAREA                0.08100         LAYER MET3 ;
  ANTENNAPARTIALMETALAREA        0.14210         LAYER MET1 ;
  ANTENNAPARTIALMETALAREA        0.09360         LAYER MET2 ;
  ANTENNAMAXAREACAR              1.09630         LAYER MET1 ;
  ANTENNAMAXAREACAR              3.16296         LAYER MET2 ;
  ANTENNAMAXAREACAR              4.07407         LAYER MET3 ;
END WEB[36]
PIN D[37]
  DIRECTION INPUT ;
  PORT
    LAYER MET1 ;
    RECT 187.290 0.000 187.700 0.180 ;
    LAYER MET2 ;
    RECT 187.290 0.000 187.700 0.180 ;
    LAYER MET3 ;
    RECT 187.290 0.000 187.700 0.180 ;
  END
  ANTENNADIFFAREA                0.38930         LAYER MET1 ;
  ANTENNADIFFAREA                0.38930         LAYER MET2 ;
  ANTENNADIFFAREA                0.38930         LAYER MET3 ;
  ANTENNAGATEAREA                0.06300         LAYER MET1 ;
  ANTENNAGATEAREA                0.06300         LAYER MET2 ;
  ANTENNAGATEAREA                0.06300         LAYER MET3 ;
  ANTENNAPARTIALMETALAREA        0.09890         LAYER MET1 ;
  ANTENNAPARTIALMETALAREA        0.10380         LAYER MET2 ;
  ANTENNAMAXAREACAR              0.72381         LAYER MET1 ;
  ANTENNAMAXAREACAR              3.54286         LAYER MET2 ;
  ANTENNAMAXAREACAR              4.71429         LAYER MET3 ;
END D[37]
PIN Q[37]
  DIRECTION OUTPUT ;
  PORT
    LAYER MET1 ;
    RECT 185.750 0.000 186.160 0.180 ;
    LAYER MET2 ;
    RECT 185.750 0.000 186.160 0.180 ;
    LAYER MET3 ;
    RECT 185.750 0.000 186.160 0.180 ;
  END
  ANTENNADIFFAREA                0.60000         LAYER MET1 ;
  ANTENNADIFFAREA                0.60000         LAYER MET2 ;
  ANTENNADIFFAREA                0.60000         LAYER MET3 ;
  ANTENNAPARTIALMETALAREA        0.94400         LAYER MET1 ;
  ANTENNAPARTIALMETALAREA        1.33320         LAYER MET2 ;
END Q[37]
PIN WEB[37]
  DIRECTION INPUT ;
  PORT
    LAYER MET1 ;
    RECT 184.940 0.000 185.350 0.180 ;
    LAYER MET2 ;
    RECT 184.940 0.000 185.350 0.180 ;
    LAYER MET3 ;
    RECT 184.940 0.000 185.350 0.180 ;
  END
  ANTENNADIFFAREA                0.45930         LAYER MET1 ;
  ANTENNADIFFAREA                0.45930         LAYER MET2 ;
  ANTENNADIFFAREA                0.45930         LAYER MET3 ;
  ANTENNAGATEAREA                0.08100         LAYER MET1 ;
  ANTENNAGATEAREA                0.08100         LAYER MET2 ;
  ANTENNAGATEAREA                0.08100         LAYER MET3 ;
  ANTENNAPARTIALMETALAREA        0.14210         LAYER MET1 ;
  ANTENNAPARTIALMETALAREA        0.09360         LAYER MET2 ;
  ANTENNAMAXAREACAR              1.09630         LAYER MET1 ;
  ANTENNAMAXAREACAR              3.16296         LAYER MET2 ;
  ANTENNAMAXAREACAR              4.07407         LAYER MET3 ;
END WEB[37]
PIN WEB[38]
  DIRECTION INPUT ;
  PORT
    LAYER MET1 ;
    RECT 189.140 0.000 189.550 0.180 ;
    LAYER MET2 ;
    RECT 189.140 0.000 189.550 0.180 ;
    LAYER MET3 ;
    RECT 189.140 0.000 189.550 0.180 ;
  END
  ANTENNADIFFAREA                0.45930         LAYER MET1 ;
  ANTENNADIFFAREA                0.45930         LAYER MET2 ;
  ANTENNADIFFAREA                0.45930         LAYER MET3 ;
  ANTENNAGATEAREA                0.08100         LAYER MET1 ;
  ANTENNAGATEAREA                0.08100         LAYER MET2 ;
  ANTENNAGATEAREA                0.08100         LAYER MET3 ;
  ANTENNAPARTIALMETALAREA        0.14210         LAYER MET1 ;
  ANTENNAPARTIALMETALAREA        0.09360         LAYER MET2 ;
  ANTENNAMAXAREACAR              1.09630         LAYER MET1 ;
  ANTENNAMAXAREACAR              3.16296         LAYER MET2 ;
  ANTENNAMAXAREACAR              4.07407         LAYER MET3 ;
END WEB[38]
PIN D[39]
  DIRECTION INPUT ;
  PORT
    LAYER MET1 ;
    RECT 195.690 0.000 196.100 0.180 ;
    LAYER MET2 ;
    RECT 195.690 0.000 196.100 0.180 ;
    LAYER MET3 ;
    RECT 195.690 0.000 196.100 0.180 ;
  END
  ANTENNADIFFAREA                0.38930         LAYER MET1 ;
  ANTENNADIFFAREA                0.38930         LAYER MET2 ;
  ANTENNADIFFAREA                0.38930         LAYER MET3 ;
  ANTENNAGATEAREA                0.06300         LAYER MET1 ;
  ANTENNAGATEAREA                0.06300         LAYER MET2 ;
  ANTENNAGATEAREA                0.06300         LAYER MET3 ;
  ANTENNAPARTIALMETALAREA        0.09890         LAYER MET1 ;
  ANTENNAPARTIALMETALAREA        0.10380         LAYER MET2 ;
  ANTENNAMAXAREACAR              0.72381         LAYER MET1 ;
  ANTENNAMAXAREACAR              3.54286         LAYER MET2 ;
  ANTENNAMAXAREACAR              4.71429         LAYER MET3 ;
END D[39]
PIN Q[39]
  DIRECTION OUTPUT ;
  PORT
    LAYER MET1 ;
    RECT 194.150 0.000 194.560 0.180 ;
    LAYER MET2 ;
    RECT 194.150 0.000 194.560 0.180 ;
    LAYER MET3 ;
    RECT 194.150 0.000 194.560 0.180 ;
  END
  ANTENNADIFFAREA                0.60000         LAYER MET1 ;
  ANTENNADIFFAREA                0.60000         LAYER MET2 ;
  ANTENNADIFFAREA                0.60000         LAYER MET3 ;
  ANTENNAPARTIALMETALAREA        0.94400         LAYER MET1 ;
  ANTENNAPARTIALMETALAREA        1.33320         LAYER MET2 ;
END Q[39]
PIN WEB[39]
  DIRECTION INPUT ;
  PORT
    LAYER MET1 ;
    RECT 193.340 0.000 193.750 0.180 ;
    LAYER MET2 ;
    RECT 193.340 0.000 193.750 0.180 ;
    LAYER MET3 ;
    RECT 193.340 0.000 193.750 0.180 ;
  END
  ANTENNADIFFAREA                0.45930         LAYER MET1 ;
  ANTENNADIFFAREA                0.45930         LAYER MET2 ;
  ANTENNADIFFAREA                0.45930         LAYER MET3 ;
  ANTENNAGATEAREA                0.08100         LAYER MET1 ;
  ANTENNAGATEAREA                0.08100         LAYER MET2 ;
  ANTENNAGATEAREA                0.08100         LAYER MET3 ;
  ANTENNAPARTIALMETALAREA        0.14210         LAYER MET1 ;
  ANTENNAPARTIALMETALAREA        0.09360         LAYER MET2 ;
  ANTENNAMAXAREACAR              1.09630         LAYER MET1 ;
  ANTENNAMAXAREACAR              3.16296         LAYER MET2 ;
  ANTENNAMAXAREACAR              4.07407         LAYER MET3 ;
END WEB[39]
PIN D[40]
  DIRECTION INPUT ;
  PORT
    LAYER MET1 ;
    RECT 199.890 0.000 200.300 0.180 ;
    LAYER MET2 ;
    RECT 199.890 0.000 200.300 0.180 ;
    LAYER MET3 ;
    RECT 199.890 0.000 200.300 0.180 ;
  END
  ANTENNADIFFAREA                0.38930         LAYER MET1 ;
  ANTENNADIFFAREA                0.38930         LAYER MET2 ;
  ANTENNADIFFAREA                0.38930         LAYER MET3 ;
  ANTENNAGATEAREA                0.06300         LAYER MET1 ;
  ANTENNAGATEAREA                0.06300         LAYER MET2 ;
  ANTENNAGATEAREA                0.06300         LAYER MET3 ;
  ANTENNAPARTIALMETALAREA        0.09890         LAYER MET1 ;
  ANTENNAPARTIALMETALAREA        0.10380         LAYER MET2 ;
  ANTENNAMAXAREACAR              0.72381         LAYER MET1 ;
  ANTENNAMAXAREACAR              3.54286         LAYER MET2 ;
  ANTENNAMAXAREACAR              4.71429         LAYER MET3 ;
END D[40]
PIN Q[40]
  DIRECTION OUTPUT ;
  PORT
    LAYER MET1 ;
    RECT 198.350 0.000 198.760 0.180 ;
    LAYER MET2 ;
    RECT 198.350 0.000 198.760 0.180 ;
    LAYER MET3 ;
    RECT 198.350 0.000 198.760 0.180 ;
  END
  ANTENNADIFFAREA                0.60000         LAYER MET1 ;
  ANTENNADIFFAREA                0.60000         LAYER MET2 ;
  ANTENNADIFFAREA                0.60000         LAYER MET3 ;
  ANTENNAPARTIALMETALAREA        0.94400         LAYER MET1 ;
  ANTENNAPARTIALMETALAREA        1.33320         LAYER MET2 ;
END Q[40]
PIN WEB[40]
  DIRECTION INPUT ;
  PORT
    LAYER MET1 ;
    RECT 197.540 0.000 197.950 0.180 ;
    LAYER MET2 ;
    RECT 197.540 0.000 197.950 0.180 ;
    LAYER MET3 ;
    RECT 197.540 0.000 197.950 0.180 ;
  END
  ANTENNADIFFAREA                0.45930         LAYER MET1 ;
  ANTENNADIFFAREA                0.45930         LAYER MET2 ;
  ANTENNADIFFAREA                0.45930         LAYER MET3 ;
  ANTENNAGATEAREA                0.08100         LAYER MET1 ;
  ANTENNAGATEAREA                0.08100         LAYER MET2 ;
  ANTENNAGATEAREA                0.08100         LAYER MET3 ;
  ANTENNAPARTIALMETALAREA        0.14210         LAYER MET1 ;
  ANTENNAPARTIALMETALAREA        0.09360         LAYER MET2 ;
  ANTENNAMAXAREACAR              1.09630         LAYER MET1 ;
  ANTENNAMAXAREACAR              3.16296         LAYER MET2 ;
  ANTENNAMAXAREACAR              4.07407         LAYER MET3 ;
END WEB[40]
PIN D[41]
  DIRECTION INPUT ;
  PORT
    LAYER MET1 ;
    RECT 204.090 0.000 204.500 0.180 ;
    LAYER MET2 ;
    RECT 204.090 0.000 204.500 0.180 ;
    LAYER MET3 ;
    RECT 204.090 0.000 204.500 0.180 ;
  END
  ANTENNADIFFAREA                0.38930         LAYER MET1 ;
  ANTENNADIFFAREA                0.38930         LAYER MET2 ;
  ANTENNADIFFAREA                0.38930         LAYER MET3 ;
  ANTENNAGATEAREA                0.06300         LAYER MET1 ;
  ANTENNAGATEAREA                0.06300         LAYER MET2 ;
  ANTENNAGATEAREA                0.06300         LAYER MET3 ;
  ANTENNAPARTIALMETALAREA        0.09890         LAYER MET1 ;
  ANTENNAPARTIALMETALAREA        0.10380         LAYER MET2 ;
  ANTENNAMAXAREACAR              0.72381         LAYER MET1 ;
  ANTENNAMAXAREACAR              3.54286         LAYER MET2 ;
  ANTENNAMAXAREACAR              4.71429         LAYER MET3 ;
END D[41]
PIN Q[41]
  DIRECTION OUTPUT ;
  PORT
    LAYER MET1 ;
    RECT 202.550 0.000 202.960 0.180 ;
    LAYER MET2 ;
    RECT 202.550 0.000 202.960 0.180 ;
    LAYER MET3 ;
    RECT 202.550 0.000 202.960 0.180 ;
  END
  ANTENNADIFFAREA                0.60000         LAYER MET1 ;
  ANTENNADIFFAREA                0.60000         LAYER MET2 ;
  ANTENNADIFFAREA                0.60000         LAYER MET3 ;
  ANTENNAPARTIALMETALAREA        0.94400         LAYER MET1 ;
  ANTENNAPARTIALMETALAREA        1.33320         LAYER MET2 ;
END Q[41]
PIN WEB[41]
  DIRECTION INPUT ;
  PORT
    LAYER MET1 ;
    RECT 201.740 0.000 202.150 0.180 ;
    LAYER MET2 ;
    RECT 201.740 0.000 202.150 0.180 ;
    LAYER MET3 ;
    RECT 201.740 0.000 202.150 0.180 ;
  END
  ANTENNADIFFAREA                0.45930         LAYER MET1 ;
  ANTENNADIFFAREA                0.45930         LAYER MET2 ;
  ANTENNADIFFAREA                0.45930         LAYER MET3 ;
  ANTENNAGATEAREA                0.08100         LAYER MET1 ;
  ANTENNAGATEAREA                0.08100         LAYER MET2 ;
  ANTENNAGATEAREA                0.08100         LAYER MET3 ;
  ANTENNAPARTIALMETALAREA        0.14210         LAYER MET1 ;
  ANTENNAPARTIALMETALAREA        0.09360         LAYER MET2 ;
  ANTENNAMAXAREACAR              1.09630         LAYER MET1 ;
  ANTENNAMAXAREACAR              3.16296         LAYER MET2 ;
  ANTENNAMAXAREACAR              4.07407         LAYER MET3 ;
END WEB[41]
PIN D[42]
  DIRECTION INPUT ;
  PORT
    LAYER MET1 ;
    RECT 208.290 0.000 208.700 0.180 ;
    LAYER MET2 ;
    RECT 208.290 0.000 208.700 0.180 ;
    LAYER MET3 ;
    RECT 208.290 0.000 208.700 0.180 ;
  END
  ANTENNADIFFAREA                0.38930         LAYER MET1 ;
  ANTENNADIFFAREA                0.38930         LAYER MET2 ;
  ANTENNADIFFAREA                0.38930         LAYER MET3 ;
  ANTENNAGATEAREA                0.06300         LAYER MET1 ;
  ANTENNAGATEAREA                0.06300         LAYER MET2 ;
  ANTENNAGATEAREA                0.06300         LAYER MET3 ;
  ANTENNAPARTIALMETALAREA        0.09890         LAYER MET1 ;
  ANTENNAPARTIALMETALAREA        0.10380         LAYER MET2 ;
  ANTENNAMAXAREACAR              0.72381         LAYER MET1 ;
  ANTENNAMAXAREACAR              3.54286         LAYER MET2 ;
  ANTENNAMAXAREACAR              4.71429         LAYER MET3 ;
END D[42]
PIN Q[42]
  DIRECTION OUTPUT ;
  PORT
    LAYER MET1 ;
    RECT 206.750 0.000 207.160 0.180 ;
    LAYER MET2 ;
    RECT 206.750 0.000 207.160 0.180 ;
    LAYER MET3 ;
    RECT 206.750 0.000 207.160 0.180 ;
  END
  ANTENNADIFFAREA                0.60000         LAYER MET1 ;
  ANTENNADIFFAREA                0.60000         LAYER MET2 ;
  ANTENNADIFFAREA                0.60000         LAYER MET3 ;
  ANTENNAPARTIALMETALAREA        0.94400         LAYER MET1 ;
  ANTENNAPARTIALMETALAREA        1.33320         LAYER MET2 ;
END Q[42]
PIN WEB[42]
  DIRECTION INPUT ;
  PORT
    LAYER MET1 ;
    RECT 205.940 0.000 206.350 0.180 ;
    LAYER MET2 ;
    RECT 205.940 0.000 206.350 0.180 ;
    LAYER MET3 ;
    RECT 205.940 0.000 206.350 0.180 ;
  END
  ANTENNADIFFAREA                0.45930         LAYER MET1 ;
  ANTENNADIFFAREA                0.45930         LAYER MET2 ;
  ANTENNADIFFAREA                0.45930         LAYER MET3 ;
  ANTENNAGATEAREA                0.08100         LAYER MET1 ;
  ANTENNAGATEAREA                0.08100         LAYER MET2 ;
  ANTENNAGATEAREA                0.08100         LAYER MET3 ;
  ANTENNAPARTIALMETALAREA        0.14210         LAYER MET1 ;
  ANTENNAPARTIALMETALAREA        0.09360         LAYER MET2 ;
  ANTENNAMAXAREACAR              1.09630         LAYER MET1 ;
  ANTENNAMAXAREACAR              3.16296         LAYER MET2 ;
  ANTENNAMAXAREACAR              4.07407         LAYER MET3 ;
END WEB[42]
PIN D[43]
  DIRECTION INPUT ;
  PORT
    LAYER MET1 ;
    RECT 212.490 0.000 212.900 0.180 ;
    LAYER MET2 ;
    RECT 212.490 0.000 212.900 0.180 ;
    LAYER MET3 ;
    RECT 212.490 0.000 212.900 0.180 ;
  END
  ANTENNADIFFAREA                0.38930         LAYER MET1 ;
  ANTENNADIFFAREA                0.38930         LAYER MET2 ;
  ANTENNADIFFAREA                0.38930         LAYER MET3 ;
  ANTENNAGATEAREA                0.06300         LAYER MET1 ;
  ANTENNAGATEAREA                0.06300         LAYER MET2 ;
  ANTENNAGATEAREA                0.06300         LAYER MET3 ;
  ANTENNAPARTIALMETALAREA        0.09890         LAYER MET1 ;
  ANTENNAPARTIALMETALAREA        0.10380         LAYER MET2 ;
  ANTENNAMAXAREACAR              0.72381         LAYER MET1 ;
  ANTENNAMAXAREACAR              3.54286         LAYER MET2 ;
  ANTENNAMAXAREACAR              4.71429         LAYER MET3 ;
END D[43]
PIN Q[43]
  DIRECTION OUTPUT ;
  PORT
    LAYER MET1 ;
    RECT 210.950 0.000 211.360 0.180 ;
    LAYER MET2 ;
    RECT 210.950 0.000 211.360 0.180 ;
    LAYER MET3 ;
    RECT 210.950 0.000 211.360 0.180 ;
  END
  ANTENNADIFFAREA                0.60000         LAYER MET1 ;
  ANTENNADIFFAREA                0.60000         LAYER MET2 ;
  ANTENNADIFFAREA                0.60000         LAYER MET3 ;
  ANTENNAPARTIALMETALAREA        0.94400         LAYER MET1 ;
  ANTENNAPARTIALMETALAREA        1.33320         LAYER MET2 ;
END Q[43]
PIN WEB[43]
  DIRECTION INPUT ;
  PORT
    LAYER MET1 ;
    RECT 210.140 0.000 210.550 0.180 ;
    LAYER MET2 ;
    RECT 210.140 0.000 210.550 0.180 ;
    LAYER MET3 ;
    RECT 210.140 0.000 210.550 0.180 ;
  END
  ANTENNADIFFAREA                0.45930         LAYER MET1 ;
  ANTENNADIFFAREA                0.45930         LAYER MET2 ;
  ANTENNADIFFAREA                0.45930         LAYER MET3 ;
  ANTENNAGATEAREA                0.08100         LAYER MET1 ;
  ANTENNAGATEAREA                0.08100         LAYER MET2 ;
  ANTENNAGATEAREA                0.08100         LAYER MET3 ;
  ANTENNAPARTIALMETALAREA        0.14210         LAYER MET1 ;
  ANTENNAPARTIALMETALAREA        0.09360         LAYER MET2 ;
  ANTENNAMAXAREACAR              1.09630         LAYER MET1 ;
  ANTENNAMAXAREACAR              3.16296         LAYER MET2 ;
  ANTENNAMAXAREACAR              4.07407         LAYER MET3 ;
END WEB[43]
PIN D[44]
  DIRECTION INPUT ;
  PORT
    LAYER MET1 ;
    RECT 216.690 0.000 217.100 0.180 ;
    LAYER MET2 ;
    RECT 216.690 0.000 217.100 0.180 ;
    LAYER MET3 ;
    RECT 216.690 0.000 217.100 0.180 ;
  END
  ANTENNADIFFAREA                0.38930         LAYER MET1 ;
  ANTENNADIFFAREA                0.38930         LAYER MET2 ;
  ANTENNADIFFAREA                0.38930         LAYER MET3 ;
  ANTENNAGATEAREA                0.06300         LAYER MET1 ;
  ANTENNAGATEAREA                0.06300         LAYER MET2 ;
  ANTENNAGATEAREA                0.06300         LAYER MET3 ;
  ANTENNAPARTIALMETALAREA        0.09890         LAYER MET1 ;
  ANTENNAPARTIALMETALAREA        0.10380         LAYER MET2 ;
  ANTENNAMAXAREACAR              0.72381         LAYER MET1 ;
  ANTENNAMAXAREACAR              3.54286         LAYER MET2 ;
  ANTENNAMAXAREACAR              4.71429         LAYER MET3 ;
END D[44]
PIN Q[44]
  DIRECTION OUTPUT ;
  PORT
    LAYER MET1 ;
    RECT 215.150 0.000 215.560 0.180 ;
    LAYER MET2 ;
    RECT 215.150 0.000 215.560 0.180 ;
    LAYER MET3 ;
    RECT 215.150 0.000 215.560 0.180 ;
  END
  ANTENNADIFFAREA                0.60000         LAYER MET1 ;
  ANTENNADIFFAREA                0.60000         LAYER MET2 ;
  ANTENNADIFFAREA                0.60000         LAYER MET3 ;
  ANTENNAPARTIALMETALAREA        0.94400         LAYER MET1 ;
  ANTENNAPARTIALMETALAREA        1.33320         LAYER MET2 ;
END Q[44]
PIN WEB[44]
  DIRECTION INPUT ;
  PORT
    LAYER MET1 ;
    RECT 214.340 0.000 214.750 0.180 ;
    LAYER MET2 ;
    RECT 214.340 0.000 214.750 0.180 ;
    LAYER MET3 ;
    RECT 214.340 0.000 214.750 0.180 ;
  END
  ANTENNADIFFAREA                0.45930         LAYER MET1 ;
  ANTENNADIFFAREA                0.45930         LAYER MET2 ;
  ANTENNADIFFAREA                0.45930         LAYER MET3 ;
  ANTENNAGATEAREA                0.08100         LAYER MET1 ;
  ANTENNAGATEAREA                0.08100         LAYER MET2 ;
  ANTENNAGATEAREA                0.08100         LAYER MET3 ;
  ANTENNAPARTIALMETALAREA        0.14210         LAYER MET1 ;
  ANTENNAPARTIALMETALAREA        0.09360         LAYER MET2 ;
  ANTENNAMAXAREACAR              1.09630         LAYER MET1 ;
  ANTENNAMAXAREACAR              3.16296         LAYER MET2 ;
  ANTENNAMAXAREACAR              4.07407         LAYER MET3 ;
END WEB[44]
PIN D[45]
  DIRECTION INPUT ;
  PORT
    LAYER MET1 ;
    RECT 220.890 0.000 221.300 0.180 ;
    LAYER MET2 ;
    RECT 220.890 0.000 221.300 0.180 ;
    LAYER MET3 ;
    RECT 220.890 0.000 221.300 0.180 ;
  END
  ANTENNADIFFAREA                0.38930         LAYER MET1 ;
  ANTENNADIFFAREA                0.38930         LAYER MET2 ;
  ANTENNADIFFAREA                0.38930         LAYER MET3 ;
  ANTENNAGATEAREA                0.06300         LAYER MET1 ;
  ANTENNAGATEAREA                0.06300         LAYER MET2 ;
  ANTENNAGATEAREA                0.06300         LAYER MET3 ;
  ANTENNAPARTIALMETALAREA        0.09890         LAYER MET1 ;
  ANTENNAPARTIALMETALAREA        0.10380         LAYER MET2 ;
  ANTENNAMAXAREACAR              0.72381         LAYER MET1 ;
  ANTENNAMAXAREACAR              3.54286         LAYER MET2 ;
  ANTENNAMAXAREACAR              4.71429         LAYER MET3 ;
END D[45]
PIN Q[45]
  DIRECTION OUTPUT ;
  PORT
    LAYER MET1 ;
    RECT 219.350 0.000 219.760 0.180 ;
    LAYER MET2 ;
    RECT 219.350 0.000 219.760 0.180 ;
    LAYER MET3 ;
    RECT 219.350 0.000 219.760 0.180 ;
  END
  ANTENNADIFFAREA                0.60000         LAYER MET1 ;
  ANTENNADIFFAREA                0.60000         LAYER MET2 ;
  ANTENNADIFFAREA                0.60000         LAYER MET3 ;
  ANTENNAPARTIALMETALAREA        0.94400         LAYER MET1 ;
  ANTENNAPARTIALMETALAREA        1.33320         LAYER MET2 ;
END Q[45]
PIN WEB[45]
  DIRECTION INPUT ;
  PORT
    LAYER MET1 ;
    RECT 218.540 0.000 218.950 0.180 ;
    LAYER MET2 ;
    RECT 218.540 0.000 218.950 0.180 ;
    LAYER MET3 ;
    RECT 218.540 0.000 218.950 0.180 ;
  END
  ANTENNADIFFAREA                0.45930         LAYER MET1 ;
  ANTENNADIFFAREA                0.45930         LAYER MET2 ;
  ANTENNADIFFAREA                0.45930         LAYER MET3 ;
  ANTENNAGATEAREA                0.08100         LAYER MET1 ;
  ANTENNAGATEAREA                0.08100         LAYER MET2 ;
  ANTENNAGATEAREA                0.08100         LAYER MET3 ;
  ANTENNAPARTIALMETALAREA        0.14210         LAYER MET1 ;
  ANTENNAPARTIALMETALAREA        0.09360         LAYER MET2 ;
  ANTENNAMAXAREACAR              1.09630         LAYER MET1 ;
  ANTENNAMAXAREACAR              3.16296         LAYER MET2 ;
  ANTENNAMAXAREACAR              4.07407         LAYER MET3 ;
END WEB[45]
PIN D[46]
  DIRECTION INPUT ;
  PORT
    LAYER MET1 ;
    RECT 225.090 0.000 225.500 0.180 ;
    LAYER MET2 ;
    RECT 225.090 0.000 225.500 0.180 ;
    LAYER MET3 ;
    RECT 225.090 0.000 225.500 0.180 ;
  END
  ANTENNADIFFAREA                0.38930         LAYER MET1 ;
  ANTENNADIFFAREA                0.38930         LAYER MET2 ;
  ANTENNADIFFAREA                0.38930         LAYER MET3 ;
  ANTENNAGATEAREA                0.06300         LAYER MET1 ;
  ANTENNAGATEAREA                0.06300         LAYER MET2 ;
  ANTENNAGATEAREA                0.06300         LAYER MET3 ;
  ANTENNAPARTIALMETALAREA        0.09890         LAYER MET1 ;
  ANTENNAPARTIALMETALAREA        0.10380         LAYER MET2 ;
  ANTENNAMAXAREACAR              0.72381         LAYER MET1 ;
  ANTENNAMAXAREACAR              3.54286         LAYER MET2 ;
  ANTENNAMAXAREACAR              4.71429         LAYER MET3 ;
END D[46]
PIN Q[46]
  DIRECTION OUTPUT ;
  PORT
    LAYER MET1 ;
    RECT 223.550 0.000 223.960 0.180 ;
    LAYER MET2 ;
    RECT 223.550 0.000 223.960 0.180 ;
    LAYER MET3 ;
    RECT 223.550 0.000 223.960 0.180 ;
  END
  ANTENNADIFFAREA                0.60000         LAYER MET1 ;
  ANTENNADIFFAREA                0.60000         LAYER MET2 ;
  ANTENNADIFFAREA                0.60000         LAYER MET3 ;
  ANTENNAPARTIALMETALAREA        0.94400         LAYER MET1 ;
  ANTENNAPARTIALMETALAREA        1.33320         LAYER MET2 ;
END Q[46]
PIN WEB[46]
  DIRECTION INPUT ;
  PORT
    LAYER MET1 ;
    RECT 222.740 0.000 223.150 0.180 ;
    LAYER MET2 ;
    RECT 222.740 0.000 223.150 0.180 ;
    LAYER MET3 ;
    RECT 222.740 0.000 223.150 0.180 ;
  END
  ANTENNADIFFAREA                0.45930         LAYER MET1 ;
  ANTENNADIFFAREA                0.45930         LAYER MET2 ;
  ANTENNADIFFAREA                0.45930         LAYER MET3 ;
  ANTENNAGATEAREA                0.08100         LAYER MET1 ;
  ANTENNAGATEAREA                0.08100         LAYER MET2 ;
  ANTENNAGATEAREA                0.08100         LAYER MET3 ;
  ANTENNAPARTIALMETALAREA        0.14210         LAYER MET1 ;
  ANTENNAPARTIALMETALAREA        0.09360         LAYER MET2 ;
  ANTENNAMAXAREACAR              1.09630         LAYER MET1 ;
  ANTENNAMAXAREACAR              3.16296         LAYER MET2 ;
  ANTENNAMAXAREACAR              4.07407         LAYER MET3 ;
END WEB[46]
PIN D[47]
  DIRECTION INPUT ;
  PORT
    LAYER MET1 ;
    RECT 229.290 0.000 229.700 0.180 ;
    LAYER MET2 ;
    RECT 229.290 0.000 229.700 0.180 ;
    LAYER MET3 ;
    RECT 229.290 0.000 229.700 0.180 ;
  END
  ANTENNADIFFAREA                0.38930         LAYER MET1 ;
  ANTENNADIFFAREA                0.38930         LAYER MET2 ;
  ANTENNADIFFAREA                0.38930         LAYER MET3 ;
  ANTENNAGATEAREA                0.06300         LAYER MET1 ;
  ANTENNAGATEAREA                0.06300         LAYER MET2 ;
  ANTENNAGATEAREA                0.06300         LAYER MET3 ;
  ANTENNAPARTIALMETALAREA        0.09890         LAYER MET1 ;
  ANTENNAPARTIALMETALAREA        0.10380         LAYER MET2 ;
  ANTENNAMAXAREACAR              0.72381         LAYER MET1 ;
  ANTENNAMAXAREACAR              3.54286         LAYER MET2 ;
  ANTENNAMAXAREACAR              4.71429         LAYER MET3 ;
END D[47]
PIN Q[47]
  DIRECTION OUTPUT ;
  PORT
    LAYER MET1 ;
    RECT 227.750 0.000 228.160 0.180 ;
    LAYER MET2 ;
    RECT 227.750 0.000 228.160 0.180 ;
    LAYER MET3 ;
    RECT 227.750 0.000 228.160 0.180 ;
  END
  ANTENNADIFFAREA                0.60000         LAYER MET1 ;
  ANTENNADIFFAREA                0.60000         LAYER MET2 ;
  ANTENNADIFFAREA                0.60000         LAYER MET3 ;
  ANTENNAPARTIALMETALAREA        0.94400         LAYER MET1 ;
  ANTENNAPARTIALMETALAREA        1.33320         LAYER MET2 ;
END Q[47]
PIN WEB[47]
  DIRECTION INPUT ;
  PORT
    LAYER MET1 ;
    RECT 226.940 0.000 227.350 0.180 ;
    LAYER MET2 ;
    RECT 226.940 0.000 227.350 0.180 ;
    LAYER MET3 ;
    RECT 226.940 0.000 227.350 0.180 ;
  END
  ANTENNADIFFAREA                0.45930         LAYER MET1 ;
  ANTENNADIFFAREA                0.45930         LAYER MET2 ;
  ANTENNADIFFAREA                0.45930         LAYER MET3 ;
  ANTENNAGATEAREA                0.08100         LAYER MET1 ;
  ANTENNAGATEAREA                0.08100         LAYER MET2 ;
  ANTENNAGATEAREA                0.08100         LAYER MET3 ;
  ANTENNAPARTIALMETALAREA        0.14210         LAYER MET1 ;
  ANTENNAPARTIALMETALAREA        0.09360         LAYER MET2 ;
  ANTENNAMAXAREACAR              1.09630         LAYER MET1 ;
  ANTENNAMAXAREACAR              3.16296         LAYER MET2 ;
  ANTENNAMAXAREACAR              4.07407         LAYER MET3 ;
END WEB[47]
PIN D[48]
  DIRECTION INPUT ;
  PORT
    LAYER MET1 ;
    RECT 233.490 0.000 233.900 0.180 ;
    LAYER MET2 ;
    RECT 233.490 0.000 233.900 0.180 ;
    LAYER MET3 ;
    RECT 233.490 0.000 233.900 0.180 ;
  END
  ANTENNADIFFAREA                0.38930         LAYER MET1 ;
  ANTENNADIFFAREA                0.38930         LAYER MET2 ;
  ANTENNADIFFAREA                0.38930         LAYER MET3 ;
  ANTENNAGATEAREA                0.06300         LAYER MET1 ;
  ANTENNAGATEAREA                0.06300         LAYER MET2 ;
  ANTENNAGATEAREA                0.06300         LAYER MET3 ;
  ANTENNAPARTIALMETALAREA        0.09890         LAYER MET1 ;
  ANTENNAPARTIALMETALAREA        0.10380         LAYER MET2 ;
  ANTENNAMAXAREACAR              0.72381         LAYER MET1 ;
  ANTENNAMAXAREACAR              3.54286         LAYER MET2 ;
  ANTENNAMAXAREACAR              4.71429         LAYER MET3 ;
END D[48]
PIN Q[48]
  DIRECTION OUTPUT ;
  PORT
    LAYER MET1 ;
    RECT 231.950 0.000 232.360 0.180 ;
    LAYER MET2 ;
    RECT 231.950 0.000 232.360 0.180 ;
    LAYER MET3 ;
    RECT 231.950 0.000 232.360 0.180 ;
  END
  ANTENNADIFFAREA                0.60000         LAYER MET1 ;
  ANTENNADIFFAREA                0.60000         LAYER MET2 ;
  ANTENNADIFFAREA                0.60000         LAYER MET3 ;
  ANTENNAPARTIALMETALAREA        0.94400         LAYER MET1 ;
  ANTENNAPARTIALMETALAREA        1.33320         LAYER MET2 ;
END Q[48]
PIN WEB[48]
  DIRECTION INPUT ;
  PORT
    LAYER MET1 ;
    RECT 231.140 0.000 231.550 0.180 ;
    LAYER MET2 ;
    RECT 231.140 0.000 231.550 0.180 ;
    LAYER MET3 ;
    RECT 231.140 0.000 231.550 0.180 ;
  END
  ANTENNADIFFAREA                0.45930         LAYER MET1 ;
  ANTENNADIFFAREA                0.45930         LAYER MET2 ;
  ANTENNADIFFAREA                0.45930         LAYER MET3 ;
  ANTENNAGATEAREA                0.08100         LAYER MET1 ;
  ANTENNAGATEAREA                0.08100         LAYER MET2 ;
  ANTENNAGATEAREA                0.08100         LAYER MET3 ;
  ANTENNAPARTIALMETALAREA        0.14210         LAYER MET1 ;
  ANTENNAPARTIALMETALAREA        0.09360         LAYER MET2 ;
  ANTENNAMAXAREACAR              1.09630         LAYER MET1 ;
  ANTENNAMAXAREACAR              3.16296         LAYER MET2 ;
  ANTENNAMAXAREACAR              4.07407         LAYER MET3 ;
END WEB[48]
PIN D[49]
  DIRECTION INPUT ;
  PORT
    LAYER MET1 ;
    RECT 237.690 0.000 238.100 0.180 ;
    LAYER MET2 ;
    RECT 237.690 0.000 238.100 0.180 ;
    LAYER MET3 ;
    RECT 237.690 0.000 238.100 0.180 ;
  END
  ANTENNADIFFAREA                0.38930         LAYER MET1 ;
  ANTENNADIFFAREA                0.38930         LAYER MET2 ;
  ANTENNADIFFAREA                0.38930         LAYER MET3 ;
  ANTENNAGATEAREA                0.06300         LAYER MET1 ;
  ANTENNAGATEAREA                0.06300         LAYER MET2 ;
  ANTENNAGATEAREA                0.06300         LAYER MET3 ;
  ANTENNAPARTIALMETALAREA        0.09890         LAYER MET1 ;
  ANTENNAPARTIALMETALAREA        0.10380         LAYER MET2 ;
  ANTENNAMAXAREACAR              0.72381         LAYER MET1 ;
  ANTENNAMAXAREACAR              3.54286         LAYER MET2 ;
  ANTENNAMAXAREACAR              4.71429         LAYER MET3 ;
END D[49]
PIN Q[49]
  DIRECTION OUTPUT ;
  PORT
    LAYER MET1 ;
    RECT 236.150 0.000 236.560 0.180 ;
    LAYER MET2 ;
    RECT 236.150 0.000 236.560 0.180 ;
    LAYER MET3 ;
    RECT 236.150 0.000 236.560 0.180 ;
  END
  ANTENNADIFFAREA                0.60000         LAYER MET1 ;
  ANTENNADIFFAREA                0.60000         LAYER MET2 ;
  ANTENNADIFFAREA                0.60000         LAYER MET3 ;
  ANTENNAPARTIALMETALAREA        0.94400         LAYER MET1 ;
  ANTENNAPARTIALMETALAREA        1.33320         LAYER MET2 ;
END Q[49]
PIN WEB[49]
  DIRECTION INPUT ;
  PORT
    LAYER MET1 ;
    RECT 235.340 0.000 235.750 0.180 ;
    LAYER MET2 ;
    RECT 235.340 0.000 235.750 0.180 ;
    LAYER MET3 ;
    RECT 235.340 0.000 235.750 0.180 ;
  END
  ANTENNADIFFAREA                0.45930         LAYER MET1 ;
  ANTENNADIFFAREA                0.45930         LAYER MET2 ;
  ANTENNADIFFAREA                0.45930         LAYER MET3 ;
  ANTENNAGATEAREA                0.08100         LAYER MET1 ;
  ANTENNAGATEAREA                0.08100         LAYER MET2 ;
  ANTENNAGATEAREA                0.08100         LAYER MET3 ;
  ANTENNAPARTIALMETALAREA        0.14210         LAYER MET1 ;
  ANTENNAPARTIALMETALAREA        0.09360         LAYER MET2 ;
  ANTENNAMAXAREACAR              1.09630         LAYER MET1 ;
  ANTENNAMAXAREACAR              3.16296         LAYER MET2 ;
  ANTENNAMAXAREACAR              4.07407         LAYER MET3 ;
END WEB[49]
PIN D[50]
  DIRECTION INPUT ;
  PORT
    LAYER MET1 ;
    RECT 241.890 0.000 242.300 0.180 ;
    LAYER MET2 ;
    RECT 241.890 0.000 242.300 0.180 ;
    LAYER MET3 ;
    RECT 241.890 0.000 242.300 0.180 ;
  END
  ANTENNADIFFAREA                0.38930         LAYER MET1 ;
  ANTENNADIFFAREA                0.38930         LAYER MET2 ;
  ANTENNADIFFAREA                0.38930         LAYER MET3 ;
  ANTENNAGATEAREA                0.06300         LAYER MET1 ;
  ANTENNAGATEAREA                0.06300         LAYER MET2 ;
  ANTENNAGATEAREA                0.06300         LAYER MET3 ;
  ANTENNAPARTIALMETALAREA        0.09890         LAYER MET1 ;
  ANTENNAPARTIALMETALAREA        0.10380         LAYER MET2 ;
  ANTENNAMAXAREACAR              0.72381         LAYER MET1 ;
  ANTENNAMAXAREACAR              3.54286         LAYER MET2 ;
  ANTENNAMAXAREACAR              4.71429         LAYER MET3 ;
END D[50]
PIN Q[50]
  DIRECTION OUTPUT ;
  PORT
    LAYER MET1 ;
    RECT 240.350 0.000 240.760 0.180 ;
    LAYER MET2 ;
    RECT 240.350 0.000 240.760 0.180 ;
    LAYER MET3 ;
    RECT 240.350 0.000 240.760 0.180 ;
  END
  ANTENNADIFFAREA                0.60000         LAYER MET1 ;
  ANTENNADIFFAREA                0.60000         LAYER MET2 ;
  ANTENNADIFFAREA                0.60000         LAYER MET3 ;
  ANTENNAPARTIALMETALAREA        0.94400         LAYER MET1 ;
  ANTENNAPARTIALMETALAREA        1.33320         LAYER MET2 ;
END Q[50]
PIN WEB[50]
  DIRECTION INPUT ;
  PORT
    LAYER MET1 ;
    RECT 239.540 0.000 239.950 0.180 ;
    LAYER MET2 ;
    RECT 239.540 0.000 239.950 0.180 ;
    LAYER MET3 ;
    RECT 239.540 0.000 239.950 0.180 ;
  END
  ANTENNADIFFAREA                0.45930         LAYER MET1 ;
  ANTENNADIFFAREA                0.45930         LAYER MET2 ;
  ANTENNADIFFAREA                0.45930         LAYER MET3 ;
  ANTENNAGATEAREA                0.08100         LAYER MET1 ;
  ANTENNAGATEAREA                0.08100         LAYER MET2 ;
  ANTENNAGATEAREA                0.08100         LAYER MET3 ;
  ANTENNAPARTIALMETALAREA        0.14210         LAYER MET1 ;
  ANTENNAPARTIALMETALAREA        0.09360         LAYER MET2 ;
  ANTENNAMAXAREACAR              1.09630         LAYER MET1 ;
  ANTENNAMAXAREACAR              3.16296         LAYER MET2 ;
  ANTENNAMAXAREACAR              4.07407         LAYER MET3 ;
END WEB[50]
PIN D[51]
  DIRECTION INPUT ;
  PORT
    LAYER MET1 ;
    RECT 246.090 0.000 246.500 0.180 ;
    LAYER MET2 ;
    RECT 246.090 0.000 246.500 0.180 ;
    LAYER MET3 ;
    RECT 246.090 0.000 246.500 0.180 ;
  END
  ANTENNADIFFAREA                0.38930         LAYER MET1 ;
  ANTENNADIFFAREA                0.38930         LAYER MET2 ;
  ANTENNADIFFAREA                0.38930         LAYER MET3 ;
  ANTENNAGATEAREA                0.06300         LAYER MET1 ;
  ANTENNAGATEAREA                0.06300         LAYER MET2 ;
  ANTENNAGATEAREA                0.06300         LAYER MET3 ;
  ANTENNAPARTIALMETALAREA        0.09890         LAYER MET1 ;
  ANTENNAPARTIALMETALAREA        0.10380         LAYER MET2 ;
  ANTENNAMAXAREACAR              0.72381         LAYER MET1 ;
  ANTENNAMAXAREACAR              3.54286         LAYER MET2 ;
  ANTENNAMAXAREACAR              4.71429         LAYER MET3 ;
END D[51]
PIN Q[51]
  DIRECTION OUTPUT ;
  PORT
    LAYER MET1 ;
    RECT 244.550 0.000 244.960 0.180 ;
    LAYER MET2 ;
    RECT 244.550 0.000 244.960 0.180 ;
    LAYER MET3 ;
    RECT 244.550 0.000 244.960 0.180 ;
  END
  ANTENNADIFFAREA                0.60000         LAYER MET1 ;
  ANTENNADIFFAREA                0.60000         LAYER MET2 ;
  ANTENNADIFFAREA                0.60000         LAYER MET3 ;
  ANTENNAPARTIALMETALAREA        0.94400         LAYER MET1 ;
  ANTENNAPARTIALMETALAREA        1.33320         LAYER MET2 ;
END Q[51]
PIN WEB[51]
  DIRECTION INPUT ;
  PORT
    LAYER MET1 ;
    RECT 243.740 0.000 244.150 0.180 ;
    LAYER MET2 ;
    RECT 243.740 0.000 244.150 0.180 ;
    LAYER MET3 ;
    RECT 243.740 0.000 244.150 0.180 ;
  END
  ANTENNADIFFAREA                0.45930         LAYER MET1 ;
  ANTENNADIFFAREA                0.45930         LAYER MET2 ;
  ANTENNADIFFAREA                0.45930         LAYER MET3 ;
  ANTENNAGATEAREA                0.08100         LAYER MET1 ;
  ANTENNAGATEAREA                0.08100         LAYER MET2 ;
  ANTENNAGATEAREA                0.08100         LAYER MET3 ;
  ANTENNAPARTIALMETALAREA        0.14210         LAYER MET1 ;
  ANTENNAPARTIALMETALAREA        0.09360         LAYER MET2 ;
  ANTENNAMAXAREACAR              1.09630         LAYER MET1 ;
  ANTENNAMAXAREACAR              3.16296         LAYER MET2 ;
  ANTENNAMAXAREACAR              4.07407         LAYER MET3 ;
END WEB[51]
PIN D[52]
  DIRECTION INPUT ;
  PORT
    LAYER MET1 ;
    RECT 250.290 0.000 250.700 0.180 ;
    LAYER MET2 ;
    RECT 250.290 0.000 250.700 0.180 ;
    LAYER MET3 ;
    RECT 250.290 0.000 250.700 0.180 ;
  END
  ANTENNADIFFAREA                0.38930         LAYER MET1 ;
  ANTENNADIFFAREA                0.38930         LAYER MET2 ;
  ANTENNADIFFAREA                0.38930         LAYER MET3 ;
  ANTENNAGATEAREA                0.06300         LAYER MET1 ;
  ANTENNAGATEAREA                0.06300         LAYER MET2 ;
  ANTENNAGATEAREA                0.06300         LAYER MET3 ;
  ANTENNAPARTIALMETALAREA        0.09890         LAYER MET1 ;
  ANTENNAPARTIALMETALAREA        0.10380         LAYER MET2 ;
  ANTENNAMAXAREACAR              0.72381         LAYER MET1 ;
  ANTENNAMAXAREACAR              3.54286         LAYER MET2 ;
  ANTENNAMAXAREACAR              4.71429         LAYER MET3 ;
END D[52]
PIN Q[52]
  DIRECTION OUTPUT ;
  PORT
    LAYER MET1 ;
    RECT 248.750 0.000 249.160 0.180 ;
    LAYER MET2 ;
    RECT 248.750 0.000 249.160 0.180 ;
    LAYER MET3 ;
    RECT 248.750 0.000 249.160 0.180 ;
  END
  ANTENNADIFFAREA                0.60000         LAYER MET1 ;
  ANTENNADIFFAREA                0.60000         LAYER MET2 ;
  ANTENNADIFFAREA                0.60000         LAYER MET3 ;
  ANTENNAPARTIALMETALAREA        0.94400         LAYER MET1 ;
  ANTENNAPARTIALMETALAREA        1.33320         LAYER MET2 ;
END Q[52]
PIN WEB[52]
  DIRECTION INPUT ;
  PORT
    LAYER MET1 ;
    RECT 247.940 0.000 248.350 0.180 ;
    LAYER MET2 ;
    RECT 247.940 0.000 248.350 0.180 ;
    LAYER MET3 ;
    RECT 247.940 0.000 248.350 0.180 ;
  END
  ANTENNADIFFAREA                0.45930         LAYER MET1 ;
  ANTENNADIFFAREA                0.45930         LAYER MET2 ;
  ANTENNADIFFAREA                0.45930         LAYER MET3 ;
  ANTENNAGATEAREA                0.08100         LAYER MET1 ;
  ANTENNAGATEAREA                0.08100         LAYER MET2 ;
  ANTENNAGATEAREA                0.08100         LAYER MET3 ;
  ANTENNAPARTIALMETALAREA        0.14210         LAYER MET1 ;
  ANTENNAPARTIALMETALAREA        0.09360         LAYER MET2 ;
  ANTENNAMAXAREACAR              1.09630         LAYER MET1 ;
  ANTENNAMAXAREACAR              3.16296         LAYER MET2 ;
  ANTENNAMAXAREACAR              4.07407         LAYER MET3 ;
END WEB[52]
PIN D[53]
  DIRECTION INPUT ;
  PORT
    LAYER MET1 ;
    RECT 254.490 0.000 254.900 0.180 ;
    LAYER MET2 ;
    RECT 254.490 0.000 254.900 0.180 ;
    LAYER MET3 ;
    RECT 254.490 0.000 254.900 0.180 ;
  END
  ANTENNADIFFAREA                0.38930         LAYER MET1 ;
  ANTENNADIFFAREA                0.38930         LAYER MET2 ;
  ANTENNADIFFAREA                0.38930         LAYER MET3 ;
  ANTENNAGATEAREA                0.06300         LAYER MET1 ;
  ANTENNAGATEAREA                0.06300         LAYER MET2 ;
  ANTENNAGATEAREA                0.06300         LAYER MET3 ;
  ANTENNAPARTIALMETALAREA        0.09890         LAYER MET1 ;
  ANTENNAPARTIALMETALAREA        0.10380         LAYER MET2 ;
  ANTENNAMAXAREACAR              0.72381         LAYER MET1 ;
  ANTENNAMAXAREACAR              3.54286         LAYER MET2 ;
  ANTENNAMAXAREACAR              4.71429         LAYER MET3 ;
END D[53]
PIN Q[53]
  DIRECTION OUTPUT ;
  PORT
    LAYER MET1 ;
    RECT 252.950 0.000 253.360 0.180 ;
    LAYER MET2 ;
    RECT 252.950 0.000 253.360 0.180 ;
    LAYER MET3 ;
    RECT 252.950 0.000 253.360 0.180 ;
  END
  ANTENNADIFFAREA                0.60000         LAYER MET1 ;
  ANTENNADIFFAREA                0.60000         LAYER MET2 ;
  ANTENNADIFFAREA                0.60000         LAYER MET3 ;
  ANTENNAPARTIALMETALAREA        0.94400         LAYER MET1 ;
  ANTENNAPARTIALMETALAREA        1.33320         LAYER MET2 ;
END Q[53]
PIN WEB[53]
  DIRECTION INPUT ;
  PORT
    LAYER MET1 ;
    RECT 252.140 0.000 252.550 0.180 ;
    LAYER MET2 ;
    RECT 252.140 0.000 252.550 0.180 ;
    LAYER MET3 ;
    RECT 252.140 0.000 252.550 0.180 ;
  END
  ANTENNADIFFAREA                0.45930         LAYER MET1 ;
  ANTENNADIFFAREA                0.45930         LAYER MET2 ;
  ANTENNADIFFAREA                0.45930         LAYER MET3 ;
  ANTENNAGATEAREA                0.08100         LAYER MET1 ;
  ANTENNAGATEAREA                0.08100         LAYER MET2 ;
  ANTENNAGATEAREA                0.08100         LAYER MET3 ;
  ANTENNAPARTIALMETALAREA        0.14210         LAYER MET1 ;
  ANTENNAPARTIALMETALAREA        0.09360         LAYER MET2 ;
  ANTENNAMAXAREACAR              1.09630         LAYER MET1 ;
  ANTENNAMAXAREACAR              3.16296         LAYER MET2 ;
  ANTENNAMAXAREACAR              4.07407         LAYER MET3 ;
END WEB[53]
PIN D[54]
  DIRECTION INPUT ;
  PORT
    LAYER MET1 ;
    RECT 258.690 0.000 259.100 0.180 ;
    LAYER MET2 ;
    RECT 258.690 0.000 259.100 0.180 ;
    LAYER MET3 ;
    RECT 258.690 0.000 259.100 0.180 ;
  END
  ANTENNADIFFAREA                0.38930         LAYER MET1 ;
  ANTENNADIFFAREA                0.38930         LAYER MET2 ;
  ANTENNADIFFAREA                0.38930         LAYER MET3 ;
  ANTENNAGATEAREA                0.06300         LAYER MET1 ;
  ANTENNAGATEAREA                0.06300         LAYER MET2 ;
  ANTENNAGATEAREA                0.06300         LAYER MET3 ;
  ANTENNAPARTIALMETALAREA        0.09890         LAYER MET1 ;
  ANTENNAPARTIALMETALAREA        0.10380         LAYER MET2 ;
  ANTENNAMAXAREACAR              0.72381         LAYER MET1 ;
  ANTENNAMAXAREACAR              3.54286         LAYER MET2 ;
  ANTENNAMAXAREACAR              4.71429         LAYER MET3 ;
END D[54]
PIN Q[54]
  DIRECTION OUTPUT ;
  PORT
    LAYER MET1 ;
    RECT 257.150 0.000 257.560 0.180 ;
    LAYER MET2 ;
    RECT 257.150 0.000 257.560 0.180 ;
    LAYER MET3 ;
    RECT 257.150 0.000 257.560 0.180 ;
  END
  ANTENNADIFFAREA                0.60000         LAYER MET1 ;
  ANTENNADIFFAREA                0.60000         LAYER MET2 ;
  ANTENNADIFFAREA                0.60000         LAYER MET3 ;
  ANTENNAPARTIALMETALAREA        0.94400         LAYER MET1 ;
  ANTENNAPARTIALMETALAREA        1.33320         LAYER MET2 ;
END Q[54]
PIN WEB[54]
  DIRECTION INPUT ;
  PORT
    LAYER MET1 ;
    RECT 256.340 0.000 256.750 0.180 ;
    LAYER MET2 ;
    RECT 256.340 0.000 256.750 0.180 ;
    LAYER MET3 ;
    RECT 256.340 0.000 256.750 0.180 ;
  END
  ANTENNADIFFAREA                0.45930         LAYER MET1 ;
  ANTENNADIFFAREA                0.45930         LAYER MET2 ;
  ANTENNADIFFAREA                0.45930         LAYER MET3 ;
  ANTENNAGATEAREA                0.08100         LAYER MET1 ;
  ANTENNAGATEAREA                0.08100         LAYER MET2 ;
  ANTENNAGATEAREA                0.08100         LAYER MET3 ;
  ANTENNAPARTIALMETALAREA        0.14210         LAYER MET1 ;
  ANTENNAPARTIALMETALAREA        0.09360         LAYER MET2 ;
  ANTENNAMAXAREACAR              1.09630         LAYER MET1 ;
  ANTENNAMAXAREACAR              3.16296         LAYER MET2 ;
  ANTENNAMAXAREACAR              4.07407         LAYER MET3 ;
END WEB[54]
PIN D[55]
  DIRECTION INPUT ;
  PORT
    LAYER MET1 ;
    RECT 262.890 0.000 263.300 0.180 ;
    LAYER MET2 ;
    RECT 262.890 0.000 263.300 0.180 ;
    LAYER MET3 ;
    RECT 262.890 0.000 263.300 0.180 ;
  END
  ANTENNADIFFAREA                0.38930         LAYER MET1 ;
  ANTENNADIFFAREA                0.38930         LAYER MET2 ;
  ANTENNADIFFAREA                0.38930         LAYER MET3 ;
  ANTENNAGATEAREA                0.06300         LAYER MET1 ;
  ANTENNAGATEAREA                0.06300         LAYER MET2 ;
  ANTENNAGATEAREA                0.06300         LAYER MET3 ;
  ANTENNAPARTIALMETALAREA        0.09890         LAYER MET1 ;
  ANTENNAPARTIALMETALAREA        0.10380         LAYER MET2 ;
  ANTENNAMAXAREACAR              0.72381         LAYER MET1 ;
  ANTENNAMAXAREACAR              3.54286         LAYER MET2 ;
  ANTENNAMAXAREACAR              4.71429         LAYER MET3 ;
END D[55]
PIN Q[55]
  DIRECTION OUTPUT ;
  PORT
    LAYER MET1 ;
    RECT 261.350 0.000 261.760 0.180 ;
    LAYER MET2 ;
    RECT 261.350 0.000 261.760 0.180 ;
    LAYER MET3 ;
    RECT 261.350 0.000 261.760 0.180 ;
  END
  ANTENNADIFFAREA                0.60000         LAYER MET1 ;
  ANTENNADIFFAREA                0.60000         LAYER MET2 ;
  ANTENNADIFFAREA                0.60000         LAYER MET3 ;
  ANTENNAPARTIALMETALAREA        0.94400         LAYER MET1 ;
  ANTENNAPARTIALMETALAREA        1.33320         LAYER MET2 ;
END Q[55]
PIN WEB[55]
  DIRECTION INPUT ;
  PORT
    LAYER MET1 ;
    RECT 260.540 0.000 260.950 0.180 ;
    LAYER MET2 ;
    RECT 260.540 0.000 260.950 0.180 ;
    LAYER MET3 ;
    RECT 260.540 0.000 260.950 0.180 ;
  END
  ANTENNADIFFAREA                0.45930         LAYER MET1 ;
  ANTENNADIFFAREA                0.45930         LAYER MET2 ;
  ANTENNADIFFAREA                0.45930         LAYER MET3 ;
  ANTENNAGATEAREA                0.08100         LAYER MET1 ;
  ANTENNAGATEAREA                0.08100         LAYER MET2 ;
  ANTENNAGATEAREA                0.08100         LAYER MET3 ;
  ANTENNAPARTIALMETALAREA        0.14210         LAYER MET1 ;
  ANTENNAPARTIALMETALAREA        0.09360         LAYER MET2 ;
  ANTENNAMAXAREACAR              1.09630         LAYER MET1 ;
  ANTENNAMAXAREACAR              3.16296         LAYER MET2 ;
  ANTENNAMAXAREACAR              4.07407         LAYER MET3 ;
END WEB[55]
PIN D[56]
  DIRECTION INPUT ;
  PORT
    LAYER MET1 ;
    RECT 267.090 0.000 267.500 0.180 ;
    LAYER MET2 ;
    RECT 267.090 0.000 267.500 0.180 ;
    LAYER MET3 ;
    RECT 267.090 0.000 267.500 0.180 ;
  END
  ANTENNADIFFAREA                0.38930         LAYER MET1 ;
  ANTENNADIFFAREA                0.38930         LAYER MET2 ;
  ANTENNADIFFAREA                0.38930         LAYER MET3 ;
  ANTENNAGATEAREA                0.06300         LAYER MET1 ;
  ANTENNAGATEAREA                0.06300         LAYER MET2 ;
  ANTENNAGATEAREA                0.06300         LAYER MET3 ;
  ANTENNAPARTIALMETALAREA        0.09890         LAYER MET1 ;
  ANTENNAPARTIALMETALAREA        0.10380         LAYER MET2 ;
  ANTENNAMAXAREACAR              0.72381         LAYER MET1 ;
  ANTENNAMAXAREACAR              3.54286         LAYER MET2 ;
  ANTENNAMAXAREACAR              4.71429         LAYER MET3 ;
END D[56]
PIN Q[56]
  DIRECTION OUTPUT ;
  PORT
    LAYER MET1 ;
    RECT 265.550 0.000 265.960 0.180 ;
    LAYER MET2 ;
    RECT 265.550 0.000 265.960 0.180 ;
    LAYER MET3 ;
    RECT 265.550 0.000 265.960 0.180 ;
  END
  ANTENNADIFFAREA                0.60000         LAYER MET1 ;
  ANTENNADIFFAREA                0.60000         LAYER MET2 ;
  ANTENNADIFFAREA                0.60000         LAYER MET3 ;
  ANTENNAPARTIALMETALAREA        0.94400         LAYER MET1 ;
  ANTENNAPARTIALMETALAREA        1.33320         LAYER MET2 ;
END Q[56]
PIN WEB[56]
  DIRECTION INPUT ;
  PORT
    LAYER MET1 ;
    RECT 264.740 0.000 265.150 0.180 ;
    LAYER MET2 ;
    RECT 264.740 0.000 265.150 0.180 ;
    LAYER MET3 ;
    RECT 264.740 0.000 265.150 0.180 ;
  END
  ANTENNADIFFAREA                0.45930         LAYER MET1 ;
  ANTENNADIFFAREA                0.45930         LAYER MET2 ;
  ANTENNADIFFAREA                0.45930         LAYER MET3 ;
  ANTENNAGATEAREA                0.08100         LAYER MET1 ;
  ANTENNAGATEAREA                0.08100         LAYER MET2 ;
  ANTENNAGATEAREA                0.08100         LAYER MET3 ;
  ANTENNAPARTIALMETALAREA        0.14210         LAYER MET1 ;
  ANTENNAPARTIALMETALAREA        0.09360         LAYER MET2 ;
  ANTENNAMAXAREACAR              1.09630         LAYER MET1 ;
  ANTENNAMAXAREACAR              3.16296         LAYER MET2 ;
  ANTENNAMAXAREACAR              4.07407         LAYER MET3 ;
END WEB[56]
PIN D[57]
  DIRECTION INPUT ;
  PORT
    LAYER MET1 ;
    RECT 271.290 0.000 271.700 0.180 ;
    LAYER MET2 ;
    RECT 271.290 0.000 271.700 0.180 ;
    LAYER MET3 ;
    RECT 271.290 0.000 271.700 0.180 ;
  END
  ANTENNADIFFAREA                0.38930         LAYER MET1 ;
  ANTENNADIFFAREA                0.38930         LAYER MET2 ;
  ANTENNADIFFAREA                0.38930         LAYER MET3 ;
  ANTENNAGATEAREA                0.06300         LAYER MET1 ;
  ANTENNAGATEAREA                0.06300         LAYER MET2 ;
  ANTENNAGATEAREA                0.06300         LAYER MET3 ;
  ANTENNAPARTIALMETALAREA        0.09890         LAYER MET1 ;
  ANTENNAPARTIALMETALAREA        0.10380         LAYER MET2 ;
  ANTENNAMAXAREACAR              0.72381         LAYER MET1 ;
  ANTENNAMAXAREACAR              3.54286         LAYER MET2 ;
  ANTENNAMAXAREACAR              4.71429         LAYER MET3 ;
END D[57]
PIN Q[57]
  DIRECTION OUTPUT ;
  PORT
    LAYER MET1 ;
    RECT 269.750 0.000 270.160 0.180 ;
    LAYER MET2 ;
    RECT 269.750 0.000 270.160 0.180 ;
    LAYER MET3 ;
    RECT 269.750 0.000 270.160 0.180 ;
  END
  ANTENNADIFFAREA                0.60000         LAYER MET1 ;
  ANTENNADIFFAREA                0.60000         LAYER MET2 ;
  ANTENNADIFFAREA                0.60000         LAYER MET3 ;
  ANTENNAPARTIALMETALAREA        0.94400         LAYER MET1 ;
  ANTENNAPARTIALMETALAREA        1.33320         LAYER MET2 ;
END Q[57]
PIN WEB[57]
  DIRECTION INPUT ;
  PORT
    LAYER MET1 ;
    RECT 268.940 0.000 269.350 0.180 ;
    LAYER MET2 ;
    RECT 268.940 0.000 269.350 0.180 ;
    LAYER MET3 ;
    RECT 268.940 0.000 269.350 0.180 ;
  END
  ANTENNADIFFAREA                0.45930         LAYER MET1 ;
  ANTENNADIFFAREA                0.45930         LAYER MET2 ;
  ANTENNADIFFAREA                0.45930         LAYER MET3 ;
  ANTENNAGATEAREA                0.08100         LAYER MET1 ;
  ANTENNAGATEAREA                0.08100         LAYER MET2 ;
  ANTENNAGATEAREA                0.08100         LAYER MET3 ;
  ANTENNAPARTIALMETALAREA        0.14210         LAYER MET1 ;
  ANTENNAPARTIALMETALAREA        0.09360         LAYER MET2 ;
  ANTENNAMAXAREACAR              1.09630         LAYER MET1 ;
  ANTENNAMAXAREACAR              3.16296         LAYER MET2 ;
  ANTENNAMAXAREACAR              4.07407         LAYER MET3 ;
END WEB[57]
PIN D[58]
  DIRECTION INPUT ;
  PORT
    LAYER MET1 ;
    RECT 275.490 0.000 275.900 0.180 ;
    LAYER MET2 ;
    RECT 275.490 0.000 275.900 0.180 ;
    LAYER MET3 ;
    RECT 275.490 0.000 275.900 0.180 ;
  END
  ANTENNADIFFAREA                0.38930         LAYER MET1 ;
  ANTENNADIFFAREA                0.38930         LAYER MET2 ;
  ANTENNADIFFAREA                0.38930         LAYER MET3 ;
  ANTENNAGATEAREA                0.06300         LAYER MET1 ;
  ANTENNAGATEAREA                0.06300         LAYER MET2 ;
  ANTENNAGATEAREA                0.06300         LAYER MET3 ;
  ANTENNAPARTIALMETALAREA        0.09890         LAYER MET1 ;
  ANTENNAPARTIALMETALAREA        0.10380         LAYER MET2 ;
  ANTENNAMAXAREACAR              0.72381         LAYER MET1 ;
  ANTENNAMAXAREACAR              3.54286         LAYER MET2 ;
  ANTENNAMAXAREACAR              4.71429         LAYER MET3 ;
END D[58]
PIN Q[58]
  DIRECTION OUTPUT ;
  PORT
    LAYER MET1 ;
    RECT 273.950 0.000 274.360 0.180 ;
    LAYER MET2 ;
    RECT 273.950 0.000 274.360 0.180 ;
    LAYER MET3 ;
    RECT 273.950 0.000 274.360 0.180 ;
  END
  ANTENNADIFFAREA                0.60000         LAYER MET1 ;
  ANTENNADIFFAREA                0.60000         LAYER MET2 ;
  ANTENNADIFFAREA                0.60000         LAYER MET3 ;
  ANTENNAPARTIALMETALAREA        0.94400         LAYER MET1 ;
  ANTENNAPARTIALMETALAREA        1.33320         LAYER MET2 ;
END Q[58]
PIN WEB[58]
  DIRECTION INPUT ;
  PORT
    LAYER MET1 ;
    RECT 273.140 0.000 273.550 0.180 ;
    LAYER MET2 ;
    RECT 273.140 0.000 273.550 0.180 ;
    LAYER MET3 ;
    RECT 273.140 0.000 273.550 0.180 ;
  END
  ANTENNADIFFAREA                0.45930         LAYER MET1 ;
  ANTENNADIFFAREA                0.45930         LAYER MET2 ;
  ANTENNADIFFAREA                0.45930         LAYER MET3 ;
  ANTENNAGATEAREA                0.08100         LAYER MET1 ;
  ANTENNAGATEAREA                0.08100         LAYER MET2 ;
  ANTENNAGATEAREA                0.08100         LAYER MET3 ;
  ANTENNAPARTIALMETALAREA        0.14210         LAYER MET1 ;
  ANTENNAPARTIALMETALAREA        0.09360         LAYER MET2 ;
  ANTENNAMAXAREACAR              1.09630         LAYER MET1 ;
  ANTENNAMAXAREACAR              3.16296         LAYER MET2 ;
  ANTENNAMAXAREACAR              4.07407         LAYER MET3 ;
END WEB[58]
PIN D[59]
  DIRECTION INPUT ;
  PORT
    LAYER MET1 ;
    RECT 279.690 0.000 280.100 0.180 ;
    LAYER MET2 ;
    RECT 279.690 0.000 280.100 0.180 ;
    LAYER MET3 ;
    RECT 279.690 0.000 280.100 0.180 ;
  END
  ANTENNADIFFAREA                0.38930         LAYER MET1 ;
  ANTENNADIFFAREA                0.38930         LAYER MET2 ;
  ANTENNADIFFAREA                0.38930         LAYER MET3 ;
  ANTENNAGATEAREA                0.06300         LAYER MET1 ;
  ANTENNAGATEAREA                0.06300         LAYER MET2 ;
  ANTENNAGATEAREA                0.06300         LAYER MET3 ;
  ANTENNAPARTIALMETALAREA        0.09890         LAYER MET1 ;
  ANTENNAPARTIALMETALAREA        0.10380         LAYER MET2 ;
  ANTENNAMAXAREACAR              0.72381         LAYER MET1 ;
  ANTENNAMAXAREACAR              3.54286         LAYER MET2 ;
  ANTENNAMAXAREACAR              4.71429         LAYER MET3 ;
END D[59]
PIN Q[59]
  DIRECTION OUTPUT ;
  PORT
    LAYER MET1 ;
    RECT 278.150 0.000 278.560 0.180 ;
    LAYER MET2 ;
    RECT 278.150 0.000 278.560 0.180 ;
    LAYER MET3 ;
    RECT 278.150 0.000 278.560 0.180 ;
  END
  ANTENNADIFFAREA                0.60000         LAYER MET1 ;
  ANTENNADIFFAREA                0.60000         LAYER MET2 ;
  ANTENNADIFFAREA                0.60000         LAYER MET3 ;
  ANTENNAPARTIALMETALAREA        0.94400         LAYER MET1 ;
  ANTENNAPARTIALMETALAREA        1.33320         LAYER MET2 ;
END Q[59]
PIN WEB[59]
  DIRECTION INPUT ;
  PORT
    LAYER MET1 ;
    RECT 277.340 0.000 277.750 0.180 ;
    LAYER MET2 ;
    RECT 277.340 0.000 277.750 0.180 ;
    LAYER MET3 ;
    RECT 277.340 0.000 277.750 0.180 ;
  END
  ANTENNADIFFAREA                0.45930         LAYER MET1 ;
  ANTENNADIFFAREA                0.45930         LAYER MET2 ;
  ANTENNADIFFAREA                0.45930         LAYER MET3 ;
  ANTENNAGATEAREA                0.08100         LAYER MET1 ;
  ANTENNAGATEAREA                0.08100         LAYER MET2 ;
  ANTENNAGATEAREA                0.08100         LAYER MET3 ;
  ANTENNAPARTIALMETALAREA        0.14210         LAYER MET1 ;
  ANTENNAPARTIALMETALAREA        0.09360         LAYER MET2 ;
  ANTENNAMAXAREACAR              1.09630         LAYER MET1 ;
  ANTENNAMAXAREACAR              3.16296         LAYER MET2 ;
  ANTENNAMAXAREACAR              4.07407         LAYER MET3 ;
END WEB[59]
PIN D[60]
  DIRECTION INPUT ;
  PORT
    LAYER MET1 ;
    RECT 283.890 0.000 284.300 0.180 ;
    LAYER MET2 ;
    RECT 283.890 0.000 284.300 0.180 ;
    LAYER MET3 ;
    RECT 283.890 0.000 284.300 0.180 ;
  END
  ANTENNADIFFAREA                0.38930         LAYER MET1 ;
  ANTENNADIFFAREA                0.38930         LAYER MET2 ;
  ANTENNADIFFAREA                0.38930         LAYER MET3 ;
  ANTENNAGATEAREA                0.06300         LAYER MET1 ;
  ANTENNAGATEAREA                0.06300         LAYER MET2 ;
  ANTENNAGATEAREA                0.06300         LAYER MET3 ;
  ANTENNAPARTIALMETALAREA        0.09890         LAYER MET1 ;
  ANTENNAPARTIALMETALAREA        0.10380         LAYER MET2 ;
  ANTENNAMAXAREACAR              0.72381         LAYER MET1 ;
  ANTENNAMAXAREACAR              3.54286         LAYER MET2 ;
  ANTENNAMAXAREACAR              4.71429         LAYER MET3 ;
END D[60]
PIN Q[60]
  DIRECTION OUTPUT ;
  PORT
    LAYER MET1 ;
    RECT 282.350 0.000 282.760 0.180 ;
    LAYER MET2 ;
    RECT 282.350 0.000 282.760 0.180 ;
    LAYER MET3 ;
    RECT 282.350 0.000 282.760 0.180 ;
  END
  ANTENNADIFFAREA                0.60000         LAYER MET1 ;
  ANTENNADIFFAREA                0.60000         LAYER MET2 ;
  ANTENNADIFFAREA                0.60000         LAYER MET3 ;
  ANTENNAPARTIALMETALAREA        0.94400         LAYER MET1 ;
  ANTENNAPARTIALMETALAREA        1.33320         LAYER MET2 ;
END Q[60]
PIN WEB[60]
  DIRECTION INPUT ;
  PORT
    LAYER MET1 ;
    RECT 281.540 0.000 281.950 0.180 ;
    LAYER MET2 ;
    RECT 281.540 0.000 281.950 0.180 ;
    LAYER MET3 ;
    RECT 281.540 0.000 281.950 0.180 ;
  END
  ANTENNADIFFAREA                0.45930         LAYER MET1 ;
  ANTENNADIFFAREA                0.45930         LAYER MET2 ;
  ANTENNADIFFAREA                0.45930         LAYER MET3 ;
  ANTENNAGATEAREA                0.08100         LAYER MET1 ;
  ANTENNAGATEAREA                0.08100         LAYER MET2 ;
  ANTENNAGATEAREA                0.08100         LAYER MET3 ;
  ANTENNAPARTIALMETALAREA        0.14210         LAYER MET1 ;
  ANTENNAPARTIALMETALAREA        0.09360         LAYER MET2 ;
  ANTENNAMAXAREACAR              1.09630         LAYER MET1 ;
  ANTENNAMAXAREACAR              3.16296         LAYER MET2 ;
  ANTENNAMAXAREACAR              4.07407         LAYER MET3 ;
END WEB[60]
PIN D[61]
  DIRECTION INPUT ;
  PORT
    LAYER MET1 ;
    RECT 288.090 0.000 288.500 0.180 ;
    LAYER MET2 ;
    RECT 288.090 0.000 288.500 0.180 ;
    LAYER MET3 ;
    RECT 288.090 0.000 288.500 0.180 ;
  END
  ANTENNADIFFAREA                0.38930         LAYER MET1 ;
  ANTENNADIFFAREA                0.38930         LAYER MET2 ;
  ANTENNADIFFAREA                0.38930         LAYER MET3 ;
  ANTENNAGATEAREA                0.06300         LAYER MET1 ;
  ANTENNAGATEAREA                0.06300         LAYER MET2 ;
  ANTENNAGATEAREA                0.06300         LAYER MET3 ;
  ANTENNAPARTIALMETALAREA        0.09890         LAYER MET1 ;
  ANTENNAPARTIALMETALAREA        0.10380         LAYER MET2 ;
  ANTENNAMAXAREACAR              0.72381         LAYER MET1 ;
  ANTENNAMAXAREACAR              3.54286         LAYER MET2 ;
  ANTENNAMAXAREACAR              4.71429         LAYER MET3 ;
END D[61]
PIN Q[61]
  DIRECTION OUTPUT ;
  PORT
    LAYER MET1 ;
    RECT 286.550 0.000 286.960 0.180 ;
    LAYER MET2 ;
    RECT 286.550 0.000 286.960 0.180 ;
    LAYER MET3 ;
    RECT 286.550 0.000 286.960 0.180 ;
  END
  ANTENNADIFFAREA                0.60000         LAYER MET1 ;
  ANTENNADIFFAREA                0.60000         LAYER MET2 ;
  ANTENNADIFFAREA                0.60000         LAYER MET3 ;
  ANTENNAPARTIALMETALAREA        0.94400         LAYER MET1 ;
  ANTENNAPARTIALMETALAREA        1.33320         LAYER MET2 ;
END Q[61]
PIN WEB[61]
  DIRECTION INPUT ;
  PORT
    LAYER MET1 ;
    RECT 285.740 0.000 286.150 0.180 ;
    LAYER MET2 ;
    RECT 285.740 0.000 286.150 0.180 ;
    LAYER MET3 ;
    RECT 285.740 0.000 286.150 0.180 ;
  END
  ANTENNADIFFAREA                0.45930         LAYER MET1 ;
  ANTENNADIFFAREA                0.45930         LAYER MET2 ;
  ANTENNADIFFAREA                0.45930         LAYER MET3 ;
  ANTENNAGATEAREA                0.08100         LAYER MET1 ;
  ANTENNAGATEAREA                0.08100         LAYER MET2 ;
  ANTENNAGATEAREA                0.08100         LAYER MET3 ;
  ANTENNAPARTIALMETALAREA        0.14210         LAYER MET1 ;
  ANTENNAPARTIALMETALAREA        0.09360         LAYER MET2 ;
  ANTENNAMAXAREACAR              1.09630         LAYER MET1 ;
  ANTENNAMAXAREACAR              3.16296         LAYER MET2 ;
  ANTENNAMAXAREACAR              4.07407         LAYER MET3 ;
END WEB[61]
PIN D[62]
  DIRECTION INPUT ;
  PORT
    LAYER MET1 ;
    RECT 292.290 0.000 292.700 0.180 ;
    LAYER MET2 ;
    RECT 292.290 0.000 292.700 0.180 ;
    LAYER MET3 ;
    RECT 292.290 0.000 292.700 0.180 ;
  END
  ANTENNADIFFAREA                0.38930         LAYER MET1 ;
  ANTENNADIFFAREA                0.38930         LAYER MET2 ;
  ANTENNADIFFAREA                0.38930         LAYER MET3 ;
  ANTENNAGATEAREA                0.06300         LAYER MET1 ;
  ANTENNAGATEAREA                0.06300         LAYER MET2 ;
  ANTENNAGATEAREA                0.06300         LAYER MET3 ;
  ANTENNAPARTIALMETALAREA        0.09890         LAYER MET1 ;
  ANTENNAPARTIALMETALAREA        0.10380         LAYER MET2 ;
  ANTENNAMAXAREACAR              0.72381         LAYER MET1 ;
  ANTENNAMAXAREACAR              3.54286         LAYER MET2 ;
  ANTENNAMAXAREACAR              4.71429         LAYER MET3 ;
END D[62]
PIN Q[62]
  DIRECTION OUTPUT ;
  PORT
    LAYER MET1 ;
    RECT 290.750 0.000 291.160 0.180 ;
    LAYER MET2 ;
    RECT 290.750 0.000 291.160 0.180 ;
    LAYER MET3 ;
    RECT 290.750 0.000 291.160 0.180 ;
  END
  ANTENNADIFFAREA                0.60000         LAYER MET1 ;
  ANTENNADIFFAREA                0.60000         LAYER MET2 ;
  ANTENNADIFFAREA                0.60000         LAYER MET3 ;
  ANTENNAPARTIALMETALAREA        0.94400         LAYER MET1 ;
  ANTENNAPARTIALMETALAREA        1.33320         LAYER MET2 ;
END Q[62]
PIN WEB[62]
  DIRECTION INPUT ;
  PORT
    LAYER MET1 ;
    RECT 289.940 0.000 290.350 0.180 ;
    LAYER MET2 ;
    RECT 289.940 0.000 290.350 0.180 ;
    LAYER MET3 ;
    RECT 289.940 0.000 290.350 0.180 ;
  END
  ANTENNADIFFAREA                0.45930         LAYER MET1 ;
  ANTENNADIFFAREA                0.45930         LAYER MET2 ;
  ANTENNADIFFAREA                0.45930         LAYER MET3 ;
  ANTENNAGATEAREA                0.08100         LAYER MET1 ;
  ANTENNAGATEAREA                0.08100         LAYER MET2 ;
  ANTENNAGATEAREA                0.08100         LAYER MET3 ;
  ANTENNAPARTIALMETALAREA        0.14210         LAYER MET1 ;
  ANTENNAPARTIALMETALAREA        0.09360         LAYER MET2 ;
  ANTENNAMAXAREACAR              1.09630         LAYER MET1 ;
  ANTENNAMAXAREACAR              3.16296         LAYER MET2 ;
  ANTENNAMAXAREACAR              4.07407         LAYER MET3 ;
END WEB[62]
PIN D[63]
  DIRECTION INPUT ;
  PORT
    LAYER MET1 ;
    RECT 296.490 0.000 296.900 0.180 ;
    LAYER MET2 ;
    RECT 296.490 0.000 296.900 0.180 ;
    LAYER MET3 ;
    RECT 296.490 0.000 296.900 0.180 ;
  END
  ANTENNADIFFAREA                0.38930         LAYER MET1 ;
  ANTENNADIFFAREA                0.38930         LAYER MET2 ;
  ANTENNADIFFAREA                0.38930         LAYER MET3 ;
  ANTENNAGATEAREA                0.06300         LAYER MET1 ;
  ANTENNAGATEAREA                0.06300         LAYER MET2 ;
  ANTENNAGATEAREA                0.06300         LAYER MET3 ;
  ANTENNAPARTIALMETALAREA        0.09890         LAYER MET1 ;
  ANTENNAPARTIALMETALAREA        0.10380         LAYER MET2 ;
  ANTENNAMAXAREACAR              0.72381         LAYER MET1 ;
  ANTENNAMAXAREACAR              3.54286         LAYER MET2 ;
  ANTENNAMAXAREACAR              4.71429         LAYER MET3 ;
END D[63]
PIN Q[63]
  DIRECTION OUTPUT ;
  PORT
    LAYER MET1 ;
    RECT 294.950 0.000 295.360 0.180 ;
    LAYER MET2 ;
    RECT 294.950 0.000 295.360 0.180 ;
    LAYER MET3 ;
    RECT 294.950 0.000 295.360 0.180 ;
  END
  ANTENNADIFFAREA                0.60000         LAYER MET1 ;
  ANTENNADIFFAREA                0.60000         LAYER MET2 ;
  ANTENNADIFFAREA                0.60000         LAYER MET3 ;
  ANTENNAPARTIALMETALAREA        0.94400         LAYER MET1 ;
  ANTENNAPARTIALMETALAREA        1.33320         LAYER MET2 ;
END Q[63]
PIN WEB[63]
  DIRECTION INPUT ;
  PORT
    LAYER MET1 ;
    RECT 294.140 0.000 294.550 0.180 ;
    LAYER MET2 ;
    RECT 294.140 0.000 294.550 0.180 ;
    LAYER MET3 ;
    RECT 294.140 0.000 294.550 0.180 ;
  END
  ANTENNADIFFAREA                0.45930         LAYER MET1 ;
  ANTENNADIFFAREA                0.45930         LAYER MET2 ;
  ANTENNADIFFAREA                0.45930         LAYER MET3 ;
  ANTENNAGATEAREA                0.08100         LAYER MET1 ;
  ANTENNAGATEAREA                0.08100         LAYER MET2 ;
  ANTENNAGATEAREA                0.08100         LAYER MET3 ;
  ANTENNAPARTIALMETALAREA        0.14210         LAYER MET1 ;
  ANTENNAPARTIALMETALAREA        0.09360         LAYER MET2 ;
  ANTENNAMAXAREACAR              1.09630         LAYER MET1 ;
  ANTENNAMAXAREACAR              3.16296         LAYER MET2 ;
  ANTENNAMAXAREACAR              4.07407         LAYER MET3 ;
END WEB[63]
OBS
  LAYER MET1 SPACING 0.090 ;
    POLYGON 298.830 0.000 298.830 58.535 
            0.000 58.535 0.000 0.000 
            2.190 0.000 2.190 0.180 
            2.600 0.180 2.600 0.000 
            3.000 0.000 3.000 0.180 
            3.410 0.180 3.410 0.000 
            4.540 0.000 4.540 0.180 
            4.950 0.180 4.950 0.000 
            6.390 0.000 6.390 0.180 
            6.800 0.180 6.800 0.000 
            7.200 0.000 7.200 0.180 
            7.610 0.180 7.610 0.000 
            8.740 0.000 8.740 0.180 
            9.150 0.180 9.150 0.000 
            10.590 0.000 10.590 0.180 
            11.000 0.180 11.000 0.000 
            11.400 0.000 11.400 0.180 
            11.810 0.180 11.810 0.000 
            12.940 0.000 12.940 0.180 
            13.350 0.180 13.350 0.000 
            14.790 0.000 14.790 0.180 
            15.200 0.180 15.200 0.000 
            15.600 0.000 15.600 0.180 
            16.010 0.180 16.010 0.000 
            17.140 0.000 17.140 0.180 
            17.550 0.180 17.550 0.000 
            18.990 0.000 18.990 0.180 
            19.400 0.180 19.400 0.000 
            19.800 0.000 19.800 0.180 
            20.210 0.180 20.210 0.000 
            21.340 0.000 21.340 0.180 
            21.750 0.180 21.750 0.000 
            23.190 0.000 23.190 0.180 
            23.600 0.180 23.600 0.000 
            24.000 0.000 24.000 0.180 
            24.410 0.180 24.410 0.000 
            25.540 0.000 25.540 0.180 
            25.950 0.180 25.950 0.000 
            27.390 0.000 27.390 0.180 
            27.800 0.180 27.800 0.000 
            28.200 0.000 28.200 0.180 
            28.610 0.180 28.610 0.000 
            29.740 0.000 29.740 0.180 
            30.150 0.180 30.150 0.000 
            31.590 0.000 31.590 0.180 
            32.000 0.180 32.000 0.000 
            32.400 0.000 32.400 0.180 
            32.810 0.180 32.810 0.000 
            33.940 0.000 33.940 0.180 
            34.350 0.180 34.350 0.000 
            35.790 0.000 35.790 0.180 
            36.200 0.180 36.200 0.000 
            36.600 0.000 36.600 0.180 
            37.010 0.180 37.010 0.000 
            38.140 0.000 38.140 0.180 
            38.550 0.180 38.550 0.000 
            39.990 0.000 39.990 0.180 
            40.400 0.180 40.400 0.000 
            40.800 0.000 40.800 0.180 
            41.210 0.180 41.210 0.000 
            42.340 0.000 42.340 0.180 
            42.750 0.180 42.750 0.000 
            44.190 0.000 44.190 0.180 
            44.600 0.180 44.600 0.000 
            45.000 0.000 45.000 0.180 
            45.410 0.180 45.410 0.000 
            46.540 0.000 46.540 0.180 
            46.950 0.180 46.950 0.000 
            48.390 0.000 48.390 0.180 
            48.800 0.180 48.800 0.000 
            49.200 0.000 49.200 0.180 
            49.610 0.180 49.610 0.000 
            50.740 0.000 50.740 0.180 
            51.150 0.180 51.150 0.000 
            52.590 0.000 52.590 0.180 
            53.000 0.180 53.000 0.000 
            53.400 0.000 53.400 0.180 
            53.810 0.180 53.810 0.000 
            54.940 0.000 54.940 0.180 
            55.350 0.180 55.350 0.000 
            56.790 0.000 56.790 0.180 
            57.200 0.180 57.200 0.000 
            57.600 0.000 57.600 0.180 
            58.010 0.180 58.010 0.000 
            59.140 0.000 59.140 0.180 
            59.550 0.180 59.550 0.000 
            60.990 0.000 60.990 0.180 
            61.400 0.180 61.400 0.000 
            61.800 0.000 61.800 0.180 
            62.210 0.180 62.210 0.000 
            63.340 0.000 63.340 0.180 
            63.750 0.180 63.750 0.000 
            65.190 0.000 65.190 0.180 
            65.600 0.180 65.600 0.000 
            66.000 0.000 66.000 0.180 
            66.410 0.180 66.410 0.000 
            67.540 0.000 67.540 0.180 
            67.950 0.180 67.950 0.000 
            69.390 0.000 69.390 0.180 
            69.800 0.180 69.800 0.000 
            70.200 0.000 70.200 0.180 
            70.610 0.180 70.610 0.000 
            71.740 0.000 71.740 0.180 
            72.150 0.180 72.150 0.000 
            73.590 0.000 73.590 0.180 
            74.000 0.180 74.000 0.000 
            74.400 0.000 74.400 0.180 
            74.810 0.180 74.810 0.000 
            75.940 0.000 75.940 0.180 
            76.350 0.180 76.350 0.000 
            77.790 0.000 77.790 0.180 
            78.200 0.180 78.200 0.000 
            78.600 0.000 78.600 0.180 
            79.010 0.180 79.010 0.000 
            80.140 0.000 80.140 0.180 
            80.550 0.180 80.550 0.000 
            81.990 0.000 81.990 0.180 
            82.400 0.180 82.400 0.000 
            82.800 0.000 82.800 0.180 
            83.210 0.180 83.210 0.000 
            84.340 0.000 84.340 0.180 
            84.750 0.180 84.750 0.000 
            86.190 0.000 86.190 0.180 
            86.600 0.180 86.600 0.000 
            87.000 0.000 87.000 0.180 
            87.410 0.180 87.410 0.000 
            88.540 0.000 88.540 0.180 
            88.950 0.180 88.950 0.000 
            90.390 0.000 90.390 0.180 
            90.800 0.180 90.800 0.000 
            91.200 0.000 91.200 0.180 
            91.610 0.180 91.610 0.000 
            92.740 0.000 92.740 0.180 
            93.150 0.180 93.150 0.000 
            94.590 0.000 94.590 0.180 
            95.000 0.180 95.000 0.000 
            95.400 0.000 95.400 0.180 
            95.810 0.180 95.810 0.000 
            96.940 0.000 96.940 0.180 
            97.350 0.180 97.350 0.000 
            98.790 0.000 98.790 0.180 
            99.200 0.180 99.200 0.000 
            99.600 0.000 99.600 0.180 
            100.010 0.180 100.010 0.000 
            101.140 0.000 101.140 0.180 
            101.550 0.180 101.550 0.000 
            102.990 0.000 102.990 0.180 
            103.400 0.180 103.400 0.000 
            103.800 0.000 103.800 0.180 
            104.210 0.180 104.210 0.000 
            105.340 0.000 105.340 0.180 
            105.750 0.180 105.750 0.000 
            107.190 0.000 107.190 0.180 
            107.600 0.180 107.600 0.000 
            108.000 0.000 108.000 0.180 
            108.410 0.180 108.410 0.000 
            109.540 0.000 109.540 0.180 
            109.950 0.180 109.950 0.000 
            111.390 0.000 111.390 0.180 
            111.800 0.180 111.800 0.000 
            112.200 0.000 112.200 0.180 
            112.610 0.180 112.610 0.000 
            113.740 0.000 113.740 0.180 
            114.150 0.180 114.150 0.000 
            115.590 0.000 115.590 0.180 
            116.000 0.180 116.000 0.000 
            116.400 0.000 116.400 0.180 
            116.810 0.180 116.810 0.000 
            117.940 0.000 117.940 0.180 
            118.350 0.180 118.350 0.000 
            119.790 0.000 119.790 0.180 
            120.200 0.180 120.200 0.000 
            120.600 0.000 120.600 0.180 
            121.010 0.180 121.010 0.000 
            122.140 0.000 122.140 0.180 
            122.550 0.180 122.550 0.000 
            123.990 0.000 123.990 0.180 
            124.400 0.180 124.400 0.000 
            124.800 0.000 124.800 0.180 
            125.210 0.180 125.210 0.000 
            126.340 0.000 126.340 0.180 
            126.750 0.180 126.750 0.000 
            128.190 0.000 128.190 0.180 
            128.600 0.180 128.600 0.000 
            129.000 0.000 129.000 0.180 
            129.410 0.180 129.410 0.000 
            130.540 0.000 130.540 0.180 
            130.950 0.180 130.950 0.000 
            132.390 0.000 132.390 0.180 
            132.800 0.180 132.800 0.000 
            133.200 0.000 133.200 0.180 
            133.610 0.180 133.610 0.000 
            134.740 0.000 134.740 0.180 
            135.150 0.180 135.150 0.000 
            140.150 0.000 140.150 0.180 
            140.560 0.180 140.560 0.000 
            140.680 0.000 140.680 0.180 
            141.090 0.180 141.090 0.000 
            141.500 0.000 141.500 0.180 
            141.910 0.180 141.910 0.000 
            142.080 0.000 142.080 0.180 
            142.490 0.180 142.490 0.000 
            143.140 0.000 143.140 0.180 
            143.550 0.180 143.550 0.000 
            143.685 0.000 143.685 0.180 
            144.095 0.180 144.095 0.000 
            144.215 0.000 144.215 0.180 
            144.625 0.180 144.625 0.000 
            144.745 0.000 144.745 0.180 
            145.155 0.180 145.155 0.000 
            145.275 0.000 145.275 0.180 
            145.685 0.180 145.685 0.000 
            145.805 0.000 145.805 0.180 
            146.215 0.180 146.215 0.000 
            146.465 0.000 146.465 0.180 
            146.875 0.180 146.875 0.000 
            147.590 0.000 147.590 0.180 
            148.000 0.180 148.000 0.000 
            155.210 0.000 155.210 0.180 
            155.620 0.180 155.620 0.000 
            155.900 0.000 155.900 0.180 
            156.310 0.180 156.310 0.000 
            158.875 0.000 158.875 0.180 
            159.285 0.180 159.285 0.000 
            159.590 0.000 159.590 0.180 
            160.000 0.180 160.000 0.000 
            163.940 0.000 163.940 0.180 
            164.350 0.180 164.350 0.000 
            164.750 0.000 164.750 0.180 
            165.160 0.180 165.160 0.000 
            166.290 0.000 166.290 0.180 
            166.700 0.180 166.700 0.000 
            168.140 0.000 168.140 0.180 
            168.550 0.180 168.550 0.000 
            168.950 0.000 168.950 0.180 
            169.360 0.180 169.360 0.000 
            170.490 0.000 170.490 0.180 
            170.900 0.180 170.900 0.000 
            172.340 0.000 172.340 0.180 
            172.750 0.180 172.750 0.000 
            173.150 0.000 173.150 0.180 
            173.560 0.180 173.560 0.000 
            174.690 0.000 174.690 0.180 
            175.100 0.180 175.100 0.000 
            176.540 0.000 176.540 0.180 
            176.950 0.180 176.950 0.000 
            177.350 0.000 177.350 0.180 
            177.760 0.180 177.760 0.000 
            178.890 0.000 178.890 0.180 
            179.300 0.180 179.300 0.000 
            180.740 0.000 180.740 0.180 
            181.150 0.180 181.150 0.000 
            181.550 0.000 181.550 0.180 
            181.960 0.180 181.960 0.000 
            183.090 0.000 183.090 0.180 
            183.500 0.180 183.500 0.000 
            184.940 0.000 184.940 0.180 
            185.350 0.180 185.350 0.000 
            185.750 0.000 185.750 0.180 
            186.160 0.180 186.160 0.000 
            187.290 0.000 187.290 0.180 
            187.700 0.180 187.700 0.000 
            189.140 0.000 189.140 0.180 
            189.550 0.180 189.550 0.000 
            189.950 0.000 189.950 0.180 
            190.360 0.180 190.360 0.000 
            191.490 0.000 191.490 0.180 
            191.900 0.180 191.900 0.000 
            193.340 0.000 193.340 0.180 
            193.750 0.180 193.750 0.000 
            194.150 0.000 194.150 0.180 
            194.560 0.180 194.560 0.000 
            195.690 0.000 195.690 0.180 
            196.100 0.180 196.100 0.000 
            197.540 0.000 197.540 0.180 
            197.950 0.180 197.950 0.000 
            198.350 0.000 198.350 0.180 
            198.760 0.180 198.760 0.000 
            199.890 0.000 199.890 0.180 
            200.300 0.180 200.300 0.000 
            201.740 0.000 201.740 0.180 
            202.150 0.180 202.150 0.000 
            202.550 0.000 202.550 0.180 
            202.960 0.180 202.960 0.000 
            204.090 0.000 204.090 0.180 
            204.500 0.180 204.500 0.000 
            205.940 0.000 205.940 0.180 
            206.350 0.180 206.350 0.000 
            206.750 0.000 206.750 0.180 
            207.160 0.180 207.160 0.000 
            208.290 0.000 208.290 0.180 
            208.700 0.180 208.700 0.000 
            210.140 0.000 210.140 0.180 
            210.550 0.180 210.550 0.000 
            210.950 0.000 210.950 0.180 
            211.360 0.180 211.360 0.000 
            212.490 0.000 212.490 0.180 
            212.900 0.180 212.900 0.000 
            214.340 0.000 214.340 0.180 
            214.750 0.180 214.750 0.000 
            215.150 0.000 215.150 0.180 
            215.560 0.180 215.560 0.000 
            216.690 0.000 216.690 0.180 
            217.100 0.180 217.100 0.000 
            218.540 0.000 218.540 0.180 
            218.950 0.180 218.950 0.000 
            219.350 0.000 219.350 0.180 
            219.760 0.180 219.760 0.000 
            220.890 0.000 220.890 0.180 
            221.300 0.180 221.300 0.000 
            222.740 0.000 222.740 0.180 
            223.150 0.180 223.150 0.000 
            223.550 0.000 223.550 0.180 
            223.960 0.180 223.960 0.000 
            225.090 0.000 225.090 0.180 
            225.500 0.180 225.500 0.000 
            226.940 0.000 226.940 0.180 
            227.350 0.180 227.350 0.000 
            227.750 0.000 227.750 0.180 
            228.160 0.180 228.160 0.000 
            229.290 0.000 229.290 0.180 
            229.700 0.180 229.700 0.000 
            231.140 0.000 231.140 0.180 
            231.550 0.180 231.550 0.000 
            231.950 0.000 231.950 0.180 
            232.360 0.180 232.360 0.000 
            233.490 0.000 233.490 0.180 
            233.900 0.180 233.900 0.000 
            235.340 0.000 235.340 0.180 
            235.750 0.180 235.750 0.000 
            236.150 0.000 236.150 0.180 
            236.560 0.180 236.560 0.000 
            237.690 0.000 237.690 0.180 
            238.100 0.180 238.100 0.000 
            239.540 0.000 239.540 0.180 
            239.950 0.180 239.950 0.000 
            240.350 0.000 240.350 0.180 
            240.760 0.180 240.760 0.000 
            241.890 0.000 241.890 0.180 
            242.300 0.180 242.300 0.000 
            243.740 0.000 243.740 0.180 
            244.150 0.180 244.150 0.000 
            244.550 0.000 244.550 0.180 
            244.960 0.180 244.960 0.000 
            246.090 0.000 246.090 0.180 
            246.500 0.180 246.500 0.000 
            247.940 0.000 247.940 0.180 
            248.350 0.180 248.350 0.000 
            248.750 0.000 248.750 0.180 
            249.160 0.180 249.160 0.000 
            250.290 0.000 250.290 0.180 
            250.700 0.180 250.700 0.000 
            252.140 0.000 252.140 0.180 
            252.550 0.180 252.550 0.000 
            252.950 0.000 252.950 0.180 
            253.360 0.180 253.360 0.000 
            254.490 0.000 254.490 0.180 
            254.900 0.180 254.900 0.000 
            256.340 0.000 256.340 0.180 
            256.750 0.180 256.750 0.000 
            257.150 0.000 257.150 0.180 
            257.560 0.180 257.560 0.000 
            258.690 0.000 258.690 0.180 
            259.100 0.180 259.100 0.000 
            260.540 0.000 260.540 0.180 
            260.950 0.180 260.950 0.000 
            261.350 0.000 261.350 0.180 
            261.760 0.180 261.760 0.000 
            262.890 0.000 262.890 0.180 
            263.300 0.180 263.300 0.000 
            264.740 0.000 264.740 0.180 
            265.150 0.180 265.150 0.000 
            265.550 0.000 265.550 0.180 
            265.960 0.180 265.960 0.000 
            267.090 0.000 267.090 0.180 
            267.500 0.180 267.500 0.000 
            268.940 0.000 268.940 0.180 
            269.350 0.180 269.350 0.000 
            269.750 0.000 269.750 0.180 
            270.160 0.180 270.160 0.000 
            271.290 0.000 271.290 0.180 
            271.700 0.180 271.700 0.000 
            273.140 0.000 273.140 0.180 
            273.550 0.180 273.550 0.000 
            273.950 0.000 273.950 0.180 
            274.360 0.180 274.360 0.000 
            275.490 0.000 275.490 0.180 
            275.900 0.180 275.900 0.000 
            277.340 0.000 277.340 0.180 
            277.750 0.180 277.750 0.000 
            278.150 0.000 278.150 0.180 
            278.560 0.180 278.560 0.000 
            279.690 0.000 279.690 0.180 
            280.100 0.180 280.100 0.000 
            281.540 0.000 281.540 0.180 
            281.950 0.180 281.950 0.000 
            282.350 0.000 282.350 0.180 
            282.760 0.180 282.760 0.000 
            283.890 0.000 283.890 0.180 
            284.300 0.180 284.300 0.000 
            285.740 0.000 285.740 0.180 
            286.150 0.180 286.150 0.000 
            286.550 0.000 286.550 0.180 
            286.960 0.180 286.960 0.000 
            288.090 0.000 288.090 0.180 
            288.500 0.180 288.500 0.000 
            289.940 0.000 289.940 0.180 
            290.350 0.180 290.350 0.000 
            290.750 0.000 290.750 0.180 
            291.160 0.180 291.160 0.000 
            292.290 0.000 292.290 0.180 
            292.700 0.180 292.700 0.000 
            294.140 0.000 294.140 0.180 
            294.550 0.180 294.550 0.000 
            294.950 0.000 294.950 0.180 
            295.360 0.180 295.360 0.000 
            296.490 0.000 296.490 0.180 
            296.900 0.180 296.900 0.000 
            298.830 0.000 ;
  LAYER VIA1 SPACING 0.110 ;
    RECT 0.000 0.000 298.830 58.535 ;
  LAYER MET2 SPACING 0.100 ;
    POLYGON 298.830 0.000 298.830 58.535 
            0.000 58.535 0.000 0.000 
            2.190 0.000 2.190 0.180 
            2.600 0.180 2.600 0.000 
            3.000 0.000 3.000 0.180 
            3.410 0.180 3.410 0.000 
            4.540 0.000 4.540 0.180 
            4.950 0.180 4.950 0.000 
            6.390 0.000 6.390 0.180 
            6.800 0.180 6.800 0.000 
            7.200 0.000 7.200 0.180 
            7.610 0.180 7.610 0.000 
            8.740 0.000 8.740 0.180 
            9.150 0.180 9.150 0.000 
            10.590 0.000 10.590 0.180 
            11.000 0.180 11.000 0.000 
            11.400 0.000 11.400 0.180 
            11.810 0.180 11.810 0.000 
            12.940 0.000 12.940 0.180 
            13.350 0.180 13.350 0.000 
            14.790 0.000 14.790 0.180 
            15.200 0.180 15.200 0.000 
            15.600 0.000 15.600 0.180 
            16.010 0.180 16.010 0.000 
            17.140 0.000 17.140 0.180 
            17.550 0.180 17.550 0.000 
            18.990 0.000 18.990 0.180 
            19.400 0.180 19.400 0.000 
            19.800 0.000 19.800 0.180 
            20.210 0.180 20.210 0.000 
            21.340 0.000 21.340 0.180 
            21.750 0.180 21.750 0.000 
            23.190 0.000 23.190 0.180 
            23.600 0.180 23.600 0.000 
            24.000 0.000 24.000 0.180 
            24.410 0.180 24.410 0.000 
            25.540 0.000 25.540 0.180 
            25.950 0.180 25.950 0.000 
            27.390 0.000 27.390 0.180 
            27.800 0.180 27.800 0.000 
            28.200 0.000 28.200 0.180 
            28.610 0.180 28.610 0.000 
            29.740 0.000 29.740 0.180 
            30.150 0.180 30.150 0.000 
            31.590 0.000 31.590 0.180 
            32.000 0.180 32.000 0.000 
            32.400 0.000 32.400 0.180 
            32.810 0.180 32.810 0.000 
            33.940 0.000 33.940 0.180 
            34.350 0.180 34.350 0.000 
            35.790 0.000 35.790 0.180 
            36.200 0.180 36.200 0.000 
            36.600 0.000 36.600 0.180 
            37.010 0.180 37.010 0.000 
            38.140 0.000 38.140 0.180 
            38.550 0.180 38.550 0.000 
            39.990 0.000 39.990 0.180 
            40.400 0.180 40.400 0.000 
            40.800 0.000 40.800 0.180 
            41.210 0.180 41.210 0.000 
            42.340 0.000 42.340 0.180 
            42.750 0.180 42.750 0.000 
            44.190 0.000 44.190 0.180 
            44.600 0.180 44.600 0.000 
            45.000 0.000 45.000 0.180 
            45.410 0.180 45.410 0.000 
            46.540 0.000 46.540 0.180 
            46.950 0.180 46.950 0.000 
            48.390 0.000 48.390 0.180 
            48.800 0.180 48.800 0.000 
            49.200 0.000 49.200 0.180 
            49.610 0.180 49.610 0.000 
            50.740 0.000 50.740 0.180 
            51.150 0.180 51.150 0.000 
            52.590 0.000 52.590 0.180 
            53.000 0.180 53.000 0.000 
            53.400 0.000 53.400 0.180 
            53.810 0.180 53.810 0.000 
            54.940 0.000 54.940 0.180 
            55.350 0.180 55.350 0.000 
            56.790 0.000 56.790 0.180 
            57.200 0.180 57.200 0.000 
            57.600 0.000 57.600 0.180 
            58.010 0.180 58.010 0.000 
            59.140 0.000 59.140 0.180 
            59.550 0.180 59.550 0.000 
            60.990 0.000 60.990 0.180 
            61.400 0.180 61.400 0.000 
            61.800 0.000 61.800 0.180 
            62.210 0.180 62.210 0.000 
            63.340 0.000 63.340 0.180 
            63.750 0.180 63.750 0.000 
            65.190 0.000 65.190 0.180 
            65.600 0.180 65.600 0.000 
            66.000 0.000 66.000 0.180 
            66.410 0.180 66.410 0.000 
            67.540 0.000 67.540 0.180 
            67.950 0.180 67.950 0.000 
            69.390 0.000 69.390 0.180 
            69.800 0.180 69.800 0.000 
            70.200 0.000 70.200 0.180 
            70.610 0.180 70.610 0.000 
            71.740 0.000 71.740 0.180 
            72.150 0.180 72.150 0.000 
            73.590 0.000 73.590 0.180 
            74.000 0.180 74.000 0.000 
            74.400 0.000 74.400 0.180 
            74.810 0.180 74.810 0.000 
            75.940 0.000 75.940 0.180 
            76.350 0.180 76.350 0.000 
            77.790 0.000 77.790 0.180 
            78.200 0.180 78.200 0.000 
            78.600 0.000 78.600 0.180 
            79.010 0.180 79.010 0.000 
            80.140 0.000 80.140 0.180 
            80.550 0.180 80.550 0.000 
            81.990 0.000 81.990 0.180 
            82.400 0.180 82.400 0.000 
            82.800 0.000 82.800 0.180 
            83.210 0.180 83.210 0.000 
            84.340 0.000 84.340 0.180 
            84.750 0.180 84.750 0.000 
            86.190 0.000 86.190 0.180 
            86.600 0.180 86.600 0.000 
            87.000 0.000 87.000 0.180 
            87.410 0.180 87.410 0.000 
            88.540 0.000 88.540 0.180 
            88.950 0.180 88.950 0.000 
            90.390 0.000 90.390 0.180 
            90.800 0.180 90.800 0.000 
            91.200 0.000 91.200 0.180 
            91.610 0.180 91.610 0.000 
            92.740 0.000 92.740 0.180 
            93.150 0.180 93.150 0.000 
            94.590 0.000 94.590 0.180 
            95.000 0.180 95.000 0.000 
            95.400 0.000 95.400 0.180 
            95.810 0.180 95.810 0.000 
            96.940 0.000 96.940 0.180 
            97.350 0.180 97.350 0.000 
            98.790 0.000 98.790 0.180 
            99.200 0.180 99.200 0.000 
            99.600 0.000 99.600 0.180 
            100.010 0.180 100.010 0.000 
            101.140 0.000 101.140 0.180 
            101.550 0.180 101.550 0.000 
            102.990 0.000 102.990 0.180 
            103.400 0.180 103.400 0.000 
            103.800 0.000 103.800 0.180 
            104.210 0.180 104.210 0.000 
            105.340 0.000 105.340 0.180 
            105.750 0.180 105.750 0.000 
            107.190 0.000 107.190 0.180 
            107.600 0.180 107.600 0.000 
            108.000 0.000 108.000 0.180 
            108.410 0.180 108.410 0.000 
            109.540 0.000 109.540 0.180 
            109.950 0.180 109.950 0.000 
            111.390 0.000 111.390 0.180 
            111.800 0.180 111.800 0.000 
            112.200 0.000 112.200 0.180 
            112.610 0.180 112.610 0.000 
            113.740 0.000 113.740 0.180 
            114.150 0.180 114.150 0.000 
            115.590 0.000 115.590 0.180 
            116.000 0.180 116.000 0.000 
            116.400 0.000 116.400 0.180 
            116.810 0.180 116.810 0.000 
            117.940 0.000 117.940 0.180 
            118.350 0.180 118.350 0.000 
            119.790 0.000 119.790 0.180 
            120.200 0.180 120.200 0.000 
            120.600 0.000 120.600 0.180 
            121.010 0.180 121.010 0.000 
            122.140 0.000 122.140 0.180 
            122.550 0.180 122.550 0.000 
            123.990 0.000 123.990 0.180 
            124.400 0.180 124.400 0.000 
            124.800 0.000 124.800 0.180 
            125.210 0.180 125.210 0.000 
            126.340 0.000 126.340 0.180 
            126.750 0.180 126.750 0.000 
            128.190 0.000 128.190 0.180 
            128.600 0.180 128.600 0.000 
            129.000 0.000 129.000 0.180 
            129.410 0.180 129.410 0.000 
            130.540 0.000 130.540 0.180 
            130.950 0.180 130.950 0.000 
            132.390 0.000 132.390 0.180 
            132.800 0.180 132.800 0.000 
            133.200 0.000 133.200 0.180 
            133.610 0.180 133.610 0.000 
            134.740 0.000 134.740 0.180 
            135.150 0.180 135.150 0.000 
            140.150 0.000 140.150 0.180 
            140.560 0.180 140.560 0.000 
            140.680 0.000 140.680 0.180 
            141.090 0.180 141.090 0.000 
            141.500 0.000 141.500 0.180 
            141.910 0.180 141.910 0.000 
            142.080 0.000 142.080 0.180 
            142.490 0.180 142.490 0.000 
            143.140 0.000 143.140 0.180 
            143.550 0.180 143.550 0.000 
            143.685 0.000 143.685 0.180 
            144.095 0.180 144.095 0.000 
            144.215 0.000 144.215 0.180 
            144.625 0.180 144.625 0.000 
            144.745 0.000 144.745 0.180 
            145.155 0.180 145.155 0.000 
            145.275 0.000 145.275 0.180 
            145.685 0.180 145.685 0.000 
            145.805 0.000 145.805 0.180 
            146.215 0.180 146.215 0.000 
            146.465 0.000 146.465 0.180 
            146.875 0.180 146.875 0.000 
            147.590 0.000 147.590 0.180 
            148.000 0.180 148.000 0.000 
            155.210 0.000 155.210 0.180 
            155.620 0.180 155.620 0.000 
            155.900 0.000 155.900 0.180 
            156.310 0.180 156.310 0.000 
            158.875 0.000 158.875 0.180 
            159.285 0.180 159.285 0.000 
            159.590 0.000 159.590 0.180 
            160.000 0.180 160.000 0.000 
            163.940 0.000 163.940 0.180 
            164.350 0.180 164.350 0.000 
            164.750 0.000 164.750 0.180 
            165.160 0.180 165.160 0.000 
            166.290 0.000 166.290 0.180 
            166.700 0.180 166.700 0.000 
            168.140 0.000 168.140 0.180 
            168.550 0.180 168.550 0.000 
            168.950 0.000 168.950 0.180 
            169.360 0.180 169.360 0.000 
            170.490 0.000 170.490 0.180 
            170.900 0.180 170.900 0.000 
            172.340 0.000 172.340 0.180 
            172.750 0.180 172.750 0.000 
            173.150 0.000 173.150 0.180 
            173.560 0.180 173.560 0.000 
            174.690 0.000 174.690 0.180 
            175.100 0.180 175.100 0.000 
            176.540 0.000 176.540 0.180 
            176.950 0.180 176.950 0.000 
            177.350 0.000 177.350 0.180 
            177.760 0.180 177.760 0.000 
            178.890 0.000 178.890 0.180 
            179.300 0.180 179.300 0.000 
            180.740 0.000 180.740 0.180 
            181.150 0.180 181.150 0.000 
            181.550 0.000 181.550 0.180 
            181.960 0.180 181.960 0.000 
            183.090 0.000 183.090 0.180 
            183.500 0.180 183.500 0.000 
            184.940 0.000 184.940 0.180 
            185.350 0.180 185.350 0.000 
            185.750 0.000 185.750 0.180 
            186.160 0.180 186.160 0.000 
            187.290 0.000 187.290 0.180 
            187.700 0.180 187.700 0.000 
            189.140 0.000 189.140 0.180 
            189.550 0.180 189.550 0.000 
            189.950 0.000 189.950 0.180 
            190.360 0.180 190.360 0.000 
            191.490 0.000 191.490 0.180 
            191.900 0.180 191.900 0.000 
            193.340 0.000 193.340 0.180 
            193.750 0.180 193.750 0.000 
            194.150 0.000 194.150 0.180 
            194.560 0.180 194.560 0.000 
            195.690 0.000 195.690 0.180 
            196.100 0.180 196.100 0.000 
            197.540 0.000 197.540 0.180 
            197.950 0.180 197.950 0.000 
            198.350 0.000 198.350 0.180 
            198.760 0.180 198.760 0.000 
            199.890 0.000 199.890 0.180 
            200.300 0.180 200.300 0.000 
            201.740 0.000 201.740 0.180 
            202.150 0.180 202.150 0.000 
            202.550 0.000 202.550 0.180 
            202.960 0.180 202.960 0.000 
            204.090 0.000 204.090 0.180 
            204.500 0.180 204.500 0.000 
            205.940 0.000 205.940 0.180 
            206.350 0.180 206.350 0.000 
            206.750 0.000 206.750 0.180 
            207.160 0.180 207.160 0.000 
            208.290 0.000 208.290 0.180 
            208.700 0.180 208.700 0.000 
            210.140 0.000 210.140 0.180 
            210.550 0.180 210.550 0.000 
            210.950 0.000 210.950 0.180 
            211.360 0.180 211.360 0.000 
            212.490 0.000 212.490 0.180 
            212.900 0.180 212.900 0.000 
            214.340 0.000 214.340 0.180 
            214.750 0.180 214.750 0.000 
            215.150 0.000 215.150 0.180 
            215.560 0.180 215.560 0.000 
            216.690 0.000 216.690 0.180 
            217.100 0.180 217.100 0.000 
            218.540 0.000 218.540 0.180 
            218.950 0.180 218.950 0.000 
            219.350 0.000 219.350 0.180 
            219.760 0.180 219.760 0.000 
            220.890 0.000 220.890 0.180 
            221.300 0.180 221.300 0.000 
            222.740 0.000 222.740 0.180 
            223.150 0.180 223.150 0.000 
            223.550 0.000 223.550 0.180 
            223.960 0.180 223.960 0.000 
            225.090 0.000 225.090 0.180 
            225.500 0.180 225.500 0.000 
            226.940 0.000 226.940 0.180 
            227.350 0.180 227.350 0.000 
            227.750 0.000 227.750 0.180 
            228.160 0.180 228.160 0.000 
            229.290 0.000 229.290 0.180 
            229.700 0.180 229.700 0.000 
            231.140 0.000 231.140 0.180 
            231.550 0.180 231.550 0.000 
            231.950 0.000 231.950 0.180 
            232.360 0.180 232.360 0.000 
            233.490 0.000 233.490 0.180 
            233.900 0.180 233.900 0.000 
            235.340 0.000 235.340 0.180 
            235.750 0.180 235.750 0.000 
            236.150 0.000 236.150 0.180 
            236.560 0.180 236.560 0.000 
            237.690 0.000 237.690 0.180 
            238.100 0.180 238.100 0.000 
            239.540 0.000 239.540 0.180 
            239.950 0.180 239.950 0.000 
            240.350 0.000 240.350 0.180 
            240.760 0.180 240.760 0.000 
            241.890 0.000 241.890 0.180 
            242.300 0.180 242.300 0.000 
            243.740 0.000 243.740 0.180 
            244.150 0.180 244.150 0.000 
            244.550 0.000 244.550 0.180 
            244.960 0.180 244.960 0.000 
            246.090 0.000 246.090 0.180 
            246.500 0.180 246.500 0.000 
            247.940 0.000 247.940 0.180 
            248.350 0.180 248.350 0.000 
            248.750 0.000 248.750 0.180 
            249.160 0.180 249.160 0.000 
            250.290 0.000 250.290 0.180 
            250.700 0.180 250.700 0.000 
            252.140 0.000 252.140 0.180 
            252.550 0.180 252.550 0.000 
            252.950 0.000 252.950 0.180 
            253.360 0.180 253.360 0.000 
            254.490 0.000 254.490 0.180 
            254.900 0.180 254.900 0.000 
            256.340 0.000 256.340 0.180 
            256.750 0.180 256.750 0.000 
            257.150 0.000 257.150 0.180 
            257.560 0.180 257.560 0.000 
            258.690 0.000 258.690 0.180 
            259.100 0.180 259.100 0.000 
            260.540 0.000 260.540 0.180 
            260.950 0.180 260.950 0.000 
            261.350 0.000 261.350 0.180 
            261.760 0.180 261.760 0.000 
            262.890 0.000 262.890 0.180 
            263.300 0.180 263.300 0.000 
            264.740 0.000 264.740 0.180 
            265.150 0.180 265.150 0.000 
            265.550 0.000 265.550 0.180 
            265.960 0.180 265.960 0.000 
            267.090 0.000 267.090 0.180 
            267.500 0.180 267.500 0.000 
            268.940 0.000 268.940 0.180 
            269.350 0.180 269.350 0.000 
            269.750 0.000 269.750 0.180 
            270.160 0.180 270.160 0.000 
            271.290 0.000 271.290 0.180 
            271.700 0.180 271.700 0.000 
            273.140 0.000 273.140 0.180 
            273.550 0.180 273.550 0.000 
            273.950 0.000 273.950 0.180 
            274.360 0.180 274.360 0.000 
            275.490 0.000 275.490 0.180 
            275.900 0.180 275.900 0.000 
            277.340 0.000 277.340 0.180 
            277.750 0.180 277.750 0.000 
            278.150 0.000 278.150 0.180 
            278.560 0.180 278.560 0.000 
            279.690 0.000 279.690 0.180 
            280.100 0.180 280.100 0.000 
            281.540 0.000 281.540 0.180 
            281.950 0.180 281.950 0.000 
            282.350 0.000 282.350 0.180 
            282.760 0.180 282.760 0.000 
            283.890 0.000 283.890 0.180 
            284.300 0.180 284.300 0.000 
            285.740 0.000 285.740 0.180 
            286.150 0.180 286.150 0.000 
            286.550 0.000 286.550 0.180 
            286.960 0.180 286.960 0.000 
            288.090 0.000 288.090 0.180 
            288.500 0.180 288.500 0.000 
            289.940 0.000 289.940 0.180 
            290.350 0.180 290.350 0.000 
            290.750 0.000 290.750 0.180 
            291.160 0.180 291.160 0.000 
            292.290 0.000 292.290 0.180 
            292.700 0.180 292.700 0.000 
            294.140 0.000 294.140 0.180 
            294.550 0.180 294.550 0.000 
            294.950 0.000 294.950 0.180 
            295.360 0.180 295.360 0.000 
            296.490 0.000 296.490 0.180 
            296.900 0.180 296.900 0.000 
            298.830 0.000 ;
  LAYER VIA2 SPACING 0.110 ;
    RECT 0.000 0.000 298.830 58.535 ;
  LAYER MET3 SPACING 0.150 ;
    POLYGON 298.830 0.000 298.830 58.535 
            0.000 58.535 0.000 0.000 
            2.190 0.000 2.190 0.180 
            2.600 0.180 2.600 0.000 
            3.000 0.000 3.000 0.180 
            3.410 0.180 3.410 0.000 
            4.540 0.000 4.540 0.180 
            4.950 0.180 4.950 0.000 
            6.390 0.000 6.390 0.180 
            6.800 0.180 6.800 0.000 
            7.200 0.000 7.200 0.180 
            7.610 0.180 7.610 0.000 
            8.740 0.000 8.740 0.180 
            9.150 0.180 9.150 0.000 
            10.590 0.000 10.590 0.180 
            11.000 0.180 11.000 0.000 
            11.400 0.000 11.400 0.180 
            11.810 0.180 11.810 0.000 
            12.940 0.000 12.940 0.180 
            13.350 0.180 13.350 0.000 
            14.790 0.000 14.790 0.180 
            15.200 0.180 15.200 0.000 
            15.600 0.000 15.600 0.180 
            16.010 0.180 16.010 0.000 
            17.140 0.000 17.140 0.180 
            17.550 0.180 17.550 0.000 
            18.990 0.000 18.990 0.180 
            19.400 0.180 19.400 0.000 
            19.800 0.000 19.800 0.180 
            20.210 0.180 20.210 0.000 
            21.340 0.000 21.340 0.180 
            21.750 0.180 21.750 0.000 
            23.190 0.000 23.190 0.180 
            23.600 0.180 23.600 0.000 
            24.000 0.000 24.000 0.180 
            24.410 0.180 24.410 0.000 
            25.540 0.000 25.540 0.180 
            25.950 0.180 25.950 0.000 
            27.390 0.000 27.390 0.180 
            27.800 0.180 27.800 0.000 
            28.200 0.000 28.200 0.180 
            28.610 0.180 28.610 0.000 
            29.740 0.000 29.740 0.180 
            30.150 0.180 30.150 0.000 
            31.590 0.000 31.590 0.180 
            32.000 0.180 32.000 0.000 
            32.400 0.000 32.400 0.180 
            32.810 0.180 32.810 0.000 
            33.940 0.000 33.940 0.180 
            34.350 0.180 34.350 0.000 
            35.790 0.000 35.790 0.180 
            36.200 0.180 36.200 0.000 
            36.600 0.000 36.600 0.180 
            37.010 0.180 37.010 0.000 
            38.140 0.000 38.140 0.180 
            38.550 0.180 38.550 0.000 
            39.990 0.000 39.990 0.180 
            40.400 0.180 40.400 0.000 
            40.800 0.000 40.800 0.180 
            41.210 0.180 41.210 0.000 
            42.340 0.000 42.340 0.180 
            42.750 0.180 42.750 0.000 
            44.190 0.000 44.190 0.180 
            44.600 0.180 44.600 0.000 
            45.000 0.000 45.000 0.180 
            45.410 0.180 45.410 0.000 
            46.540 0.000 46.540 0.180 
            46.950 0.180 46.950 0.000 
            48.390 0.000 48.390 0.180 
            48.800 0.180 48.800 0.000 
            49.200 0.000 49.200 0.180 
            49.610 0.180 49.610 0.000 
            50.740 0.000 50.740 0.180 
            51.150 0.180 51.150 0.000 
            52.590 0.000 52.590 0.180 
            53.000 0.180 53.000 0.000 
            53.400 0.000 53.400 0.180 
            53.810 0.180 53.810 0.000 
            54.940 0.000 54.940 0.180 
            55.350 0.180 55.350 0.000 
            56.790 0.000 56.790 0.180 
            57.200 0.180 57.200 0.000 
            57.600 0.000 57.600 0.180 
            58.010 0.180 58.010 0.000 
            59.140 0.000 59.140 0.180 
            59.550 0.180 59.550 0.000 
            60.990 0.000 60.990 0.180 
            61.400 0.180 61.400 0.000 
            61.800 0.000 61.800 0.180 
            62.210 0.180 62.210 0.000 
            63.340 0.000 63.340 0.180 
            63.750 0.180 63.750 0.000 
            65.190 0.000 65.190 0.180 
            65.600 0.180 65.600 0.000 
            66.000 0.000 66.000 0.180 
            66.410 0.180 66.410 0.000 
            67.540 0.000 67.540 0.180 
            67.950 0.180 67.950 0.000 
            69.390 0.000 69.390 0.180 
            69.800 0.180 69.800 0.000 
            70.200 0.000 70.200 0.180 
            70.610 0.180 70.610 0.000 
            71.740 0.000 71.740 0.180 
            72.150 0.180 72.150 0.000 
            73.590 0.000 73.590 0.180 
            74.000 0.180 74.000 0.000 
            74.400 0.000 74.400 0.180 
            74.810 0.180 74.810 0.000 
            75.940 0.000 75.940 0.180 
            76.350 0.180 76.350 0.000 
            77.790 0.000 77.790 0.180 
            78.200 0.180 78.200 0.000 
            78.600 0.000 78.600 0.180 
            79.010 0.180 79.010 0.000 
            80.140 0.000 80.140 0.180 
            80.550 0.180 80.550 0.000 
            81.990 0.000 81.990 0.180 
            82.400 0.180 82.400 0.000 
            82.800 0.000 82.800 0.180 
            83.210 0.180 83.210 0.000 
            84.340 0.000 84.340 0.180 
            84.750 0.180 84.750 0.000 
            86.190 0.000 86.190 0.180 
            86.600 0.180 86.600 0.000 
            87.000 0.000 87.000 0.180 
            87.410 0.180 87.410 0.000 
            88.540 0.000 88.540 0.180 
            88.950 0.180 88.950 0.000 
            90.390 0.000 90.390 0.180 
            90.800 0.180 90.800 0.000 
            91.200 0.000 91.200 0.180 
            91.610 0.180 91.610 0.000 
            92.740 0.000 92.740 0.180 
            93.150 0.180 93.150 0.000 
            94.590 0.000 94.590 0.180 
            95.000 0.180 95.000 0.000 
            95.400 0.000 95.400 0.180 
            95.810 0.180 95.810 0.000 
            96.940 0.000 96.940 0.180 
            97.350 0.180 97.350 0.000 
            98.790 0.000 98.790 0.180 
            99.200 0.180 99.200 0.000 
            99.600 0.000 99.600 0.180 
            100.010 0.180 100.010 0.000 
            101.140 0.000 101.140 0.180 
            101.550 0.180 101.550 0.000 
            102.990 0.000 102.990 0.180 
            103.400 0.180 103.400 0.000 
            103.800 0.000 103.800 0.180 
            104.210 0.180 104.210 0.000 
            105.340 0.000 105.340 0.180 
            105.750 0.180 105.750 0.000 
            107.190 0.000 107.190 0.180 
            107.600 0.180 107.600 0.000 
            108.000 0.000 108.000 0.180 
            108.410 0.180 108.410 0.000 
            109.540 0.000 109.540 0.180 
            109.950 0.180 109.950 0.000 
            111.390 0.000 111.390 0.180 
            111.800 0.180 111.800 0.000 
            112.200 0.000 112.200 0.180 
            112.610 0.180 112.610 0.000 
            113.740 0.000 113.740 0.180 
            114.150 0.180 114.150 0.000 
            115.590 0.000 115.590 0.180 
            116.000 0.180 116.000 0.000 
            116.400 0.000 116.400 0.180 
            116.810 0.180 116.810 0.000 
            117.940 0.000 117.940 0.180 
            118.350 0.180 118.350 0.000 
            119.790 0.000 119.790 0.180 
            120.200 0.180 120.200 0.000 
            120.600 0.000 120.600 0.180 
            121.010 0.180 121.010 0.000 
            122.140 0.000 122.140 0.180 
            122.550 0.180 122.550 0.000 
            123.990 0.000 123.990 0.180 
            124.400 0.180 124.400 0.000 
            124.800 0.000 124.800 0.180 
            125.210 0.180 125.210 0.000 
            126.340 0.000 126.340 0.180 
            126.750 0.180 126.750 0.000 
            128.190 0.000 128.190 0.180 
            128.600 0.180 128.600 0.000 
            129.000 0.000 129.000 0.180 
            129.410 0.180 129.410 0.000 
            130.540 0.000 130.540 0.180 
            130.950 0.180 130.950 0.000 
            132.390 0.000 132.390 0.180 
            132.800 0.180 132.800 0.000 
            133.200 0.000 133.200 0.180 
            133.610 0.180 133.610 0.000 
            134.740 0.000 134.740 0.180 
            135.150 0.180 135.150 0.000 
            140.150 0.000 140.150 0.180 
            140.560 0.180 140.560 0.000 
            140.680 0.000 140.680 0.180 
            141.090 0.180 141.090 0.000 
            141.500 0.000 141.500 0.180 
            141.910 0.180 141.910 0.000 
            142.080 0.000 142.080 0.180 
            142.490 0.180 142.490 0.000 
            143.140 0.000 143.140 0.180 
            143.550 0.180 143.550 0.000 
            143.685 0.000 143.685 0.180 
            144.095 0.180 144.095 0.000 
            144.215 0.000 144.215 0.180 
            144.625 0.180 144.625 0.000 
            144.745 0.000 144.745 0.180 
            145.155 0.180 145.155 0.000 
            145.275 0.000 145.275 0.180 
            145.685 0.180 145.685 0.000 
            145.805 0.000 145.805 0.180 
            146.215 0.180 146.215 0.000 
            146.465 0.000 146.465 0.180 
            146.875 0.180 146.875 0.000 
            147.590 0.000 147.590 0.180 
            148.000 0.180 148.000 0.000 
            155.210 0.000 155.210 0.180 
            155.620 0.180 155.620 0.000 
            155.900 0.000 155.900 0.180 
            156.310 0.180 156.310 0.000 
            158.875 0.000 158.875 0.180 
            159.285 0.180 159.285 0.000 
            159.590 0.000 159.590 0.180 
            160.000 0.180 160.000 0.000 
            163.940 0.000 163.940 0.180 
            164.350 0.180 164.350 0.000 
            164.750 0.000 164.750 0.180 
            165.160 0.180 165.160 0.000 
            166.290 0.000 166.290 0.180 
            166.700 0.180 166.700 0.000 
            168.140 0.000 168.140 0.180 
            168.550 0.180 168.550 0.000 
            168.950 0.000 168.950 0.180 
            169.360 0.180 169.360 0.000 
            170.490 0.000 170.490 0.180 
            170.900 0.180 170.900 0.000 
            172.340 0.000 172.340 0.180 
            172.750 0.180 172.750 0.000 
            173.150 0.000 173.150 0.180 
            173.560 0.180 173.560 0.000 
            174.690 0.000 174.690 0.180 
            175.100 0.180 175.100 0.000 
            176.540 0.000 176.540 0.180 
            176.950 0.180 176.950 0.000 
            177.350 0.000 177.350 0.180 
            177.760 0.180 177.760 0.000 
            178.890 0.000 178.890 0.180 
            179.300 0.180 179.300 0.000 
            180.740 0.000 180.740 0.180 
            181.150 0.180 181.150 0.000 
            181.550 0.000 181.550 0.180 
            181.960 0.180 181.960 0.000 
            183.090 0.000 183.090 0.180 
            183.500 0.180 183.500 0.000 
            184.940 0.000 184.940 0.180 
            185.350 0.180 185.350 0.000 
            185.750 0.000 185.750 0.180 
            186.160 0.180 186.160 0.000 
            187.290 0.000 187.290 0.180 
            187.700 0.180 187.700 0.000 
            189.140 0.000 189.140 0.180 
            189.550 0.180 189.550 0.000 
            189.950 0.000 189.950 0.180 
            190.360 0.180 190.360 0.000 
            191.490 0.000 191.490 0.180 
            191.900 0.180 191.900 0.000 
            193.340 0.000 193.340 0.180 
            193.750 0.180 193.750 0.000 
            194.150 0.000 194.150 0.180 
            194.560 0.180 194.560 0.000 
            195.690 0.000 195.690 0.180 
            196.100 0.180 196.100 0.000 
            197.540 0.000 197.540 0.180 
            197.950 0.180 197.950 0.000 
            198.350 0.000 198.350 0.180 
            198.760 0.180 198.760 0.000 
            199.890 0.000 199.890 0.180 
            200.300 0.180 200.300 0.000 
            201.740 0.000 201.740 0.180 
            202.150 0.180 202.150 0.000 
            202.550 0.000 202.550 0.180 
            202.960 0.180 202.960 0.000 
            204.090 0.000 204.090 0.180 
            204.500 0.180 204.500 0.000 
            205.940 0.000 205.940 0.180 
            206.350 0.180 206.350 0.000 
            206.750 0.000 206.750 0.180 
            207.160 0.180 207.160 0.000 
            208.290 0.000 208.290 0.180 
            208.700 0.180 208.700 0.000 
            210.140 0.000 210.140 0.180 
            210.550 0.180 210.550 0.000 
            210.950 0.000 210.950 0.180 
            211.360 0.180 211.360 0.000 
            212.490 0.000 212.490 0.180 
            212.900 0.180 212.900 0.000 
            214.340 0.000 214.340 0.180 
            214.750 0.180 214.750 0.000 
            215.150 0.000 215.150 0.180 
            215.560 0.180 215.560 0.000 
            216.690 0.000 216.690 0.180 
            217.100 0.180 217.100 0.000 
            218.540 0.000 218.540 0.180 
            218.950 0.180 218.950 0.000 
            219.350 0.000 219.350 0.180 
            219.760 0.180 219.760 0.000 
            220.890 0.000 220.890 0.180 
            221.300 0.180 221.300 0.000 
            222.740 0.000 222.740 0.180 
            223.150 0.180 223.150 0.000 
            223.550 0.000 223.550 0.180 
            223.960 0.180 223.960 0.000 
            225.090 0.000 225.090 0.180 
            225.500 0.180 225.500 0.000 
            226.940 0.000 226.940 0.180 
            227.350 0.180 227.350 0.000 
            227.750 0.000 227.750 0.180 
            228.160 0.180 228.160 0.000 
            229.290 0.000 229.290 0.180 
            229.700 0.180 229.700 0.000 
            231.140 0.000 231.140 0.180 
            231.550 0.180 231.550 0.000 
            231.950 0.000 231.950 0.180 
            232.360 0.180 232.360 0.000 
            233.490 0.000 233.490 0.180 
            233.900 0.180 233.900 0.000 
            235.340 0.000 235.340 0.180 
            235.750 0.180 235.750 0.000 
            236.150 0.000 236.150 0.180 
            236.560 0.180 236.560 0.000 
            237.690 0.000 237.690 0.180 
            238.100 0.180 238.100 0.000 
            239.540 0.000 239.540 0.180 
            239.950 0.180 239.950 0.000 
            240.350 0.000 240.350 0.180 
            240.760 0.180 240.760 0.000 
            241.890 0.000 241.890 0.180 
            242.300 0.180 242.300 0.000 
            243.740 0.000 243.740 0.180 
            244.150 0.180 244.150 0.000 
            244.550 0.000 244.550 0.180 
            244.960 0.180 244.960 0.000 
            246.090 0.000 246.090 0.180 
            246.500 0.180 246.500 0.000 
            247.940 0.000 247.940 0.180 
            248.350 0.180 248.350 0.000 
            248.750 0.000 248.750 0.180 
            249.160 0.180 249.160 0.000 
            250.290 0.000 250.290 0.180 
            250.700 0.180 250.700 0.000 
            252.140 0.000 252.140 0.180 
            252.550 0.180 252.550 0.000 
            252.950 0.000 252.950 0.180 
            253.360 0.180 253.360 0.000 
            254.490 0.000 254.490 0.180 
            254.900 0.180 254.900 0.000 
            256.340 0.000 256.340 0.180 
            256.750 0.180 256.750 0.000 
            257.150 0.000 257.150 0.180 
            257.560 0.180 257.560 0.000 
            258.690 0.000 258.690 0.180 
            259.100 0.180 259.100 0.000 
            260.540 0.000 260.540 0.180 
            260.950 0.180 260.950 0.000 
            261.350 0.000 261.350 0.180 
            261.760 0.180 261.760 0.000 
            262.890 0.000 262.890 0.180 
            263.300 0.180 263.300 0.000 
            264.740 0.000 264.740 0.180 
            265.150 0.180 265.150 0.000 
            265.550 0.000 265.550 0.180 
            265.960 0.180 265.960 0.000 
            267.090 0.000 267.090 0.180 
            267.500 0.180 267.500 0.000 
            268.940 0.000 268.940 0.180 
            269.350 0.180 269.350 0.000 
            269.750 0.000 269.750 0.180 
            270.160 0.180 270.160 0.000 
            271.290 0.000 271.290 0.180 
            271.700 0.180 271.700 0.000 
            273.140 0.000 273.140 0.180 
            273.550 0.180 273.550 0.000 
            273.950 0.000 273.950 0.180 
            274.360 0.180 274.360 0.000 
            275.490 0.000 275.490 0.180 
            275.900 0.180 275.900 0.000 
            277.340 0.000 277.340 0.180 
            277.750 0.180 277.750 0.000 
            278.150 0.000 278.150 0.180 
            278.560 0.180 278.560 0.000 
            279.690 0.000 279.690 0.180 
            280.100 0.180 280.100 0.000 
            281.540 0.000 281.540 0.180 
            281.950 0.180 281.950 0.000 
            282.350 0.000 282.350 0.180 
            282.760 0.180 282.760 0.000 
            283.890 0.000 283.890 0.180 
            284.300 0.180 284.300 0.000 
            285.740 0.000 285.740 0.180 
            286.150 0.180 286.150 0.000 
            286.550 0.000 286.550 0.180 
            286.960 0.180 286.960 0.000 
            288.090 0.000 288.090 0.180 
            288.500 0.180 288.500 0.000 
            289.940 0.000 289.940 0.180 
            290.350 0.180 290.350 0.000 
            290.750 0.000 290.750 0.180 
            291.160 0.180 291.160 0.000 
            292.290 0.000 292.290 0.180 
            292.700 0.180 292.700 0.000 
            294.140 0.000 294.140 0.180 
            294.550 0.180 294.550 0.000 
            294.950 0.000 294.950 0.180 
            295.360 0.180 295.360 0.000 
            296.490 0.000 296.490 0.180 
            296.900 0.180 296.900 0.000 
            298.830 0.000 ;
  LAYER VIA3 SPACING 0.110 ;
    RECT 0.000 0.000 298.830 58.535 ;
  LAYER MET4 SPACING 0.150 ;
    RECT 0.000 0.000 0.075 58.535 ;
    RECT 0.485 0.000 0.605 58.535 ;
    RECT 1.015 0.000 1.135 58.535 ;
    RECT 1.545 0.000 1.735 58.535 ;
    RECT 2.145 0.000 2.335 58.535 ;
    RECT 2.745 0.000 2.935 58.535 ;
    RECT 3.345 0.000 3.535 58.535 ;
    RECT 3.945 0.000 4.135 58.535 ;
    RECT 4.545 0.000 4.735 58.535 ;
    RECT 5.145 0.000 5.335 58.535 ;
    RECT 5.745 0.000 5.935 58.535 ;
    RECT 6.345 0.000 6.535 58.535 ;
    RECT 6.945 0.000 7.135 58.535 ;
    RECT 7.545 0.000 7.735 58.535 ;
    RECT 8.145 0.000 8.335 58.535 ;
    RECT 8.745 0.000 8.935 58.535 ;
    RECT 9.345 0.000 9.535 58.535 ;
    RECT 9.945 0.000 10.135 58.535 ;
    RECT 10.545 0.000 10.735 58.535 ;
    RECT 11.145 0.000 11.335 58.535 ;
    RECT 11.745 0.000 11.935 58.535 ;
    RECT 12.345 0.000 12.535 58.535 ;
    RECT 12.945 0.000 13.135 58.535 ;
    RECT 13.545 0.000 13.735 58.535 ;
    RECT 14.145 0.000 14.335 58.535 ;
    RECT 14.745 0.000 14.935 58.535 ;
    RECT 15.345 0.000 15.535 58.535 ;
    RECT 15.945 0.000 16.135 58.535 ;
    RECT 16.545 0.000 16.735 58.535 ;
    RECT 17.145 0.000 17.335 58.535 ;
    RECT 17.745 0.000 17.935 58.535 ;
    RECT 18.345 0.000 18.535 58.535 ;
    RECT 18.945 0.000 19.135 58.535 ;
    RECT 19.545 0.000 19.735 58.535 ;
    RECT 20.145 0.000 20.335 58.535 ;
    RECT 20.745 0.000 20.935 58.535 ;
    RECT 21.345 0.000 21.535 58.535 ;
    RECT 21.945 0.000 22.135 58.535 ;
    RECT 22.545 0.000 22.735 58.535 ;
    RECT 23.145 0.000 23.335 58.535 ;
    RECT 23.745 0.000 23.935 58.535 ;
    RECT 24.345 0.000 24.535 58.535 ;
    RECT 24.945 0.000 25.135 58.535 ;
    RECT 25.545 0.000 25.735 58.535 ;
    RECT 26.145 0.000 26.335 58.535 ;
    RECT 26.745 0.000 26.935 58.535 ;
    RECT 27.345 0.000 27.535 58.535 ;
    RECT 27.945 0.000 28.135 58.535 ;
    RECT 28.545 0.000 28.735 58.535 ;
    RECT 29.145 0.000 29.335 58.535 ;
    RECT 29.745 0.000 29.935 58.535 ;
    RECT 30.345 0.000 30.535 58.535 ;
    RECT 30.945 0.000 31.135 58.535 ;
    RECT 31.545 0.000 31.735 58.535 ;
    RECT 32.145 0.000 32.335 58.535 ;
    RECT 32.745 0.000 32.935 58.535 ;
    RECT 33.345 0.000 33.535 58.535 ;
    RECT 33.945 0.000 34.135 58.535 ;
    RECT 34.545 0.000 34.735 58.535 ;
    RECT 35.145 0.000 35.335 58.535 ;
    RECT 35.745 0.000 35.935 58.535 ;
    RECT 36.345 0.000 36.535 58.535 ;
    RECT 36.945 0.000 37.135 58.535 ;
    RECT 37.545 0.000 37.735 58.535 ;
    RECT 38.145 0.000 38.335 58.535 ;
    RECT 38.745 0.000 38.935 58.535 ;
    RECT 39.345 0.000 39.535 58.535 ;
    RECT 39.945 0.000 40.135 58.535 ;
    RECT 40.545 0.000 40.735 58.535 ;
    RECT 41.145 0.000 41.335 58.535 ;
    RECT 41.745 0.000 41.935 58.535 ;
    RECT 42.345 0.000 42.535 58.535 ;
    RECT 42.945 0.000 43.135 58.535 ;
    RECT 43.545 0.000 43.735 58.535 ;
    RECT 44.145 0.000 44.335 58.535 ;
    RECT 44.745 0.000 44.935 58.535 ;
    RECT 45.345 0.000 45.535 58.535 ;
    RECT 45.945 0.000 46.135 58.535 ;
    RECT 46.545 0.000 46.735 58.535 ;
    RECT 47.145 0.000 47.335 58.535 ;
    RECT 47.745 0.000 47.935 58.535 ;
    RECT 48.345 0.000 48.535 58.535 ;
    RECT 48.945 0.000 49.135 58.535 ;
    RECT 49.545 0.000 49.735 58.535 ;
    RECT 50.145 0.000 50.335 58.535 ;
    RECT 50.745 0.000 50.935 58.535 ;
    RECT 51.345 0.000 51.535 58.535 ;
    RECT 51.945 0.000 52.135 58.535 ;
    RECT 52.545 0.000 52.735 58.535 ;
    RECT 53.145 0.000 53.335 58.535 ;
    RECT 53.745 0.000 53.935 58.535 ;
    RECT 54.345 0.000 54.535 58.535 ;
    RECT 54.945 0.000 55.135 58.535 ;
    RECT 55.545 0.000 55.735 58.535 ;
    RECT 56.145 0.000 56.335 58.535 ;
    RECT 56.745 0.000 56.935 58.535 ;
    RECT 57.345 0.000 57.535 58.535 ;
    RECT 57.945 0.000 58.135 58.535 ;
    RECT 58.545 0.000 58.735 58.535 ;
    RECT 59.145 0.000 59.335 58.535 ;
    RECT 59.745 0.000 59.935 58.535 ;
    RECT 60.345 0.000 60.535 58.535 ;
    RECT 60.945 0.000 61.135 58.535 ;
    RECT 61.545 0.000 61.735 58.535 ;
    RECT 62.145 0.000 62.335 58.535 ;
    RECT 62.745 0.000 62.935 58.535 ;
    RECT 63.345 0.000 63.535 58.535 ;
    RECT 63.945 0.000 64.135 58.535 ;
    RECT 64.545 0.000 64.735 58.535 ;
    RECT 65.145 0.000 65.335 58.535 ;
    RECT 65.745 0.000 65.935 58.535 ;
    RECT 66.345 0.000 66.535 58.535 ;
    RECT 66.945 0.000 67.135 58.535 ;
    RECT 67.545 0.000 67.735 58.535 ;
    RECT 68.145 0.000 68.335 58.535 ;
    RECT 68.745 0.000 68.935 58.535 ;
    RECT 69.345 0.000 69.535 58.535 ;
    RECT 69.945 0.000 70.135 58.535 ;
    RECT 70.545 0.000 70.735 58.535 ;
    RECT 71.145 0.000 71.335 58.535 ;
    RECT 71.745 0.000 71.935 58.535 ;
    RECT 72.345 0.000 72.535 58.535 ;
    RECT 72.945 0.000 73.135 58.535 ;
    RECT 73.545 0.000 73.735 58.535 ;
    RECT 74.145 0.000 74.335 58.535 ;
    RECT 74.745 0.000 74.935 58.535 ;
    RECT 75.345 0.000 75.535 58.535 ;
    RECT 75.945 0.000 76.135 58.535 ;
    RECT 76.545 0.000 76.735 58.535 ;
    RECT 77.145 0.000 77.335 58.535 ;
    RECT 77.745 0.000 77.935 58.535 ;
    RECT 78.345 0.000 78.535 58.535 ;
    RECT 78.945 0.000 79.135 58.535 ;
    RECT 79.545 0.000 79.735 58.535 ;
    RECT 80.145 0.000 80.335 58.535 ;
    RECT 80.745 0.000 80.935 58.535 ;
    RECT 81.345 0.000 81.535 58.535 ;
    RECT 81.945 0.000 82.135 58.535 ;
    RECT 82.545 0.000 82.735 58.535 ;
    RECT 83.145 0.000 83.335 58.535 ;
    RECT 83.745 0.000 83.935 58.535 ;
    RECT 84.345 0.000 84.535 58.535 ;
    RECT 84.945 0.000 85.135 58.535 ;
    RECT 85.545 0.000 85.735 58.535 ;
    RECT 86.145 0.000 86.335 58.535 ;
    RECT 86.745 0.000 86.935 58.535 ;
    RECT 87.345 0.000 87.535 58.535 ;
    RECT 87.945 0.000 88.135 58.535 ;
    RECT 88.545 0.000 88.735 58.535 ;
    RECT 89.145 0.000 89.335 58.535 ;
    RECT 89.745 0.000 89.935 58.535 ;
    RECT 90.345 0.000 90.535 58.535 ;
    RECT 90.945 0.000 91.135 58.535 ;
    RECT 91.545 0.000 91.735 58.535 ;
    RECT 92.145 0.000 92.335 58.535 ;
    RECT 92.745 0.000 92.935 58.535 ;
    RECT 93.345 0.000 93.535 58.535 ;
    RECT 93.945 0.000 94.135 58.535 ;
    RECT 94.545 0.000 94.735 58.535 ;
    RECT 95.145 0.000 95.335 58.535 ;
    RECT 95.745 0.000 95.935 58.535 ;
    RECT 96.345 0.000 96.535 58.535 ;
    RECT 96.945 0.000 97.135 58.535 ;
    RECT 97.545 0.000 97.735 58.535 ;
    RECT 98.145 0.000 98.335 58.535 ;
    RECT 98.745 0.000 98.935 58.535 ;
    RECT 99.345 0.000 99.535 58.535 ;
    RECT 99.945 0.000 100.135 58.535 ;
    RECT 100.545 0.000 100.735 58.535 ;
    RECT 101.145 0.000 101.335 58.535 ;
    RECT 101.745 0.000 101.935 58.535 ;
    RECT 102.345 0.000 102.535 58.535 ;
    RECT 102.945 0.000 103.135 58.535 ;
    RECT 103.545 0.000 103.735 58.535 ;
    RECT 104.145 0.000 104.335 58.535 ;
    RECT 104.745 0.000 104.935 58.535 ;
    RECT 105.345 0.000 105.535 58.535 ;
    RECT 105.945 0.000 106.135 58.535 ;
    RECT 106.545 0.000 106.735 58.535 ;
    RECT 107.145 0.000 107.335 58.535 ;
    RECT 107.745 0.000 107.935 58.535 ;
    RECT 108.345 0.000 108.535 58.535 ;
    RECT 108.945 0.000 109.135 58.535 ;
    RECT 109.545 0.000 109.735 58.535 ;
    RECT 110.145 0.000 110.335 58.535 ;
    RECT 110.745 0.000 110.935 58.535 ;
    RECT 111.345 0.000 111.535 58.535 ;
    RECT 111.945 0.000 112.135 58.535 ;
    RECT 112.545 0.000 112.735 58.535 ;
    RECT 113.145 0.000 113.335 58.535 ;
    RECT 113.745 0.000 113.935 58.535 ;
    RECT 114.345 0.000 114.535 58.535 ;
    RECT 114.945 0.000 115.135 58.535 ;
    RECT 115.545 0.000 115.735 58.535 ;
    RECT 116.145 0.000 116.335 58.535 ;
    RECT 116.745 0.000 116.935 58.535 ;
    RECT 117.345 0.000 117.535 58.535 ;
    RECT 117.945 0.000 118.135 58.535 ;
    RECT 118.545 0.000 118.735 58.535 ;
    RECT 119.145 0.000 119.335 58.535 ;
    RECT 119.745 0.000 119.935 58.535 ;
    RECT 120.345 0.000 120.535 58.535 ;
    RECT 120.945 0.000 121.135 58.535 ;
    RECT 121.545 0.000 121.735 58.535 ;
    RECT 122.145 0.000 122.335 58.535 ;
    RECT 122.745 0.000 122.935 58.535 ;
    RECT 123.345 0.000 123.535 58.535 ;
    RECT 123.945 0.000 124.135 58.535 ;
    RECT 124.545 0.000 124.735 58.535 ;
    RECT 125.145 0.000 125.335 58.535 ;
    RECT 125.745 0.000 125.935 58.535 ;
    RECT 126.345 0.000 126.535 58.535 ;
    RECT 126.945 0.000 127.135 58.535 ;
    RECT 127.545 0.000 127.735 58.535 ;
    RECT 128.145 0.000 128.335 58.535 ;
    RECT 128.745 0.000 128.935 58.535 ;
    RECT 129.345 0.000 129.535 58.535 ;
    RECT 129.945 0.000 130.135 58.535 ;
    RECT 130.545 0.000 130.735 58.535 ;
    RECT 131.145 0.000 131.335 58.535 ;
    RECT 131.745 0.000 131.935 58.535 ;
    RECT 132.345 0.000 132.535 58.535 ;
    RECT 132.945 0.000 133.135 58.535 ;
    RECT 133.545 0.000 133.735 58.535 ;
    RECT 134.145 0.000 134.335 58.535 ;
    RECT 134.745 0.000 134.935 58.535 ;
    RECT 135.345 0.000 135.535 58.535 ;
    RECT 135.945 0.000 136.065 58.535 ;
    RECT 136.475 0.000 136.595 58.535 ;
    RECT 137.005 0.000 137.430 58.535 ;
    RECT 137.840 0.000 137.960 58.535 ;
    RECT 138.370 0.000 138.490 58.535 ;
    RECT 138.900 0.000 139.020 58.535 ;
    RECT 139.430 0.000 139.550 58.535 ;
    RECT 139.960 0.000 140.080 58.535 ;
    RECT 140.490 0.000 140.610 58.535 ;
    RECT 141.020 0.000 141.140 58.535 ;
    RECT 141.550 0.000 141.670 58.535 ;
    RECT 142.080 0.000 142.200 58.535 ;
    RECT 142.610 0.000 142.730 58.535 ;
    RECT 143.140 0.000 143.260 58.535 ;
    RECT 143.670 0.000 143.790 58.535 ;
    RECT 144.200 0.000 144.320 58.535 ;
    RECT 144.730 0.000 144.850 58.535 ;
    RECT 145.260 0.000 145.380 58.535 ;
    RECT 145.790 0.000 145.910 58.535 ;
    RECT 146.320 0.000 146.440 58.535 ;
    RECT 146.850 0.000 146.970 58.535 ;
    RECT 147.380 0.000 147.500 58.535 ;
    RECT 147.910 0.000 148.030 58.535 ;
    RECT 148.440 0.000 148.560 58.535 ;
    RECT 148.970 0.000 149.090 58.535 ;
    RECT 149.500 0.000 149.620 58.535 ;
    RECT 150.030 0.000 150.150 58.535 ;
    RECT 150.560 0.000 150.680 58.535 ;
    RECT 151.090 0.000 151.210 58.535 ;
    RECT 151.620 0.000 151.740 58.535 ;
    RECT 152.150 0.000 152.270 58.535 ;
    RECT 152.680 0.000 152.800 58.535 ;
    RECT 153.210 0.000 153.330 58.535 ;
    RECT 153.740 0.000 153.860 58.535 ;
    RECT 154.270 0.000 154.390 58.535 ;
    RECT 154.800 0.000 154.920 58.535 ;
    RECT 155.330 0.000 155.450 58.535 ;
    RECT 155.860 0.000 155.980 58.535 ;
    RECT 156.390 0.000 156.510 58.535 ;
    RECT 156.920 0.000 157.040 58.535 ;
    RECT 157.450 0.000 157.570 58.535 ;
    RECT 157.980 0.000 158.100 58.535 ;
    RECT 158.510 0.000 158.630 58.535 ;
    RECT 159.040 0.000 159.160 58.535 ;
    RECT 159.570 0.000 159.690 58.535 ;
    RECT 160.100 0.000 160.220 58.535 ;
    RECT 160.630 0.000 160.750 58.535 ;
    RECT 161.160 0.000 161.280 58.535 ;
    RECT 161.690 0.000 161.825 58.535 ;
    RECT 162.235 0.000 162.355 58.535 ;
    RECT 162.765 0.000 162.885 58.535 ;
    RECT 163.295 0.000 163.485 58.535 ;
    RECT 163.895 0.000 164.085 58.535 ;
    RECT 164.495 0.000 164.685 58.535 ;
    RECT 165.095 0.000 165.285 58.535 ;
    RECT 165.695 0.000 165.885 58.535 ;
    RECT 166.295 0.000 166.485 58.535 ;
    RECT 166.895 0.000 167.085 58.535 ;
    RECT 167.495 0.000 167.685 58.535 ;
    RECT 168.095 0.000 168.285 58.535 ;
    RECT 168.695 0.000 168.885 58.535 ;
    RECT 169.295 0.000 169.485 58.535 ;
    RECT 169.895 0.000 170.085 58.535 ;
    RECT 170.495 0.000 170.685 58.535 ;
    RECT 171.095 0.000 171.285 58.535 ;
    RECT 171.695 0.000 171.885 58.535 ;
    RECT 172.295 0.000 172.485 58.535 ;
    RECT 172.895 0.000 173.085 58.535 ;
    RECT 173.495 0.000 173.685 58.535 ;
    RECT 174.095 0.000 174.285 58.535 ;
    RECT 174.695 0.000 174.885 58.535 ;
    RECT 175.295 0.000 175.485 58.535 ;
    RECT 175.895 0.000 176.085 58.535 ;
    RECT 176.495 0.000 176.685 58.535 ;
    RECT 177.095 0.000 177.285 58.535 ;
    RECT 177.695 0.000 177.885 58.535 ;
    RECT 178.295 0.000 178.485 58.535 ;
    RECT 178.895 0.000 179.085 58.535 ;
    RECT 179.495 0.000 179.685 58.535 ;
    RECT 180.095 0.000 180.285 58.535 ;
    RECT 180.695 0.000 180.885 58.535 ;
    RECT 181.295 0.000 181.485 58.535 ;
    RECT 181.895 0.000 182.085 58.535 ;
    RECT 182.495 0.000 182.685 58.535 ;
    RECT 183.095 0.000 183.285 58.535 ;
    RECT 183.695 0.000 183.885 58.535 ;
    RECT 184.295 0.000 184.485 58.535 ;
    RECT 184.895 0.000 185.085 58.535 ;
    RECT 185.495 0.000 185.685 58.535 ;
    RECT 186.095 0.000 186.285 58.535 ;
    RECT 186.695 0.000 186.885 58.535 ;
    RECT 187.295 0.000 187.485 58.535 ;
    RECT 187.895 0.000 188.085 58.535 ;
    RECT 188.495 0.000 188.685 58.535 ;
    RECT 189.095 0.000 189.285 58.535 ;
    RECT 189.695 0.000 189.885 58.535 ;
    RECT 190.295 0.000 190.485 58.535 ;
    RECT 190.895 0.000 191.085 58.535 ;
    RECT 191.495 0.000 191.685 58.535 ;
    RECT 192.095 0.000 192.285 58.535 ;
    RECT 192.695 0.000 192.885 58.535 ;
    RECT 193.295 0.000 193.485 58.535 ;
    RECT 193.895 0.000 194.085 58.535 ;
    RECT 194.495 0.000 194.685 58.535 ;
    RECT 195.095 0.000 195.285 58.535 ;
    RECT 195.695 0.000 195.885 58.535 ;
    RECT 196.295 0.000 196.485 58.535 ;
    RECT 196.895 0.000 197.085 58.535 ;
    RECT 197.495 0.000 197.685 58.535 ;
    RECT 198.095 0.000 198.285 58.535 ;
    RECT 198.695 0.000 198.885 58.535 ;
    RECT 199.295 0.000 199.485 58.535 ;
    RECT 199.895 0.000 200.085 58.535 ;
    RECT 200.495 0.000 200.685 58.535 ;
    RECT 201.095 0.000 201.285 58.535 ;
    RECT 201.695 0.000 201.885 58.535 ;
    RECT 202.295 0.000 202.485 58.535 ;
    RECT 202.895 0.000 203.085 58.535 ;
    RECT 203.495 0.000 203.685 58.535 ;
    RECT 204.095 0.000 204.285 58.535 ;
    RECT 204.695 0.000 204.885 58.535 ;
    RECT 205.295 0.000 205.485 58.535 ;
    RECT 205.895 0.000 206.085 58.535 ;
    RECT 206.495 0.000 206.685 58.535 ;
    RECT 207.095 0.000 207.285 58.535 ;
    RECT 207.695 0.000 207.885 58.535 ;
    RECT 208.295 0.000 208.485 58.535 ;
    RECT 208.895 0.000 209.085 58.535 ;
    RECT 209.495 0.000 209.685 58.535 ;
    RECT 210.095 0.000 210.285 58.535 ;
    RECT 210.695 0.000 210.885 58.535 ;
    RECT 211.295 0.000 211.485 58.535 ;
    RECT 211.895 0.000 212.085 58.535 ;
    RECT 212.495 0.000 212.685 58.535 ;
    RECT 213.095 0.000 213.285 58.535 ;
    RECT 213.695 0.000 213.885 58.535 ;
    RECT 214.295 0.000 214.485 58.535 ;
    RECT 214.895 0.000 215.085 58.535 ;
    RECT 215.495 0.000 215.685 58.535 ;
    RECT 216.095 0.000 216.285 58.535 ;
    RECT 216.695 0.000 216.885 58.535 ;
    RECT 217.295 0.000 217.485 58.535 ;
    RECT 217.895 0.000 218.085 58.535 ;
    RECT 218.495 0.000 218.685 58.535 ;
    RECT 219.095 0.000 219.285 58.535 ;
    RECT 219.695 0.000 219.885 58.535 ;
    RECT 220.295 0.000 220.485 58.535 ;
    RECT 220.895 0.000 221.085 58.535 ;
    RECT 221.495 0.000 221.685 58.535 ;
    RECT 222.095 0.000 222.285 58.535 ;
    RECT 222.695 0.000 222.885 58.535 ;
    RECT 223.295 0.000 223.485 58.535 ;
    RECT 223.895 0.000 224.085 58.535 ;
    RECT 224.495 0.000 224.685 58.535 ;
    RECT 225.095 0.000 225.285 58.535 ;
    RECT 225.695 0.000 225.885 58.535 ;
    RECT 226.295 0.000 226.485 58.535 ;
    RECT 226.895 0.000 227.085 58.535 ;
    RECT 227.495 0.000 227.685 58.535 ;
    RECT 228.095 0.000 228.285 58.535 ;
    RECT 228.695 0.000 228.885 58.535 ;
    RECT 229.295 0.000 229.485 58.535 ;
    RECT 229.895 0.000 230.085 58.535 ;
    RECT 230.495 0.000 230.685 58.535 ;
    RECT 231.095 0.000 231.285 58.535 ;
    RECT 231.695 0.000 231.885 58.535 ;
    RECT 232.295 0.000 232.485 58.535 ;
    RECT 232.895 0.000 233.085 58.535 ;
    RECT 233.495 0.000 233.685 58.535 ;
    RECT 234.095 0.000 234.285 58.535 ;
    RECT 234.695 0.000 234.885 58.535 ;
    RECT 235.295 0.000 235.485 58.535 ;
    RECT 235.895 0.000 236.085 58.535 ;
    RECT 236.495 0.000 236.685 58.535 ;
    RECT 237.095 0.000 237.285 58.535 ;
    RECT 237.695 0.000 237.885 58.535 ;
    RECT 238.295 0.000 238.485 58.535 ;
    RECT 238.895 0.000 239.085 58.535 ;
    RECT 239.495 0.000 239.685 58.535 ;
    RECT 240.095 0.000 240.285 58.535 ;
    RECT 240.695 0.000 240.885 58.535 ;
    RECT 241.295 0.000 241.485 58.535 ;
    RECT 241.895 0.000 242.085 58.535 ;
    RECT 242.495 0.000 242.685 58.535 ;
    RECT 243.095 0.000 243.285 58.535 ;
    RECT 243.695 0.000 243.885 58.535 ;
    RECT 244.295 0.000 244.485 58.535 ;
    RECT 244.895 0.000 245.085 58.535 ;
    RECT 245.495 0.000 245.685 58.535 ;
    RECT 246.095 0.000 246.285 58.535 ;
    RECT 246.695 0.000 246.885 58.535 ;
    RECT 247.295 0.000 247.485 58.535 ;
    RECT 247.895 0.000 248.085 58.535 ;
    RECT 248.495 0.000 248.685 58.535 ;
    RECT 249.095 0.000 249.285 58.535 ;
    RECT 249.695 0.000 249.885 58.535 ;
    RECT 250.295 0.000 250.485 58.535 ;
    RECT 250.895 0.000 251.085 58.535 ;
    RECT 251.495 0.000 251.685 58.535 ;
    RECT 252.095 0.000 252.285 58.535 ;
    RECT 252.695 0.000 252.885 58.535 ;
    RECT 253.295 0.000 253.485 58.535 ;
    RECT 253.895 0.000 254.085 58.535 ;
    RECT 254.495 0.000 254.685 58.535 ;
    RECT 255.095 0.000 255.285 58.535 ;
    RECT 255.695 0.000 255.885 58.535 ;
    RECT 256.295 0.000 256.485 58.535 ;
    RECT 256.895 0.000 257.085 58.535 ;
    RECT 257.495 0.000 257.685 58.535 ;
    RECT 258.095 0.000 258.285 58.535 ;
    RECT 258.695 0.000 258.885 58.535 ;
    RECT 259.295 0.000 259.485 58.535 ;
    RECT 259.895 0.000 260.085 58.535 ;
    RECT 260.495 0.000 260.685 58.535 ;
    RECT 261.095 0.000 261.285 58.535 ;
    RECT 261.695 0.000 261.885 58.535 ;
    RECT 262.295 0.000 262.485 58.535 ;
    RECT 262.895 0.000 263.085 58.535 ;
    RECT 263.495 0.000 263.685 58.535 ;
    RECT 264.095 0.000 264.285 58.535 ;
    RECT 264.695 0.000 264.885 58.535 ;
    RECT 265.295 0.000 265.485 58.535 ;
    RECT 265.895 0.000 266.085 58.535 ;
    RECT 266.495 0.000 266.685 58.535 ;
    RECT 267.095 0.000 267.285 58.535 ;
    RECT 267.695 0.000 267.885 58.535 ;
    RECT 268.295 0.000 268.485 58.535 ;
    RECT 268.895 0.000 269.085 58.535 ;
    RECT 269.495 0.000 269.685 58.535 ;
    RECT 270.095 0.000 270.285 58.535 ;
    RECT 270.695 0.000 270.885 58.535 ;
    RECT 271.295 0.000 271.485 58.535 ;
    RECT 271.895 0.000 272.085 58.535 ;
    RECT 272.495 0.000 272.685 58.535 ;
    RECT 273.095 0.000 273.285 58.535 ;
    RECT 273.695 0.000 273.885 58.535 ;
    RECT 274.295 0.000 274.485 58.535 ;
    RECT 274.895 0.000 275.085 58.535 ;
    RECT 275.495 0.000 275.685 58.535 ;
    RECT 276.095 0.000 276.285 58.535 ;
    RECT 276.695 0.000 276.885 58.535 ;
    RECT 277.295 0.000 277.485 58.535 ;
    RECT 277.895 0.000 278.085 58.535 ;
    RECT 278.495 0.000 278.685 58.535 ;
    RECT 279.095 0.000 279.285 58.535 ;
    RECT 279.695 0.000 279.885 58.535 ;
    RECT 280.295 0.000 280.485 58.535 ;
    RECT 280.895 0.000 281.085 58.535 ;
    RECT 281.495 0.000 281.685 58.535 ;
    RECT 282.095 0.000 282.285 58.535 ;
    RECT 282.695 0.000 282.885 58.535 ;
    RECT 283.295 0.000 283.485 58.535 ;
    RECT 283.895 0.000 284.085 58.535 ;
    RECT 284.495 0.000 284.685 58.535 ;
    RECT 285.095 0.000 285.285 58.535 ;
    RECT 285.695 0.000 285.885 58.535 ;
    RECT 286.295 0.000 286.485 58.535 ;
    RECT 286.895 0.000 287.085 58.535 ;
    RECT 287.495 0.000 287.685 58.535 ;
    RECT 288.095 0.000 288.285 58.535 ;
    RECT 288.695 0.000 288.885 58.535 ;
    RECT 289.295 0.000 289.485 58.535 ;
    RECT 289.895 0.000 290.085 58.535 ;
    RECT 290.495 0.000 290.685 58.535 ;
    RECT 291.095 0.000 291.285 58.535 ;
    RECT 291.695 0.000 291.885 58.535 ;
    RECT 292.295 0.000 292.485 58.535 ;
    RECT 292.895 0.000 293.085 58.535 ;
    RECT 293.495 0.000 293.685 58.535 ;
    RECT 294.095 0.000 294.285 58.535 ;
    RECT 294.695 0.000 294.885 58.535 ;
    RECT 295.295 0.000 295.485 58.535 ;
    RECT 295.895 0.000 296.085 58.535 ;
    RECT 296.495 0.000 296.685 58.535 ;
    RECT 297.095 0.000 297.285 58.535 ;
    RECT 297.695 0.000 297.815 58.535 ;
    RECT 298.225 0.000 298.345 58.535 ;
    RECT 298.755 0.000 298.830 58.535 ;
END
END ics55_ecos_sram_256x64_m4
END LIBRARY

